VERSION 5.8 ;
BUSBITCHARS "[]" ;
DIVIDERCHAR "/" ;
UNITS
    DATABASE MICRONS 1000 ;
END UNITS

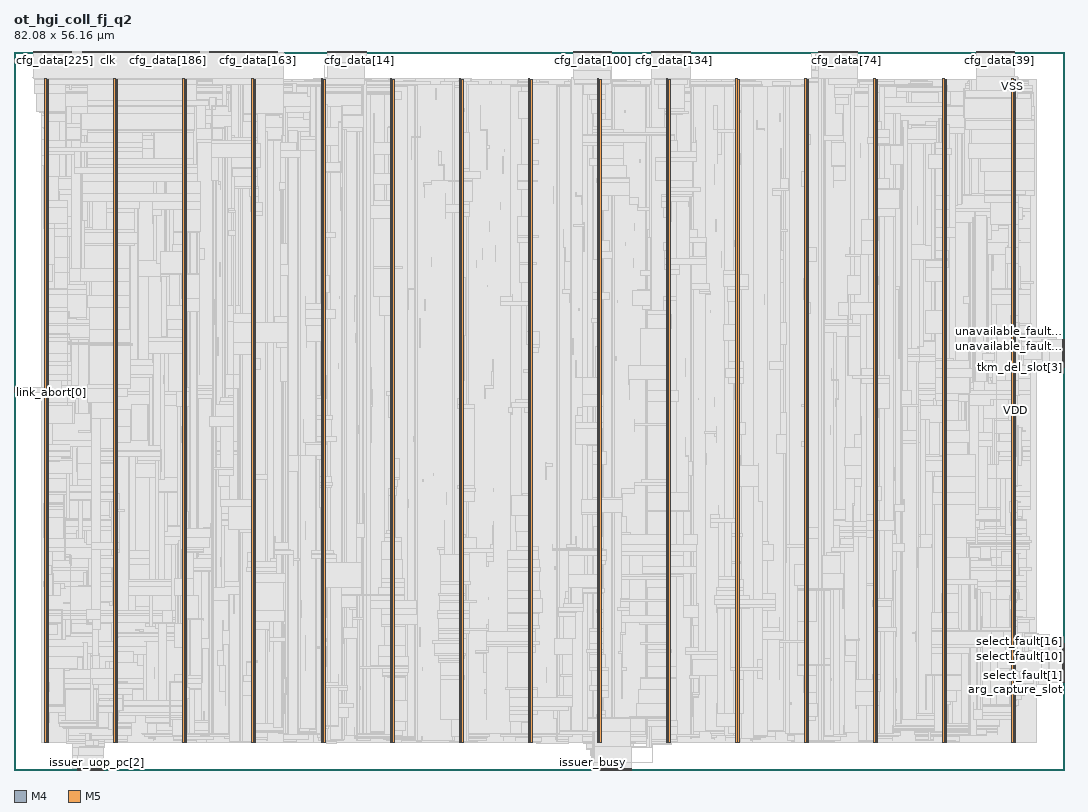
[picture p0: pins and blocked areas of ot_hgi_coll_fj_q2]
MACRO ot_hgi_coll_fj_q2
  FOREIGN ot_hgi_coll_fj_q2 0 0 ;
  CLASS BLOCK ;
  SIZE 82.08 BY 56.16 ;
  PIN arg_capture_slot
    DIRECTION INPUT ;
    USE SIGNAL ;
    PORT
      LAYER M4 ;
        RECT  81.996 6.864 82.08 6.888 ;
    END
  END arg_capture_slot
  PIN capture_fault[0]
    DIRECTION INPUT ;
    USE SIGNAL ;
    PORT
      LAYER M4 ;
        RECT  81.996 6.96 82.08 6.984 ;
    END
  END capture_fault[0]
  PIN capture_fault[1]
    DIRECTION INPUT ;
    USE SIGNAL ;
    PORT
      LAYER M4 ;
        RECT  81.996 7.056 82.08 7.08 ;
    END
  END capture_fault[1]
  PIN capture_fault[2]
    DIRECTION INPUT ;
    USE SIGNAL ;
    PORT
      LAYER M4 ;
        RECT  81.996 7.152 82.08 7.176 ;
    END
  END capture_fault[2]
  PIN capture_fault[3]
    DIRECTION INPUT ;
    USE SIGNAL ;
    PORT
      LAYER M4 ;
        RECT  81.996 7.248 82.08 7.272 ;
    END
  END capture_fault[3]
  PIN capture_fault[4]
    DIRECTION INPUT ;
    USE SIGNAL ;
    PORT
      LAYER M4 ;
        RECT  81.996 7.344 82.08 7.368 ;
    END
  END capture_fault[4]
  PIN capture_fault[5]
    DIRECTION INPUT ;
    USE SIGNAL ;
    PORT
      LAYER M4 ;
        RECT  81.996 7.44 82.08 7.464 ;
    END
  END capture_fault[5]
  PIN capture_fault[6]
    DIRECTION INPUT ;
    USE SIGNAL ;
    PORT
      LAYER M4 ;
        RECT  81.996 7.536 82.08 7.56 ;
    END
  END capture_fault[6]
  PIN capture_fault[7]
    DIRECTION INPUT ;
    USE SIGNAL ;
    PORT
      LAYER M4 ;
        RECT  81.996 7.632 82.08 7.656 ;
    END
  END capture_fault[7]
  PIN capture_fault[8]
    DIRECTION INPUT ;
    USE SIGNAL ;
    PORT
      LAYER M4 ;
        RECT  81.996 7.728 82.08 7.752 ;
    END
  END capture_fault[8]
  PIN cfg_addr[0]
    DIRECTION INPUT ;
    USE SIGNAL ;
    PORT
      LAYER M5 ;
        RECT  24.528 56.076 24.552 56.16 ;
    END
  END cfg_addr[0]
  PIN cfg_addr[10]
    DIRECTION INPUT ;
    USE SIGNAL ;
    PORT
      LAYER M5 ;
        RECT  25.488 56.076 25.512 56.16 ;
    END
  END cfg_addr[10]
  PIN cfg_addr[11]
    DIRECTION INPUT ;
    USE SIGNAL ;
    PORT
      LAYER M5 ;
        RECT  25.584 56.076 25.608 56.16 ;
    END
  END cfg_addr[11]
  PIN cfg_addr[1]
    DIRECTION INPUT ;
    USE SIGNAL ;
    PORT
      LAYER M5 ;
        RECT  24.624 56.076 24.648 56.16 ;
    END
  END cfg_addr[1]
  PIN cfg_addr[2]
    DIRECTION INPUT ;
    USE SIGNAL ;
    PORT
      LAYER M5 ;
        RECT  24.72 56.076 24.744 56.16 ;
    END
  END cfg_addr[2]
  PIN cfg_addr[3]
    DIRECTION INPUT ;
    USE SIGNAL ;
    PORT
      LAYER M5 ;
        RECT  24.816 56.076 24.84 56.16 ;
    END
  END cfg_addr[3]
  PIN cfg_addr[4]
    DIRECTION INPUT ;
    USE SIGNAL ;
    PORT
      LAYER M5 ;
        RECT  24.912 56.076 24.936 56.16 ;
    END
  END cfg_addr[4]
  PIN cfg_addr[5]
    DIRECTION INPUT ;
    USE SIGNAL ;
    PORT
      LAYER M5 ;
        RECT  25.008 56.076 25.032 56.16 ;
    END
  END cfg_addr[5]
  PIN cfg_addr[6]
    DIRECTION INPUT ;
    USE SIGNAL ;
    PORT
      LAYER M5 ;
        RECT  25.104 56.076 25.128 56.16 ;
    END
  END cfg_addr[6]
  PIN cfg_addr[7]
    DIRECTION INPUT ;
    USE SIGNAL ;
    PORT
      LAYER M5 ;
        RECT  25.2 56.076 25.224 56.16 ;
    END
  END cfg_addr[7]
  PIN cfg_addr[8]
    DIRECTION INPUT ;
    USE SIGNAL ;
    PORT
      LAYER M5 ;
        RECT  25.296 56.076 25.32 56.16 ;
    END
  END cfg_addr[8]
  PIN cfg_addr[9]
    DIRECTION INPUT ;
    USE SIGNAL ;
    PORT
      LAYER M5 ;
        RECT  25.392 56.076 25.416 56.16 ;
    END
  END cfg_addr[9]
  PIN cfg_data[0]
    DIRECTION INPUT ;
    USE SIGNAL ;
    PORT
      LAYER M5 ;
        RECT  25.68 56.076 25.704 56.16 ;
    END
  END cfg_data[0]
  PIN cfg_data[100]
    DIRECTION INPUT ;
    USE SIGNAL ;
    PORT
      LAYER M5 ;
        RECT  45.264 56.076 45.288 56.16 ;
    END
  END cfg_data[100]
  PIN cfg_data[101]
    DIRECTION INPUT ;
    USE SIGNAL ;
    PORT
      LAYER M5 ;
        RECT  45.36 56.076 45.384 56.16 ;
    END
  END cfg_data[101]
  PIN cfg_data[102]
    DIRECTION INPUT ;
    USE SIGNAL ;
    PORT
      LAYER M5 ;
        RECT  45.456 56.076 45.48 56.16 ;
    END
  END cfg_data[102]
  PIN cfg_data[103]
    DIRECTION INPUT ;
    USE SIGNAL ;
    PORT
      LAYER M5 ;
        RECT  45.552 56.076 45.576 56.16 ;
    END
  END cfg_data[103]
  PIN cfg_data[104]
    DIRECTION INPUT ;
    USE SIGNAL ;
    PORT
      LAYER M5 ;
        RECT  45.648 56.076 45.672 56.16 ;
    END
  END cfg_data[104]
  PIN cfg_data[105]
    DIRECTION INPUT ;
    USE SIGNAL ;
    PORT
      LAYER M5 ;
        RECT  45.744 56.076 45.768 56.16 ;
    END
  END cfg_data[105]
  PIN cfg_data[106]
    DIRECTION INPUT ;
    USE SIGNAL ;
    PORT
      LAYER M5 ;
        RECT  45.84 56.076 45.864 56.16 ;
    END
  END cfg_data[106]
  PIN cfg_data[107]
    DIRECTION INPUT ;
    USE SIGNAL ;
    PORT
      LAYER M5 ;
        RECT  45.936 56.076 45.96 56.16 ;
    END
  END cfg_data[107]
  PIN cfg_data[108]
    DIRECTION INPUT ;
    USE SIGNAL ;
    PORT
      LAYER M5 ;
        RECT  46.032 56.076 46.056 56.16 ;
    END
  END cfg_data[108]
  PIN cfg_data[109]
    DIRECTION INPUT ;
    USE SIGNAL ;
    PORT
      LAYER M5 ;
        RECT  46.128 56.076 46.152 56.16 ;
    END
  END cfg_data[109]
  PIN cfg_data[10]
    DIRECTION INPUT ;
    USE SIGNAL ;
    PORT
      LAYER M5 ;
        RECT  26.64 56.076 26.664 56.16 ;
    END
  END cfg_data[10]
  PIN cfg_data[110]
    DIRECTION INPUT ;
    USE SIGNAL ;
    PORT
      LAYER M5 ;
        RECT  46.224 56.076 46.248 56.16 ;
    END
  END cfg_data[110]
  PIN cfg_data[111]
    DIRECTION INPUT ;
    USE SIGNAL ;
    PORT
      LAYER M5 ;
        RECT  46.32 56.076 46.344 56.16 ;
    END
  END cfg_data[111]
  PIN cfg_data[112]
    DIRECTION INPUT ;
    USE SIGNAL ;
    PORT
      LAYER M5 ;
        RECT  46.416 56.076 46.44 56.16 ;
    END
  END cfg_data[112]
  PIN cfg_data[113]
    DIRECTION INPUT ;
    USE SIGNAL ;
    PORT
      LAYER M5 ;
        RECT  46.512 56.076 46.536 56.16 ;
    END
  END cfg_data[113]
  PIN cfg_data[114]
    DIRECTION INPUT ;
    USE SIGNAL ;
    PORT
      LAYER M5 ;
        RECT  46.608 56.076 46.632 56.16 ;
    END
  END cfg_data[114]
  PIN cfg_data[115]
    DIRECTION INPUT ;
    USE SIGNAL ;
    PORT
      LAYER M5 ;
        RECT  46.704 56.076 46.728 56.16 ;
    END
  END cfg_data[115]
  PIN cfg_data[116]
    DIRECTION INPUT ;
    USE SIGNAL ;
    PORT
      LAYER M5 ;
        RECT  49.872 56.076 49.896 56.16 ;
    END
  END cfg_data[116]
  PIN cfg_data[117]
    DIRECTION INPUT ;
    USE SIGNAL ;
    PORT
      LAYER M5 ;
        RECT  49.968 56.076 49.992 56.16 ;
    END
  END cfg_data[117]
  PIN cfg_data[118]
    DIRECTION INPUT ;
    USE SIGNAL ;
    PORT
      LAYER M5 ;
        RECT  50.064 56.076 50.088 56.16 ;
    END
  END cfg_data[118]
  PIN cfg_data[119]
    DIRECTION INPUT ;
    USE SIGNAL ;
    PORT
      LAYER M5 ;
        RECT  50.16 56.076 50.184 56.16 ;
    END
  END cfg_data[119]
  PIN cfg_data[11]
    DIRECTION INPUT ;
    USE SIGNAL ;
    PORT
      LAYER M5 ;
        RECT  26.736 56.076 26.76 56.16 ;
    END
  END cfg_data[11]
  PIN cfg_data[120]
    DIRECTION INPUT ;
    USE SIGNAL ;
    PORT
      LAYER M5 ;
        RECT  50.256 56.076 50.28 56.16 ;
    END
  END cfg_data[120]
  PIN cfg_data[121]
    DIRECTION INPUT ;
    USE SIGNAL ;
    PORT
      LAYER M5 ;
        RECT  50.352 56.076 50.376 56.16 ;
    END
  END cfg_data[121]
  PIN cfg_data[122]
    DIRECTION INPUT ;
    USE SIGNAL ;
    PORT
      LAYER M5 ;
        RECT  50.448 56.076 50.472 56.16 ;
    END
  END cfg_data[122]
  PIN cfg_data[123]
    DIRECTION INPUT ;
    USE SIGNAL ;
    PORT
      LAYER M5 ;
        RECT  50.544 56.076 50.568 56.16 ;
    END
  END cfg_data[123]
  PIN cfg_data[124]
    DIRECTION INPUT ;
    USE SIGNAL ;
    PORT
      LAYER M5 ;
        RECT  50.64 56.076 50.664 56.16 ;
    END
  END cfg_data[124]
  PIN cfg_data[125]
    DIRECTION INPUT ;
    USE SIGNAL ;
    PORT
      LAYER M5 ;
        RECT  50.736 56.076 50.76 56.16 ;
    END
  END cfg_data[125]
  PIN cfg_data[126]
    DIRECTION INPUT ;
    USE SIGNAL ;
    PORT
      LAYER M5 ;
        RECT  50.832 56.076 50.856 56.16 ;
    END
  END cfg_data[126]
  PIN cfg_data[127]
    DIRECTION INPUT ;
    USE SIGNAL ;
    PORT
      LAYER M5 ;
        RECT  50.928 56.076 50.952 56.16 ;
    END
  END cfg_data[127]
  PIN cfg_data[128]
    DIRECTION INPUT ;
    USE SIGNAL ;
    PORT
      LAYER M5 ;
        RECT  51.024 56.076 51.048 56.16 ;
    END
  END cfg_data[128]
  PIN cfg_data[129]
    DIRECTION INPUT ;
    USE SIGNAL ;
    PORT
      LAYER M5 ;
        RECT  51.12 56.076 51.144 56.16 ;
    END
  END cfg_data[129]
  PIN cfg_data[12]
    DIRECTION INPUT ;
    USE SIGNAL ;
    PORT
      LAYER M5 ;
        RECT  26.832 56.076 26.856 56.16 ;
    END
  END cfg_data[12]
  PIN cfg_data[130]
    DIRECTION INPUT ;
    USE SIGNAL ;
    PORT
      LAYER M5 ;
        RECT  51.216 56.076 51.24 56.16 ;
    END
  END cfg_data[130]
  PIN cfg_data[131]
    DIRECTION INPUT ;
    USE SIGNAL ;
    PORT
      LAYER M5 ;
        RECT  51.312 56.076 51.336 56.16 ;
    END
  END cfg_data[131]
  PIN cfg_data[132]
    DIRECTION INPUT ;
    USE SIGNAL ;
    PORT
      LAYER M5 ;
        RECT  51.408 56.076 51.432 56.16 ;
    END
  END cfg_data[132]
  PIN cfg_data[133]
    DIRECTION INPUT ;
    USE SIGNAL ;
    PORT
      LAYER M5 ;
        RECT  51.504 56.076 51.528 56.16 ;
    END
  END cfg_data[133]
  PIN cfg_data[134]
    DIRECTION INPUT ;
    USE SIGNAL ;
    PORT
      LAYER M5 ;
        RECT  51.6 56.076 51.624 56.16 ;
    END
  END cfg_data[134]
  PIN cfg_data[135]
    DIRECTION INPUT ;
    USE SIGNAL ;
    PORT
      LAYER M5 ;
        RECT  51.696 56.076 51.72 56.16 ;
    END
  END cfg_data[135]
  PIN cfg_data[136]
    DIRECTION INPUT ;
    USE SIGNAL ;
    PORT
      LAYER M5 ;
        RECT  51.792 56.076 51.816 56.16 ;
    END
  END cfg_data[136]
  PIN cfg_data[137]
    DIRECTION INPUT ;
    USE SIGNAL ;
    PORT
      LAYER M5 ;
        RECT  51.888 56.076 51.912 56.16 ;
    END
  END cfg_data[137]
  PIN cfg_data[138]
    DIRECTION INPUT ;
    USE SIGNAL ;
    PORT
      LAYER M5 ;
        RECT  51.984 56.076 52.008 56.16 ;
    END
  END cfg_data[138]
  PIN cfg_data[139]
    DIRECTION INPUT ;
    USE SIGNAL ;
    PORT
      LAYER M5 ;
        RECT  52.08 56.076 52.104 56.16 ;
    END
  END cfg_data[139]
  PIN cfg_data[13]
    DIRECTION INPUT ;
    USE SIGNAL ;
    PORT
      LAYER M5 ;
        RECT  26.928 56.076 26.952 56.16 ;
    END
  END cfg_data[13]
  PIN cfg_data[140]
    DIRECTION INPUT ;
    USE SIGNAL ;
    PORT
      LAYER M5 ;
        RECT  52.176 56.076 52.2 56.16 ;
    END
  END cfg_data[140]
  PIN cfg_data[141]
    DIRECTION INPUT ;
    USE SIGNAL ;
    PORT
      LAYER M5 ;
        RECT  52.272 56.076 52.296 56.16 ;
    END
  END cfg_data[141]
  PIN cfg_data[142]
    DIRECTION INPUT ;
    USE SIGNAL ;
    PORT
      LAYER M5 ;
        RECT  52.368 56.076 52.392 56.16 ;
    END
  END cfg_data[142]
  PIN cfg_data[143]
    DIRECTION INPUT ;
    USE SIGNAL ;
    PORT
      LAYER M5 ;
        RECT  52.464 56.076 52.488 56.16 ;
    END
  END cfg_data[143]
  PIN cfg_data[144]
    DIRECTION INPUT ;
    USE SIGNAL ;
    PORT
      LAYER M5 ;
        RECT  52.56 56.076 52.584 56.16 ;
    END
  END cfg_data[144]
  PIN cfg_data[145]
    DIRECTION INPUT ;
    USE SIGNAL ;
    PORT
      LAYER M5 ;
        RECT  52.656 56.076 52.68 56.16 ;
    END
  END cfg_data[145]
  PIN cfg_data[146]
    DIRECTION INPUT ;
    USE SIGNAL ;
    PORT
      LAYER M5 ;
        RECT  52.752 56.076 52.776 56.16 ;
    END
  END cfg_data[146]
  PIN cfg_data[147]
    DIRECTION INPUT ;
    USE SIGNAL ;
    PORT
      LAYER M5 ;
        RECT  52.848 56.076 52.872 56.16 ;
    END
  END cfg_data[147]
  PIN cfg_data[148]
    DIRECTION INPUT ;
    USE SIGNAL ;
    PORT
      LAYER M5 ;
        RECT  17.616 56.076 17.64 56.16 ;
    END
  END cfg_data[148]
  PIN cfg_data[149]
    DIRECTION INPUT ;
    USE SIGNAL ;
    PORT
      LAYER M5 ;
        RECT  17.712 56.076 17.736 56.16 ;
    END
  END cfg_data[149]
  PIN cfg_data[14]
    DIRECTION INPUT ;
    USE SIGNAL ;
    PORT
      LAYER M5 ;
        RECT  27.024 56.076 27.048 56.16 ;
    END
  END cfg_data[14]
  PIN cfg_data[150]
    DIRECTION INPUT ;
    USE SIGNAL ;
    PORT
      LAYER M5 ;
        RECT  17.808 56.076 17.832 56.16 ;
    END
  END cfg_data[150]
  PIN cfg_data[151]
    DIRECTION INPUT ;
    USE SIGNAL ;
    PORT
      LAYER M5 ;
        RECT  17.904 56.076 17.928 56.16 ;
    END
  END cfg_data[151]
  PIN cfg_data[152]
    DIRECTION INPUT ;
    USE SIGNAL ;
    PORT
      LAYER M5 ;
        RECT  18 56.076 18.024 56.16 ;
    END
  END cfg_data[152]
  PIN cfg_data[153]
    DIRECTION INPUT ;
    USE SIGNAL ;
    PORT
      LAYER M5 ;
        RECT  18.096 56.076 18.12 56.16 ;
    END
  END cfg_data[153]
  PIN cfg_data[154]
    DIRECTION INPUT ;
    USE SIGNAL ;
    PORT
      LAYER M5 ;
        RECT  18.192 56.076 18.216 56.16 ;
    END
  END cfg_data[154]
  PIN cfg_data[155]
    DIRECTION INPUT ;
    USE SIGNAL ;
    PORT
      LAYER M5 ;
        RECT  18.288 56.076 18.312 56.16 ;
    END
  END cfg_data[155]
  PIN cfg_data[156]
    DIRECTION INPUT ;
    USE SIGNAL ;
    PORT
      LAYER M5 ;
        RECT  18.384 56.076 18.408 56.16 ;
    END
  END cfg_data[156]
  PIN cfg_data[157]
    DIRECTION INPUT ;
    USE SIGNAL ;
    PORT
      LAYER M5 ;
        RECT  18.48 56.076 18.504 56.16 ;
    END
  END cfg_data[157]
  PIN cfg_data[158]
    DIRECTION INPUT ;
    USE SIGNAL ;
    PORT
      LAYER M5 ;
        RECT  18.576 56.076 18.6 56.16 ;
    END
  END cfg_data[158]
  PIN cfg_data[159]
    DIRECTION INPUT ;
    USE SIGNAL ;
    PORT
      LAYER M5 ;
        RECT  18.672 56.076 18.696 56.16 ;
    END
  END cfg_data[159]
  PIN cfg_data[15]
    DIRECTION INPUT ;
    USE SIGNAL ;
    PORT
      LAYER M5 ;
        RECT  27.12 56.076 27.144 56.16 ;
    END
  END cfg_data[15]
  PIN cfg_data[160]
    DIRECTION INPUT ;
    USE SIGNAL ;
    PORT
      LAYER M5 ;
        RECT  18.768 56.076 18.792 56.16 ;
    END
  END cfg_data[160]
  PIN cfg_data[161]
    DIRECTION INPUT ;
    USE SIGNAL ;
    PORT
      LAYER M5 ;
        RECT  18.864 56.076 18.888 56.16 ;
    END
  END cfg_data[161]
  PIN cfg_data[162]
    DIRECTION INPUT ;
    USE SIGNAL ;
    PORT
      LAYER M5 ;
        RECT  18.96 56.076 18.984 56.16 ;
    END
  END cfg_data[162]
  PIN cfg_data[163]
    DIRECTION INPUT ;
    USE SIGNAL ;
    PORT
      LAYER M5 ;
        RECT  19.056 56.076 19.08 56.16 ;
    END
  END cfg_data[163]
  PIN cfg_data[164]
    DIRECTION INPUT ;
    USE SIGNAL ;
    PORT
      LAYER M5 ;
        RECT  19.152 56.076 19.176 56.16 ;
    END
  END cfg_data[164]
  PIN cfg_data[165]
    DIRECTION INPUT ;
    USE SIGNAL ;
    PORT
      LAYER M5 ;
        RECT  19.248 56.076 19.272 56.16 ;
    END
  END cfg_data[165]
  PIN cfg_data[166]
    DIRECTION INPUT ;
    USE SIGNAL ;
    PORT
      LAYER M5 ;
        RECT  19.344 56.076 19.368 56.16 ;
    END
  END cfg_data[166]
  PIN cfg_data[167]
    DIRECTION INPUT ;
    USE SIGNAL ;
    PORT
      LAYER M5 ;
        RECT  19.44 56.076 19.464 56.16 ;
    END
  END cfg_data[167]
  PIN cfg_data[168]
    DIRECTION INPUT ;
    USE SIGNAL ;
    PORT
      LAYER M5 ;
        RECT  19.536 56.076 19.56 56.16 ;
    END
  END cfg_data[168]
  PIN cfg_data[169]
    DIRECTION INPUT ;
    USE SIGNAL ;
    PORT
      LAYER M5 ;
        RECT  19.632 56.076 19.656 56.16 ;
    END
  END cfg_data[169]
  PIN cfg_data[16]
    DIRECTION INPUT ;
    USE SIGNAL ;
    PORT
      LAYER M5 ;
        RECT  27.216 56.076 27.24 56.16 ;
    END
  END cfg_data[16]
  PIN cfg_data[170]
    DIRECTION INPUT ;
    USE SIGNAL ;
    PORT
      LAYER M5 ;
        RECT  19.728 56.076 19.752 56.16 ;
    END
  END cfg_data[170]
  PIN cfg_data[171]
    DIRECTION INPUT ;
    USE SIGNAL ;
    PORT
      LAYER M5 ;
        RECT  19.824 56.076 19.848 56.16 ;
    END
  END cfg_data[171]
  PIN cfg_data[172]
    DIRECTION INPUT ;
    USE SIGNAL ;
    PORT
      LAYER M5 ;
        RECT  19.92 56.076 19.944 56.16 ;
    END
  END cfg_data[172]
  PIN cfg_data[173]
    DIRECTION INPUT ;
    USE SIGNAL ;
    PORT
      LAYER M5 ;
        RECT  20.016 56.076 20.04 56.16 ;
    END
  END cfg_data[173]
  PIN cfg_data[174]
    DIRECTION INPUT ;
    USE SIGNAL ;
    PORT
      LAYER M5 ;
        RECT  20.112 56.076 20.136 56.16 ;
    END
  END cfg_data[174]
  PIN cfg_data[175]
    DIRECTION INPUT ;
    USE SIGNAL ;
    PORT
      LAYER M5 ;
        RECT  20.208 56.076 20.232 56.16 ;
    END
  END cfg_data[175]
  PIN cfg_data[176]
    DIRECTION INPUT ;
    USE SIGNAL ;
    PORT
      LAYER M5 ;
        RECT  20.304 56.076 20.328 56.16 ;
    END
  END cfg_data[176]
  PIN cfg_data[177]
    DIRECTION INPUT ;
    USE SIGNAL ;
    PORT
      LAYER M5 ;
        RECT  20.4 56.076 20.424 56.16 ;
    END
  END cfg_data[177]
  PIN cfg_data[178]
    DIRECTION INPUT ;
    USE SIGNAL ;
    PORT
      LAYER M5 ;
        RECT  20.496 56.076 20.52 56.16 ;
    END
  END cfg_data[178]
  PIN cfg_data[179]
    DIRECTION INPUT ;
    USE SIGNAL ;
    PORT
      LAYER M5 ;
        RECT  20.592 56.076 20.616 56.16 ;
    END
  END cfg_data[179]
  PIN cfg_data[17]
    DIRECTION INPUT ;
    USE SIGNAL ;
    PORT
      LAYER M5 ;
        RECT  27.312 56.076 27.336 56.16 ;
    END
  END cfg_data[17]
  PIN cfg_data[180]
    DIRECTION INPUT ;
    USE SIGNAL ;
    PORT
      LAYER M5 ;
        RECT  11.472 56.076 11.496 56.16 ;
    END
  END cfg_data[180]
  PIN cfg_data[181]
    DIRECTION INPUT ;
    USE SIGNAL ;
    PORT
      LAYER M5 ;
        RECT  11.568 56.076 11.592 56.16 ;
    END
  END cfg_data[181]
  PIN cfg_data[182]
    DIRECTION INPUT ;
    USE SIGNAL ;
    PORT
      LAYER M5 ;
        RECT  11.664 56.076 11.688 56.16 ;
    END
  END cfg_data[182]
  PIN cfg_data[183]
    DIRECTION INPUT ;
    USE SIGNAL ;
    PORT
      LAYER M5 ;
        RECT  11.76 56.076 11.784 56.16 ;
    END
  END cfg_data[183]
  PIN cfg_data[184]
    DIRECTION INPUT ;
    USE SIGNAL ;
    PORT
      LAYER M5 ;
        RECT  11.856 56.076 11.88 56.16 ;
    END
  END cfg_data[184]
  PIN cfg_data[185]
    DIRECTION INPUT ;
    USE SIGNAL ;
    PORT
      LAYER M5 ;
        RECT  11.952 56.076 11.976 56.16 ;
    END
  END cfg_data[185]
  PIN cfg_data[186]
    DIRECTION INPUT ;
    USE SIGNAL ;
    PORT
      LAYER M5 ;
        RECT  12.048 56.076 12.072 56.16 ;
    END
  END cfg_data[186]
  PIN cfg_data[187]
    DIRECTION INPUT ;
    USE SIGNAL ;
    PORT
      LAYER M5 ;
        RECT  12.144 56.076 12.168 56.16 ;
    END
  END cfg_data[187]
  PIN cfg_data[188]
    DIRECTION INPUT ;
    USE SIGNAL ;
    PORT
      LAYER M5 ;
        RECT  12.24 56.076 12.264 56.16 ;
    END
  END cfg_data[188]
  PIN cfg_data[189]
    DIRECTION INPUT ;
    USE SIGNAL ;
    PORT
      LAYER M5 ;
        RECT  12.336 56.076 12.36 56.16 ;
    END
  END cfg_data[189]
  PIN cfg_data[18]
    DIRECTION INPUT ;
    USE SIGNAL ;
    PORT
      LAYER M5 ;
        RECT  27.408 56.076 27.432 56.16 ;
    END
  END cfg_data[18]
  PIN cfg_data[190]
    DIRECTION INPUT ;
    USE SIGNAL ;
    PORT
      LAYER M5 ;
        RECT  12.432 56.076 12.456 56.16 ;
    END
  END cfg_data[190]
  PIN cfg_data[191]
    DIRECTION INPUT ;
    USE SIGNAL ;
    PORT
      LAYER M5 ;
        RECT  12.528 56.076 12.552 56.16 ;
    END
  END cfg_data[191]
  PIN cfg_data[192]
    DIRECTION INPUT ;
    USE SIGNAL ;
    PORT
      LAYER M5 ;
        RECT  12.624 56.076 12.648 56.16 ;
    END
  END cfg_data[192]
  PIN cfg_data[193]
    DIRECTION INPUT ;
    USE SIGNAL ;
    PORT
      LAYER M5 ;
        RECT  12.72 56.076 12.744 56.16 ;
    END
  END cfg_data[193]
  PIN cfg_data[194]
    DIRECTION INPUT ;
    USE SIGNAL ;
    PORT
      LAYER M5 ;
        RECT  12.816 56.076 12.84 56.16 ;
    END
  END cfg_data[194]
  PIN cfg_data[195]
    DIRECTION INPUT ;
    USE SIGNAL ;
    PORT
      LAYER M5 ;
        RECT  12.912 56.076 12.936 56.16 ;
    END
  END cfg_data[195]
  PIN cfg_data[196]
    DIRECTION INPUT ;
    USE SIGNAL ;
    PORT
      LAYER M5 ;
        RECT  13.008 56.076 13.032 56.16 ;
    END
  END cfg_data[196]
  PIN cfg_data[197]
    DIRECTION INPUT ;
    USE SIGNAL ;
    PORT
      LAYER M5 ;
        RECT  13.104 56.076 13.128 56.16 ;
    END
  END cfg_data[197]
  PIN cfg_data[198]
    DIRECTION INPUT ;
    USE SIGNAL ;
    PORT
      LAYER M5 ;
        RECT  13.2 56.076 13.224 56.16 ;
    END
  END cfg_data[198]
  PIN cfg_data[199]
    DIRECTION INPUT ;
    USE SIGNAL ;
    PORT
      LAYER M5 ;
        RECT  13.296 56.076 13.32 56.16 ;
    END
  END cfg_data[199]
  PIN cfg_data[19]
    DIRECTION INPUT ;
    USE SIGNAL ;
    PORT
      LAYER M5 ;
        RECT  27.504 56.076 27.528 56.16 ;
    END
  END cfg_data[19]
  PIN cfg_data[1]
    DIRECTION INPUT ;
    USE SIGNAL ;
    PORT
      LAYER M5 ;
        RECT  25.776 56.076 25.8 56.16 ;
    END
  END cfg_data[1]
  PIN cfg_data[200]
    DIRECTION INPUT ;
    USE SIGNAL ;
    PORT
      LAYER M5 ;
        RECT  13.392 56.076 13.416 56.16 ;
    END
  END cfg_data[200]
  PIN cfg_data[201]
    DIRECTION INPUT ;
    USE SIGNAL ;
    PORT
      LAYER M5 ;
        RECT  13.488 56.076 13.512 56.16 ;
    END
  END cfg_data[201]
  PIN cfg_data[202]
    DIRECTION INPUT ;
    USE SIGNAL ;
    PORT
      LAYER M5 ;
        RECT  13.584 56.076 13.608 56.16 ;
    END
  END cfg_data[202]
  PIN cfg_data[203]
    DIRECTION INPUT ;
    USE SIGNAL ;
    PORT
      LAYER M5 ;
        RECT  13.68 56.076 13.704 56.16 ;
    END
  END cfg_data[203]
  PIN cfg_data[204]
    DIRECTION INPUT ;
    USE SIGNAL ;
    PORT
      LAYER M5 ;
        RECT  13.776 56.076 13.8 56.16 ;
    END
  END cfg_data[204]
  PIN cfg_data[205]
    DIRECTION INPUT ;
    USE SIGNAL ;
    PORT
      LAYER M5 ;
        RECT  13.872 56.076 13.896 56.16 ;
    END
  END cfg_data[205]
  PIN cfg_data[206]
    DIRECTION INPUT ;
    USE SIGNAL ;
    PORT
      LAYER M5 ;
        RECT  13.968 56.076 13.992 56.16 ;
    END
  END cfg_data[206]
  PIN cfg_data[207]
    DIRECTION INPUT ;
    USE SIGNAL ;
    PORT
      LAYER M5 ;
        RECT  14.064 56.076 14.088 56.16 ;
    END
  END cfg_data[207]
  PIN cfg_data[208]
    DIRECTION INPUT ;
    USE SIGNAL ;
    PORT
      LAYER M5 ;
        RECT  14.16 56.076 14.184 56.16 ;
    END
  END cfg_data[208]
  PIN cfg_data[209]
    DIRECTION INPUT ;
    USE SIGNAL ;
    PORT
      LAYER M5 ;
        RECT  14.256 56.076 14.28 56.16 ;
    END
  END cfg_data[209]
  PIN cfg_data[20]
    DIRECTION INPUT ;
    USE SIGNAL ;
    PORT
      LAYER M5 ;
        RECT  75.216 56.076 75.24 56.16 ;
    END
  END cfg_data[20]
  PIN cfg_data[210]
    DIRECTION INPUT ;
    USE SIGNAL ;
    PORT
      LAYER M5 ;
        RECT  14.352 56.076 14.376 56.16 ;
    END
  END cfg_data[210]
  PIN cfg_data[211]
    DIRECTION INPUT ;
    USE SIGNAL ;
    PORT
      LAYER M5 ;
        RECT  14.448 56.076 14.472 56.16 ;
    END
  END cfg_data[211]
  PIN cfg_data[212]
    DIRECTION INPUT ;
    USE SIGNAL ;
    PORT
      LAYER M5 ;
        RECT  1.488 56.076 1.512 56.16 ;
    END
  END cfg_data[212]
  PIN cfg_data[213]
    DIRECTION INPUT ;
    USE SIGNAL ;
    PORT
      LAYER M5 ;
        RECT  1.584 56.076 1.608 56.16 ;
    END
  END cfg_data[213]
  PIN cfg_data[214]
    DIRECTION INPUT ;
    USE SIGNAL ;
    PORT
      LAYER M5 ;
        RECT  1.68 56.076 1.704 56.16 ;
    END
  END cfg_data[214]
  PIN cfg_data[215]
    DIRECTION INPUT ;
    USE SIGNAL ;
    PORT
      LAYER M5 ;
        RECT  1.776 56.076 1.8 56.16 ;
    END
  END cfg_data[215]
  PIN cfg_data[216]
    DIRECTION INPUT ;
    USE SIGNAL ;
    PORT
      LAYER M5 ;
        RECT  1.872 56.076 1.896 56.16 ;
    END
  END cfg_data[216]
  PIN cfg_data[217]
    DIRECTION INPUT ;
    USE SIGNAL ;
    PORT
      LAYER M5 ;
        RECT  1.968 56.076 1.992 56.16 ;
    END
  END cfg_data[217]
  PIN cfg_data[218]
    DIRECTION INPUT ;
    USE SIGNAL ;
    PORT
      LAYER M5 ;
        RECT  2.064 56.076 2.088 56.16 ;
    END
  END cfg_data[218]
  PIN cfg_data[219]
    DIRECTION INPUT ;
    USE SIGNAL ;
    PORT
      LAYER M5 ;
        RECT  2.16 56.076 2.184 56.16 ;
    END
  END cfg_data[219]
  PIN cfg_data[21]
    DIRECTION INPUT ;
    USE SIGNAL ;
    PORT
      LAYER M5 ;
        RECT  75.312 56.076 75.336 56.16 ;
    END
  END cfg_data[21]
  PIN cfg_data[220]
    DIRECTION INPUT ;
    USE SIGNAL ;
    PORT
      LAYER M5 ;
        RECT  2.256 56.076 2.28 56.16 ;
    END
  END cfg_data[220]
  PIN cfg_data[221]
    DIRECTION INPUT ;
    USE SIGNAL ;
    PORT
      LAYER M5 ;
        RECT  2.352 56.076 2.376 56.16 ;
    END
  END cfg_data[221]
  PIN cfg_data[222]
    DIRECTION INPUT ;
    USE SIGNAL ;
    PORT
      LAYER M5 ;
        RECT  2.448 56.076 2.472 56.16 ;
    END
  END cfg_data[222]
  PIN cfg_data[223]
    DIRECTION INPUT ;
    USE SIGNAL ;
    PORT
      LAYER M5 ;
        RECT  2.544 56.076 2.568 56.16 ;
    END
  END cfg_data[223]
  PIN cfg_data[224]
    DIRECTION INPUT ;
    USE SIGNAL ;
    PORT
      LAYER M5 ;
        RECT  2.64 56.076 2.664 56.16 ;
    END
  END cfg_data[224]
  PIN cfg_data[225]
    DIRECTION INPUT ;
    USE SIGNAL ;
    PORT
      LAYER M5 ;
        RECT  2.736 56.076 2.76 56.16 ;
    END
  END cfg_data[225]
  PIN cfg_data[226]
    DIRECTION INPUT ;
    USE SIGNAL ;
    PORT
      LAYER M5 ;
        RECT  2.832 56.076 2.856 56.16 ;
    END
  END cfg_data[226]
  PIN cfg_data[227]
    DIRECTION INPUT ;
    USE SIGNAL ;
    PORT
      LAYER M5 ;
        RECT  2.928 56.076 2.952 56.16 ;
    END
  END cfg_data[227]
  PIN cfg_data[228]
    DIRECTION INPUT ;
    USE SIGNAL ;
    PORT
      LAYER M5 ;
        RECT  3.024 56.076 3.048 56.16 ;
    END
  END cfg_data[228]
  PIN cfg_data[229]
    DIRECTION INPUT ;
    USE SIGNAL ;
    PORT
      LAYER M5 ;
        RECT  3.12 56.076 3.144 56.16 ;
    END
  END cfg_data[229]
  PIN cfg_data[22]
    DIRECTION INPUT ;
    USE SIGNAL ;
    PORT
      LAYER M5 ;
        RECT  75.408 56.076 75.432 56.16 ;
    END
  END cfg_data[22]
  PIN cfg_data[230]
    DIRECTION INPUT ;
    USE SIGNAL ;
    PORT
      LAYER M5 ;
        RECT  3.216 56.076 3.24 56.16 ;
    END
  END cfg_data[230]
  PIN cfg_data[231]
    DIRECTION INPUT ;
    USE SIGNAL ;
    PORT
      LAYER M5 ;
        RECT  3.312 56.076 3.336 56.16 ;
    END
  END cfg_data[231]
  PIN cfg_data[232]
    DIRECTION INPUT ;
    USE SIGNAL ;
    PORT
      LAYER M5 ;
        RECT  3.408 56.076 3.432 56.16 ;
    END
  END cfg_data[232]
  PIN cfg_data[233]
    DIRECTION INPUT ;
    USE SIGNAL ;
    PORT
      LAYER M5 ;
        RECT  3.504 56.076 3.528 56.16 ;
    END
  END cfg_data[233]
  PIN cfg_data[234]
    DIRECTION INPUT ;
    USE SIGNAL ;
    PORT
      LAYER M5 ;
        RECT  3.6 56.076 3.624 56.16 ;
    END
  END cfg_data[234]
  PIN cfg_data[235]
    DIRECTION INPUT ;
    USE SIGNAL ;
    PORT
      LAYER M5 ;
        RECT  3.696 56.076 3.72 56.16 ;
    END
  END cfg_data[235]
  PIN cfg_data[236]
    DIRECTION INPUT ;
    USE SIGNAL ;
    PORT
      LAYER M5 ;
        RECT  3.792 56.076 3.816 56.16 ;
    END
  END cfg_data[236]
  PIN cfg_data[237]
    DIRECTION INPUT ;
    USE SIGNAL ;
    PORT
      LAYER M5 ;
        RECT  3.888 56.076 3.912 56.16 ;
    END
  END cfg_data[237]
  PIN cfg_data[238]
    DIRECTION INPUT ;
    USE SIGNAL ;
    PORT
      LAYER M5 ;
        RECT  3.984 56.076 4.008 56.16 ;
    END
  END cfg_data[238]
  PIN cfg_data[239]
    DIRECTION INPUT ;
    USE SIGNAL ;
    PORT
      LAYER M5 ;
        RECT  4.08 56.076 4.104 56.16 ;
    END
  END cfg_data[239]
  PIN cfg_data[23]
    DIRECTION INPUT ;
    USE SIGNAL ;
    PORT
      LAYER M5 ;
        RECT  75.504 56.076 75.528 56.16 ;
    END
  END cfg_data[23]
  PIN cfg_data[240]
    DIRECTION INPUT ;
    USE SIGNAL ;
    PORT
      LAYER M5 ;
        RECT  4.176 56.076 4.2 56.16 ;
    END
  END cfg_data[240]
  PIN cfg_data[241]
    DIRECTION INPUT ;
    USE SIGNAL ;
    PORT
      LAYER M5 ;
        RECT  4.272 56.076 4.296 56.16 ;
    END
  END cfg_data[241]
  PIN cfg_data[242]
    DIRECTION INPUT ;
    USE SIGNAL ;
    PORT
      LAYER M5 ;
        RECT  4.368 56.076 4.392 56.16 ;
    END
  END cfg_data[242]
  PIN cfg_data[243]
    DIRECTION INPUT ;
    USE SIGNAL ;
    PORT
      LAYER M5 ;
        RECT  4.464 56.076 4.488 56.16 ;
    END
  END cfg_data[243]
  PIN cfg_data[244]
    DIRECTION INPUT ;
    USE SIGNAL ;
    PORT
      LAYER M5 ;
        RECT  5.328 56.076 5.352 56.16 ;
    END
  END cfg_data[244]
  PIN cfg_data[245]
    DIRECTION INPUT ;
    USE SIGNAL ;
    PORT
      LAYER M5 ;
        RECT  5.424 56.076 5.448 56.16 ;
    END
  END cfg_data[245]
  PIN cfg_data[246]
    DIRECTION INPUT ;
    USE SIGNAL ;
    PORT
      LAYER M5 ;
        RECT  5.52 56.076 5.544 56.16 ;
    END
  END cfg_data[246]
  PIN cfg_data[247]
    DIRECTION INPUT ;
    USE SIGNAL ;
    PORT
      LAYER M5 ;
        RECT  5.616 56.076 5.64 56.16 ;
    END
  END cfg_data[247]
  PIN cfg_data[248]
    DIRECTION INPUT ;
    USE SIGNAL ;
    PORT
      LAYER M5 ;
        RECT  5.712 56.076 5.736 56.16 ;
    END
  END cfg_data[248]
  PIN cfg_data[249]
    DIRECTION INPUT ;
    USE SIGNAL ;
    PORT
      LAYER M5 ;
        RECT  5.808 56.076 5.832 56.16 ;
    END
  END cfg_data[249]
  PIN cfg_data[24]
    DIRECTION INPUT ;
    USE SIGNAL ;
    PORT
      LAYER M5 ;
        RECT  75.6 56.076 75.624 56.16 ;
    END
  END cfg_data[24]
  PIN cfg_data[250]
    DIRECTION INPUT ;
    USE SIGNAL ;
    PORT
      LAYER M5 ;
        RECT  5.904 56.076 5.928 56.16 ;
    END
  END cfg_data[250]
  PIN cfg_data[251]
    DIRECTION INPUT ;
    USE SIGNAL ;
    PORT
      LAYER M5 ;
        RECT  6 56.076 6.024 56.16 ;
    END
  END cfg_data[251]
  PIN cfg_data[252]
    DIRECTION INPUT ;
    USE SIGNAL ;
    PORT
      LAYER M5 ;
        RECT  6.096 56.076 6.12 56.16 ;
    END
  END cfg_data[252]
  PIN cfg_data[253]
    DIRECTION INPUT ;
    USE SIGNAL ;
    PORT
      LAYER M5 ;
        RECT  6.192 56.076 6.216 56.16 ;
    END
  END cfg_data[253]
  PIN cfg_data[254]
    DIRECTION INPUT ;
    USE SIGNAL ;
    PORT
      LAYER M5 ;
        RECT  6.288 56.076 6.312 56.16 ;
    END
  END cfg_data[254]
  PIN cfg_data[255]
    DIRECTION INPUT ;
    USE SIGNAL ;
    PORT
      LAYER M5 ;
        RECT  6.384 56.076 6.408 56.16 ;
    END
  END cfg_data[255]
  PIN cfg_data[25]
    DIRECTION INPUT ;
    USE SIGNAL ;
    PORT
      LAYER M5 ;
        RECT  75.696 56.076 75.72 56.16 ;
    END
  END cfg_data[25]
  PIN cfg_data[26]
    DIRECTION INPUT ;
    USE SIGNAL ;
    PORT
      LAYER M5 ;
        RECT  75.792 56.076 75.816 56.16 ;
    END
  END cfg_data[26]
  PIN cfg_data[27]
    DIRECTION INPUT ;
    USE SIGNAL ;
    PORT
      LAYER M5 ;
        RECT  75.888 56.076 75.912 56.16 ;
    END
  END cfg_data[27]
  PIN cfg_data[28]
    DIRECTION INPUT ;
    USE SIGNAL ;
    PORT
      LAYER M5 ;
        RECT  75.984 56.076 76.008 56.16 ;
    END
  END cfg_data[28]
  PIN cfg_data[29]
    DIRECTION INPUT ;
    USE SIGNAL ;
    PORT
      LAYER M5 ;
        RECT  76.08 56.076 76.104 56.16 ;
    END
  END cfg_data[29]
  PIN cfg_data[2]
    DIRECTION INPUT ;
    USE SIGNAL ;
    PORT
      LAYER M5 ;
        RECT  25.872 56.076 25.896 56.16 ;
    END
  END cfg_data[2]
  PIN cfg_data[30]
    DIRECTION INPUT ;
    USE SIGNAL ;
    PORT
      LAYER M5 ;
        RECT  76.176 56.076 76.2 56.16 ;
    END
  END cfg_data[30]
  PIN cfg_data[31]
    DIRECTION INPUT ;
    USE SIGNAL ;
    PORT
      LAYER M5 ;
        RECT  76.272 56.076 76.296 56.16 ;
    END
  END cfg_data[31]
  PIN cfg_data[32]
    DIRECTION INPUT ;
    USE SIGNAL ;
    PORT
      LAYER M5 ;
        RECT  76.368 56.076 76.392 56.16 ;
    END
  END cfg_data[32]
  PIN cfg_data[33]
    DIRECTION INPUT ;
    USE SIGNAL ;
    PORT
      LAYER M5 ;
        RECT  76.464 56.076 76.488 56.16 ;
    END
  END cfg_data[33]
  PIN cfg_data[34]
    DIRECTION INPUT ;
    USE SIGNAL ;
    PORT
      LAYER M5 ;
        RECT  76.56 56.076 76.584 56.16 ;
    END
  END cfg_data[34]
  PIN cfg_data[35]
    DIRECTION INPUT ;
    USE SIGNAL ;
    PORT
      LAYER M5 ;
        RECT  76.656 56.076 76.68 56.16 ;
    END
  END cfg_data[35]
  PIN cfg_data[36]
    DIRECTION INPUT ;
    USE SIGNAL ;
    PORT
      LAYER M5 ;
        RECT  76.752 56.076 76.776 56.16 ;
    END
  END cfg_data[36]
  PIN cfg_data[37]
    DIRECTION INPUT ;
    USE SIGNAL ;
    PORT
      LAYER M5 ;
        RECT  76.848 56.076 76.872 56.16 ;
    END
  END cfg_data[37]
  PIN cfg_data[38]
    DIRECTION INPUT ;
    USE SIGNAL ;
    PORT
      LAYER M5 ;
        RECT  76.944 56.076 76.968 56.16 ;
    END
  END cfg_data[38]
  PIN cfg_data[39]
    DIRECTION INPUT ;
    USE SIGNAL ;
    PORT
      LAYER M5 ;
        RECT  77.04 56.076 77.064 56.16 ;
    END
  END cfg_data[39]
  PIN cfg_data[3]
    DIRECTION INPUT ;
    USE SIGNAL ;
    PORT
      LAYER M5 ;
        RECT  25.968 56.076 25.992 56.16 ;
    END
  END cfg_data[3]
  PIN cfg_data[40]
    DIRECTION INPUT ;
    USE SIGNAL ;
    PORT
      LAYER M5 ;
        RECT  77.136 56.076 77.16 56.16 ;
    END
  END cfg_data[40]
  PIN cfg_data[41]
    DIRECTION INPUT ;
    USE SIGNAL ;
    PORT
      LAYER M5 ;
        RECT  77.232 56.076 77.256 56.16 ;
    END
  END cfg_data[41]
  PIN cfg_data[42]
    DIRECTION INPUT ;
    USE SIGNAL ;
    PORT
      LAYER M5 ;
        RECT  77.328 56.076 77.352 56.16 ;
    END
  END cfg_data[42]
  PIN cfg_data[43]
    DIRECTION INPUT ;
    USE SIGNAL ;
    PORT
      LAYER M5 ;
        RECT  77.424 56.076 77.448 56.16 ;
    END
  END cfg_data[43]
  PIN cfg_data[44]
    DIRECTION INPUT ;
    USE SIGNAL ;
    PORT
      LAYER M5 ;
        RECT  77.52 56.076 77.544 56.16 ;
    END
  END cfg_data[44]
  PIN cfg_data[45]
    DIRECTION INPUT ;
    USE SIGNAL ;
    PORT
      LAYER M5 ;
        RECT  77.616 56.076 77.64 56.16 ;
    END
  END cfg_data[45]
  PIN cfg_data[46]
    DIRECTION INPUT ;
    USE SIGNAL ;
    PORT
      LAYER M5 ;
        RECT  77.712 56.076 77.736 56.16 ;
    END
  END cfg_data[46]
  PIN cfg_data[47]
    DIRECTION INPUT ;
    USE SIGNAL ;
    PORT
      LAYER M5 ;
        RECT  77.808 56.076 77.832 56.16 ;
    END
  END cfg_data[47]
  PIN cfg_data[48]
    DIRECTION INPUT ;
    USE SIGNAL ;
    PORT
      LAYER M5 ;
        RECT  77.904 56.076 77.928 56.16 ;
    END
  END cfg_data[48]
  PIN cfg_data[49]
    DIRECTION INPUT ;
    USE SIGNAL ;
    PORT
      LAYER M5 ;
        RECT  78 56.076 78.024 56.16 ;
    END
  END cfg_data[49]
  PIN cfg_data[4]
    DIRECTION INPUT ;
    USE SIGNAL ;
    PORT
      LAYER M5 ;
        RECT  26.064 56.076 26.088 56.16 ;
    END
  END cfg_data[4]
  PIN cfg_data[50]
    DIRECTION INPUT ;
    USE SIGNAL ;
    PORT
      LAYER M5 ;
        RECT  78.096 56.076 78.12 56.16 ;
    END
  END cfg_data[50]
  PIN cfg_data[51]
    DIRECTION INPUT ;
    USE SIGNAL ;
    PORT
      LAYER M5 ;
        RECT  78.192 56.076 78.216 56.16 ;
    END
  END cfg_data[51]
  PIN cfg_data[52]
    DIRECTION INPUT ;
    USE SIGNAL ;
    PORT
      LAYER M5 ;
        RECT  62.928 56.076 62.952 56.16 ;
    END
  END cfg_data[52]
  PIN cfg_data[53]
    DIRECTION INPUT ;
    USE SIGNAL ;
    PORT
      LAYER M5 ;
        RECT  63.024 56.076 63.048 56.16 ;
    END
  END cfg_data[53]
  PIN cfg_data[54]
    DIRECTION INPUT ;
    USE SIGNAL ;
    PORT
      LAYER M5 ;
        RECT  63.12 56.076 63.144 56.16 ;
    END
  END cfg_data[54]
  PIN cfg_data[55]
    DIRECTION INPUT ;
    USE SIGNAL ;
    PORT
      LAYER M5 ;
        RECT  63.216 56.076 63.24 56.16 ;
    END
  END cfg_data[55]
  PIN cfg_data[56]
    DIRECTION INPUT ;
    USE SIGNAL ;
    PORT
      LAYER M5 ;
        RECT  63.312 56.076 63.336 56.16 ;
    END
  END cfg_data[56]
  PIN cfg_data[57]
    DIRECTION INPUT ;
    USE SIGNAL ;
    PORT
      LAYER M5 ;
        RECT  63.408 56.076 63.432 56.16 ;
    END
  END cfg_data[57]
  PIN cfg_data[58]
    DIRECTION INPUT ;
    USE SIGNAL ;
    PORT
      LAYER M5 ;
        RECT  63.504 56.076 63.528 56.16 ;
    END
  END cfg_data[58]
  PIN cfg_data[59]
    DIRECTION INPUT ;
    USE SIGNAL ;
    PORT
      LAYER M5 ;
        RECT  63.6 56.076 63.624 56.16 ;
    END
  END cfg_data[59]
  PIN cfg_data[5]
    DIRECTION INPUT ;
    USE SIGNAL ;
    PORT
      LAYER M5 ;
        RECT  26.16 56.076 26.184 56.16 ;
    END
  END cfg_data[5]
  PIN cfg_data[60]
    DIRECTION INPUT ;
    USE SIGNAL ;
    PORT
      LAYER M5 ;
        RECT  63.696 56.076 63.72 56.16 ;
    END
  END cfg_data[60]
  PIN cfg_data[61]
    DIRECTION INPUT ;
    USE SIGNAL ;
    PORT
      LAYER M5 ;
        RECT  63.792 56.076 63.816 56.16 ;
    END
  END cfg_data[61]
  PIN cfg_data[62]
    DIRECTION INPUT ;
    USE SIGNAL ;
    PORT
      LAYER M5 ;
        RECT  63.888 56.076 63.912 56.16 ;
    END
  END cfg_data[62]
  PIN cfg_data[63]
    DIRECTION INPUT ;
    USE SIGNAL ;
    PORT
      LAYER M5 ;
        RECT  63.984 56.076 64.008 56.16 ;
    END
  END cfg_data[63]
  PIN cfg_data[64]
    DIRECTION INPUT ;
    USE SIGNAL ;
    PORT
      LAYER M5 ;
        RECT  64.08 56.076 64.104 56.16 ;
    END
  END cfg_data[64]
  PIN cfg_data[65]
    DIRECTION INPUT ;
    USE SIGNAL ;
    PORT
      LAYER M5 ;
        RECT  64.176 56.076 64.2 56.16 ;
    END
  END cfg_data[65]
  PIN cfg_data[66]
    DIRECTION INPUT ;
    USE SIGNAL ;
    PORT
      LAYER M5 ;
        RECT  64.272 56.076 64.296 56.16 ;
    END
  END cfg_data[66]
  PIN cfg_data[67]
    DIRECTION INPUT ;
    USE SIGNAL ;
    PORT
      LAYER M5 ;
        RECT  64.368 56.076 64.392 56.16 ;
    END
  END cfg_data[67]
  PIN cfg_data[68]
    DIRECTION INPUT ;
    USE SIGNAL ;
    PORT
      LAYER M5 ;
        RECT  64.464 56.076 64.488 56.16 ;
    END
  END cfg_data[68]
  PIN cfg_data[69]
    DIRECTION INPUT ;
    USE SIGNAL ;
    PORT
      LAYER M5 ;
        RECT  64.56 56.076 64.584 56.16 ;
    END
  END cfg_data[69]
  PIN cfg_data[6]
    DIRECTION INPUT ;
    USE SIGNAL ;
    PORT
      LAYER M5 ;
        RECT  26.256 56.076 26.28 56.16 ;
    END
  END cfg_data[6]
  PIN cfg_data[70]
    DIRECTION INPUT ;
    USE SIGNAL ;
    PORT
      LAYER M5 ;
        RECT  64.656 56.076 64.68 56.16 ;
    END
  END cfg_data[70]
  PIN cfg_data[71]
    DIRECTION INPUT ;
    USE SIGNAL ;
    PORT
      LAYER M5 ;
        RECT  64.752 56.076 64.776 56.16 ;
    END
  END cfg_data[71]
  PIN cfg_data[72]
    DIRECTION INPUT ;
    USE SIGNAL ;
    PORT
      LAYER M5 ;
        RECT  64.848 56.076 64.872 56.16 ;
    END
  END cfg_data[72]
  PIN cfg_data[73]
    DIRECTION INPUT ;
    USE SIGNAL ;
    PORT
      LAYER M5 ;
        RECT  64.944 56.076 64.968 56.16 ;
    END
  END cfg_data[73]
  PIN cfg_data[74]
    DIRECTION INPUT ;
    USE SIGNAL ;
    PORT
      LAYER M5 ;
        RECT  65.04 56.076 65.064 56.16 ;
    END
  END cfg_data[74]
  PIN cfg_data[75]
    DIRECTION INPUT ;
    USE SIGNAL ;
    PORT
      LAYER M5 ;
        RECT  65.136 56.076 65.16 56.16 ;
    END
  END cfg_data[75]
  PIN cfg_data[76]
    DIRECTION INPUT ;
    USE SIGNAL ;
    PORT
      LAYER M5 ;
        RECT  65.232 56.076 65.256 56.16 ;
    END
  END cfg_data[76]
  PIN cfg_data[77]
    DIRECTION INPUT ;
    USE SIGNAL ;
    PORT
      LAYER M5 ;
        RECT  65.328 56.076 65.352 56.16 ;
    END
  END cfg_data[77]
  PIN cfg_data[78]
    DIRECTION INPUT ;
    USE SIGNAL ;
    PORT
      LAYER M5 ;
        RECT  65.424 56.076 65.448 56.16 ;
    END
  END cfg_data[78]
  PIN cfg_data[79]
    DIRECTION INPUT ;
    USE SIGNAL ;
    PORT
      LAYER M5 ;
        RECT  65.52 56.076 65.544 56.16 ;
    END
  END cfg_data[79]
  PIN cfg_data[7]
    DIRECTION INPUT ;
    USE SIGNAL ;
    PORT
      LAYER M5 ;
        RECT  26.352 56.076 26.376 56.16 ;
    END
  END cfg_data[7]
  PIN cfg_data[80]
    DIRECTION INPUT ;
    USE SIGNAL ;
    PORT
      LAYER M5 ;
        RECT  65.616 56.076 65.64 56.16 ;
    END
  END cfg_data[80]
  PIN cfg_data[81]
    DIRECTION INPUT ;
    USE SIGNAL ;
    PORT
      LAYER M5 ;
        RECT  65.712 56.076 65.736 56.16 ;
    END
  END cfg_data[81]
  PIN cfg_data[82]
    DIRECTION INPUT ;
    USE SIGNAL ;
    PORT
      LAYER M5 ;
        RECT  65.808 56.076 65.832 56.16 ;
    END
  END cfg_data[82]
  PIN cfg_data[83]
    DIRECTION INPUT ;
    USE SIGNAL ;
    PORT
      LAYER M5 ;
        RECT  65.904 56.076 65.928 56.16 ;
    END
  END cfg_data[83]
  PIN cfg_data[84]
    DIRECTION INPUT ;
    USE SIGNAL ;
    PORT
      LAYER M5 ;
        RECT  43.728 56.076 43.752 56.16 ;
    END
  END cfg_data[84]
  PIN cfg_data[85]
    DIRECTION INPUT ;
    USE SIGNAL ;
    PORT
      LAYER M5 ;
        RECT  43.824 56.076 43.848 56.16 ;
    END
  END cfg_data[85]
  PIN cfg_data[86]
    DIRECTION INPUT ;
    USE SIGNAL ;
    PORT
      LAYER M5 ;
        RECT  43.92 56.076 43.944 56.16 ;
    END
  END cfg_data[86]
  PIN cfg_data[87]
    DIRECTION INPUT ;
    USE SIGNAL ;
    PORT
      LAYER M5 ;
        RECT  44.016 56.076 44.04 56.16 ;
    END
  END cfg_data[87]
  PIN cfg_data[88]
    DIRECTION INPUT ;
    USE SIGNAL ;
    PORT
      LAYER M5 ;
        RECT  44.112 56.076 44.136 56.16 ;
    END
  END cfg_data[88]
  PIN cfg_data[89]
    DIRECTION INPUT ;
    USE SIGNAL ;
    PORT
      LAYER M5 ;
        RECT  44.208 56.076 44.232 56.16 ;
    END
  END cfg_data[89]
  PIN cfg_data[8]
    DIRECTION INPUT ;
    USE SIGNAL ;
    PORT
      LAYER M5 ;
        RECT  26.448 56.076 26.472 56.16 ;
    END
  END cfg_data[8]
  PIN cfg_data[90]
    DIRECTION INPUT ;
    USE SIGNAL ;
    PORT
      LAYER M5 ;
        RECT  44.304 56.076 44.328 56.16 ;
    END
  END cfg_data[90]
  PIN cfg_data[91]
    DIRECTION INPUT ;
    USE SIGNAL ;
    PORT
      LAYER M5 ;
        RECT  44.4 56.076 44.424 56.16 ;
    END
  END cfg_data[91]
  PIN cfg_data[92]
    DIRECTION INPUT ;
    USE SIGNAL ;
    PORT
      LAYER M5 ;
        RECT  44.496 56.076 44.52 56.16 ;
    END
  END cfg_data[92]
  PIN cfg_data[93]
    DIRECTION INPUT ;
    USE SIGNAL ;
    PORT
      LAYER M5 ;
        RECT  44.592 56.076 44.616 56.16 ;
    END
  END cfg_data[93]
  PIN cfg_data[94]
    DIRECTION INPUT ;
    USE SIGNAL ;
    PORT
      LAYER M5 ;
        RECT  44.688 56.076 44.712 56.16 ;
    END
  END cfg_data[94]
  PIN cfg_data[95]
    DIRECTION INPUT ;
    USE SIGNAL ;
    PORT
      LAYER M5 ;
        RECT  44.784 56.076 44.808 56.16 ;
    END
  END cfg_data[95]
  PIN cfg_data[96]
    DIRECTION INPUT ;
    USE SIGNAL ;
    PORT
      LAYER M5 ;
        RECT  44.88 56.076 44.904 56.16 ;
    END
  END cfg_data[96]
  PIN cfg_data[97]
    DIRECTION INPUT ;
    USE SIGNAL ;
    PORT
      LAYER M5 ;
        RECT  44.976 56.076 45 56.16 ;
    END
  END cfg_data[97]
  PIN cfg_data[98]
    DIRECTION INPUT ;
    USE SIGNAL ;
    PORT
      LAYER M5 ;
        RECT  45.072 56.076 45.096 56.16 ;
    END
  END cfg_data[98]
  PIN cfg_data[99]
    DIRECTION INPUT ;
    USE SIGNAL ;
    PORT
      LAYER M5 ;
        RECT  45.168 56.076 45.192 56.16 ;
    END
  END cfg_data[99]
  PIN cfg_data[9]
    DIRECTION INPUT ;
    USE SIGNAL ;
    PORT
      LAYER M5 ;
        RECT  26.544 56.076 26.568 56.16 ;
    END
  END cfg_data[9]
  PIN cfg_target[0]
    DIRECTION INPUT ;
    USE SIGNAL ;
    PORT
      LAYER M5 ;
        RECT  6.48 56.076 6.504 56.16 ;
    END
  END cfg_target[0]
  PIN cfg_target[1]
    DIRECTION INPUT ;
    USE SIGNAL ;
    PORT
      LAYER M5 ;
        RECT  6.576 56.076 6.6 56.16 ;
    END
  END cfg_target[1]
  PIN cfg_target[2]
    DIRECTION INPUT ;
    USE SIGNAL ;
    PORT
      LAYER M5 ;
        RECT  6.672 56.076 6.696 56.16 ;
    END
  END cfg_target[2]
  PIN cfg_target[3]
    DIRECTION INPUT ;
    USE SIGNAL ;
    PORT
      LAYER M5 ;
        RECT  6.768 56.076 6.792 56.16 ;
    END
  END cfg_target[3]
  PIN cfg_target[4]
    DIRECTION INPUT ;
    USE SIGNAL ;
    PORT
      LAYER M5 ;
        RECT  6.864 56.076 6.888 56.16 ;
    END
  END cfg_target[4]
  PIN cfg_target[5]
    DIRECTION INPUT ;
    USE SIGNAL ;
    PORT
      LAYER M5 ;
        RECT  6.96 56.076 6.984 56.16 ;
    END
  END cfg_target[5]
  PIN cfg_target[6]
    DIRECTION INPUT ;
    USE SIGNAL ;
    PORT
      LAYER M5 ;
        RECT  7.056 56.076 7.08 56.16 ;
    END
  END cfg_target[6]
  PIN cfg_target[7]
    DIRECTION INPUT ;
    USE SIGNAL ;
    PORT
      LAYER M5 ;
        RECT  7.152 56.076 7.176 56.16 ;
    END
  END cfg_target[7]
  PIN cfg_v
    DIRECTION INPUT ;
    USE SIGNAL ;
    PORT
      LAYER M5 ;
        RECT  7.248 56.076 7.272 56.16 ;
    END
  END cfg_v
  PIN clk
    DIRECTION INPUT ;
    USE SIGNAL ;
    PORT
      LAYER M5 ;
        RECT  7.344 56.076 7.368 56.16 ;
    END
  END clk
  PIN configured
    DIRECTION OUTPUT ;
    USE SIGNAL ;
    PORT
      LAYER M5 ;
        RECT  7.44 56.076 7.464 56.16 ;
    END
  END configured
  PIN desc_base[0]
    DIRECTION INPUT ;
    USE SIGNAL ;
    PORT
      LAYER M5 ;
        RECT  7.536 56.076 7.56 56.16 ;
    END
  END desc_base[0]
  PIN desc_base[10]
    DIRECTION INPUT ;
    USE SIGNAL ;
    PORT
      LAYER M5 ;
        RECT  8.496 56.076 8.52 56.16 ;
    END
  END desc_base[10]
  PIN desc_base[11]
    DIRECTION INPUT ;
    USE SIGNAL ;
    PORT
      LAYER M5 ;
        RECT  8.592 56.076 8.616 56.16 ;
    END
  END desc_base[11]
  PIN desc_base[1]
    DIRECTION INPUT ;
    USE SIGNAL ;
    PORT
      LAYER M5 ;
        RECT  7.632 56.076 7.656 56.16 ;
    END
  END desc_base[1]
  PIN desc_base[2]
    DIRECTION INPUT ;
    USE SIGNAL ;
    PORT
      LAYER M5 ;
        RECT  7.728 56.076 7.752 56.16 ;
    END
  END desc_base[2]
  PIN desc_base[3]
    DIRECTION INPUT ;
    USE SIGNAL ;
    PORT
      LAYER M5 ;
        RECT  7.824 56.076 7.848 56.16 ;
    END
  END desc_base[3]
  PIN desc_base[4]
    DIRECTION INPUT ;
    USE SIGNAL ;
    PORT
      LAYER M5 ;
        RECT  7.92 56.076 7.944 56.16 ;
    END
  END desc_base[4]
  PIN desc_base[5]
    DIRECTION INPUT ;
    USE SIGNAL ;
    PORT
      LAYER M5 ;
        RECT  8.016 56.076 8.04 56.16 ;
    END
  END desc_base[5]
  PIN desc_base[6]
    DIRECTION INPUT ;
    USE SIGNAL ;
    PORT
      LAYER M5 ;
        RECT  8.112 56.076 8.136 56.16 ;
    END
  END desc_base[6]
  PIN desc_base[7]
    DIRECTION INPUT ;
    USE SIGNAL ;
    PORT
      LAYER M5 ;
        RECT  8.208 56.076 8.232 56.16 ;
    END
  END desc_base[7]
  PIN desc_base[8]
    DIRECTION INPUT ;
    USE SIGNAL ;
    PORT
      LAYER M5 ;
        RECT  8.304 56.076 8.328 56.16 ;
    END
  END desc_base[8]
  PIN desc_base[9]
    DIRECTION INPUT ;
    USE SIGNAL ;
    PORT
      LAYER M5 ;
        RECT  8.4 56.076 8.424 56.16 ;
    END
  END desc_base[9]
  PIN desc_limit[0]
    DIRECTION INPUT ;
    USE SIGNAL ;
    PORT
      LAYER M5 ;
        RECT  8.688 56.076 8.712 56.16 ;
    END
  END desc_limit[0]
  PIN desc_limit[10]
    DIRECTION INPUT ;
    USE SIGNAL ;
    PORT
      LAYER M5 ;
        RECT  9.648 56.076 9.672 56.16 ;
    END
  END desc_limit[10]
  PIN desc_limit[11]
    DIRECTION INPUT ;
    USE SIGNAL ;
    PORT
      LAYER M5 ;
        RECT  9.744 56.076 9.768 56.16 ;
    END
  END desc_limit[11]
  PIN desc_limit[12]
    DIRECTION INPUT ;
    USE SIGNAL ;
    PORT
      LAYER M5 ;
        RECT  9.84 56.076 9.864 56.16 ;
    END
  END desc_limit[12]
  PIN desc_limit[1]
    DIRECTION INPUT ;
    USE SIGNAL ;
    PORT
      LAYER M5 ;
        RECT  8.784 56.076 8.808 56.16 ;
    END
  END desc_limit[1]
  PIN desc_limit[2]
    DIRECTION INPUT ;
    USE SIGNAL ;
    PORT
      LAYER M5 ;
        RECT  8.88 56.076 8.904 56.16 ;
    END
  END desc_limit[2]
  PIN desc_limit[3]
    DIRECTION INPUT ;
    USE SIGNAL ;
    PORT
      LAYER M5 ;
        RECT  8.976 56.076 9 56.16 ;
    END
  END desc_limit[3]
  PIN desc_limit[4]
    DIRECTION INPUT ;
    USE SIGNAL ;
    PORT
      LAYER M5 ;
        RECT  9.072 56.076 9.096 56.16 ;
    END
  END desc_limit[4]
  PIN desc_limit[5]
    DIRECTION INPUT ;
    USE SIGNAL ;
    PORT
      LAYER M5 ;
        RECT  9.168 56.076 9.192 56.16 ;
    END
  END desc_limit[5]
  PIN desc_limit[6]
    DIRECTION INPUT ;
    USE SIGNAL ;
    PORT
      LAYER M5 ;
        RECT  9.264 56.076 9.288 56.16 ;
    END
  END desc_limit[6]
  PIN desc_limit[7]
    DIRECTION INPUT ;
    USE SIGNAL ;
    PORT
      LAYER M5 ;
        RECT  9.36 56.076 9.384 56.16 ;
    END
  END desc_limit[7]
  PIN desc_limit[8]
    DIRECTION INPUT ;
    USE SIGNAL ;
    PORT
      LAYER M5 ;
        RECT  9.456 56.076 9.48 56.16 ;
    END
  END desc_limit[8]
  PIN desc_limit[9]
    DIRECTION INPUT ;
    USE SIGNAL ;
    PORT
      LAYER M5 ;
        RECT  9.552 56.076 9.576 56.16 ;
    END
  END desc_limit[9]
  PIN desc_loops[0]
    DIRECTION INPUT ;
    USE SIGNAL ;
    PORT
      LAYER M5 ;
        RECT  9.936 56.076 9.96 56.16 ;
    END
  END desc_loops[0]
  PIN desc_loops[10]
    DIRECTION INPUT ;
    USE SIGNAL ;
    PORT
      LAYER M5 ;
        RECT  10.896 56.076 10.92 56.16 ;
    END
  END desc_loops[10]
  PIN desc_loops[11]
    DIRECTION INPUT ;
    USE SIGNAL ;
    PORT
      LAYER M5 ;
        RECT  10.992 56.076 11.016 56.16 ;
    END
  END desc_loops[11]
  PIN desc_loops[12]
    DIRECTION INPUT ;
    USE SIGNAL ;
    PORT
      LAYER M5 ;
        RECT  11.088 56.076 11.112 56.16 ;
    END
  END desc_loops[12]
  PIN desc_loops[13]
    DIRECTION INPUT ;
    USE SIGNAL ;
    PORT
      LAYER M5 ;
        RECT  11.184 56.076 11.208 56.16 ;
    END
  END desc_loops[13]
  PIN desc_loops[14]
    DIRECTION INPUT ;
    USE SIGNAL ;
    PORT
      LAYER M5 ;
        RECT  11.28 56.076 11.304 56.16 ;
    END
  END desc_loops[14]
  PIN desc_loops[15]
    DIRECTION INPUT ;
    USE SIGNAL ;
    PORT
      LAYER M5 ;
        RECT  11.376 56.076 11.4 56.16 ;
    END
  END desc_loops[15]
  PIN desc_loops[1]
    DIRECTION INPUT ;
    USE SIGNAL ;
    PORT
      LAYER M5 ;
        RECT  10.032 56.076 10.056 56.16 ;
    END
  END desc_loops[1]
  PIN desc_loops[2]
    DIRECTION INPUT ;
    USE SIGNAL ;
    PORT
      LAYER M5 ;
        RECT  10.128 56.076 10.152 56.16 ;
    END
  END desc_loops[2]
  PIN desc_loops[3]
    DIRECTION INPUT ;
    USE SIGNAL ;
    PORT
      LAYER M5 ;
        RECT  10.224 56.076 10.248 56.16 ;
    END
  END desc_loops[3]
  PIN desc_loops[4]
    DIRECTION INPUT ;
    USE SIGNAL ;
    PORT
      LAYER M5 ;
        RECT  10.32 56.076 10.344 56.16 ;
    END
  END desc_loops[4]
  PIN desc_loops[5]
    DIRECTION INPUT ;
    USE SIGNAL ;
    PORT
      LAYER M5 ;
        RECT  10.416 56.076 10.44 56.16 ;
    END
  END desc_loops[5]
  PIN desc_loops[6]
    DIRECTION INPUT ;
    USE SIGNAL ;
    PORT
      LAYER M5 ;
        RECT  10.512 56.076 10.536 56.16 ;
    END
  END desc_loops[6]
  PIN desc_loops[7]
    DIRECTION INPUT ;
    USE SIGNAL ;
    PORT
      LAYER M5 ;
        RECT  10.608 56.076 10.632 56.16 ;
    END
  END desc_loops[7]
  PIN desc_loops[8]
    DIRECTION INPUT ;
    USE SIGNAL ;
    PORT
      LAYER M5 ;
        RECT  10.704 56.076 10.728 56.16 ;
    END
  END desc_loops[8]
  PIN desc_loops[9]
    DIRECTION INPUT ;
    USE SIGNAL ;
    PORT
      LAYER M5 ;
        RECT  10.8 56.076 10.824 56.16 ;
    END
  END desc_loops[9]
  PIN desc_v
    DIRECTION INPUT ;
    USE SIGNAL ;
    PORT
      LAYER M5 ;
        RECT  15.312 56.076 15.336 56.16 ;
    END
  END desc_v
  PIN fault
    DIRECTION OUTPUT ;
    USE SIGNAL ;
    PORT
      LAYER M5 ;
        RECT  15.408 56.076 15.432 56.16 ;
    END
  END fault
  PIN fault_cause[0]
    DIRECTION OUTPUT ;
    USE SIGNAL ;
    PORT
      LAYER M5 ;
        RECT  15.504 56.076 15.528 56.16 ;
    END
  END fault_cause[0]
  PIN fault_cause[10]
    DIRECTION OUTPUT ;
    USE SIGNAL ;
    PORT
      LAYER M5 ;
        RECT  16.464 56.076 16.488 56.16 ;
    END
  END fault_cause[10]
  PIN fault_cause[11]
    DIRECTION OUTPUT ;
    USE SIGNAL ;
    PORT
      LAYER M5 ;
        RECT  16.56 56.076 16.584 56.16 ;
    END
  END fault_cause[11]
  PIN fault_cause[12]
    DIRECTION OUTPUT ;
    USE SIGNAL ;
    PORT
      LAYER M5 ;
        RECT  16.656 56.076 16.68 56.16 ;
    END
  END fault_cause[12]
  PIN fault_cause[13]
    DIRECTION OUTPUT ;
    USE SIGNAL ;
    PORT
      LAYER M5 ;
        RECT  16.752 56.076 16.776 56.16 ;
    END
  END fault_cause[13]
  PIN fault_cause[14]
    DIRECTION OUTPUT ;
    USE SIGNAL ;
    PORT
      LAYER M5 ;
        RECT  16.848 56.076 16.872 56.16 ;
    END
  END fault_cause[14]
  PIN fault_cause[15]
    DIRECTION OUTPUT ;
    USE SIGNAL ;
    PORT
      LAYER M5 ;
        RECT  16.944 56.076 16.968 56.16 ;
    END
  END fault_cause[15]
  PIN fault_cause[1]
    DIRECTION OUTPUT ;
    USE SIGNAL ;
    PORT
      LAYER M5 ;
        RECT  15.6 56.076 15.624 56.16 ;
    END
  END fault_cause[1]
  PIN fault_cause[2]
    DIRECTION OUTPUT ;
    USE SIGNAL ;
    PORT
      LAYER M5 ;
        RECT  15.696 56.076 15.72 56.16 ;
    END
  END fault_cause[2]
  PIN fault_cause[3]
    DIRECTION OUTPUT ;
    USE SIGNAL ;
    PORT
      LAYER M5 ;
        RECT  15.792 56.076 15.816 56.16 ;
    END
  END fault_cause[3]
  PIN fault_cause[4]
    DIRECTION OUTPUT ;
    USE SIGNAL ;
    PORT
      LAYER M5 ;
        RECT  15.888 56.076 15.912 56.16 ;
    END
  END fault_cause[4]
  PIN fault_cause[5]
    DIRECTION OUTPUT ;
    USE SIGNAL ;
    PORT
      LAYER M5 ;
        RECT  15.984 56.076 16.008 56.16 ;
    END
  END fault_cause[5]
  PIN fault_cause[6]
    DIRECTION OUTPUT ;
    USE SIGNAL ;
    PORT
      LAYER M5 ;
        RECT  16.08 56.076 16.104 56.16 ;
    END
  END fault_cause[6]
  PIN fault_cause[7]
    DIRECTION OUTPUT ;
    USE SIGNAL ;
    PORT
      LAYER M5 ;
        RECT  16.176 56.076 16.2 56.16 ;
    END
  END fault_cause[7]
  PIN fault_cause[8]
    DIRECTION OUTPUT ;
    USE SIGNAL ;
    PORT
      LAYER M5 ;
        RECT  16.272 56.076 16.296 56.16 ;
    END
  END fault_cause[8]
  PIN fault_cause[9]
    DIRECTION OUTPUT ;
    USE SIGNAL ;
    PORT
      LAYER M5 ;
        RECT  16.368 56.076 16.392 56.16 ;
    END
  END fault_cause[9]
  PIN init_busy
    DIRECTION OUTPUT ;
    USE SIGNAL ;
    PORT
      LAYER M5 ;
        RECT  17.04 56.076 17.064 56.16 ;
    END
  END init_busy
  PIN issuer_busy
    DIRECTION INPUT ;
    USE SIGNAL ;
    PORT
      LAYER M5 ;
        RECT  45.264 0 45.288 0.084 ;
    END
  END issuer_busy
  PIN issuer_cfg[0]
    DIRECTION OUTPUT ;
    USE SIGNAL ;
    PORT
      LAYER M5 ;
        RECT  45.36 0 45.384 0.084 ;
    END
  END issuer_cfg[0]
  PIN issuer_cfg[10]
    DIRECTION OUTPUT ;
    USE SIGNAL ;
    PORT
      LAYER M5 ;
        RECT  46.32 0 46.344 0.084 ;
    END
  END issuer_cfg[10]
  PIN issuer_cfg[11]
    DIRECTION OUTPUT ;
    USE SIGNAL ;
    PORT
      LAYER M5 ;
        RECT  46.416 0 46.44 0.084 ;
    END
  END issuer_cfg[11]
  PIN issuer_cfg[12]
    DIRECTION OUTPUT ;
    USE SIGNAL ;
    PORT
      LAYER M5 ;
        RECT  46.512 0 46.536 0.084 ;
    END
  END issuer_cfg[12]
  PIN issuer_cfg[13]
    DIRECTION OUTPUT ;
    USE SIGNAL ;
    PORT
      LAYER M5 ;
        RECT  46.608 0 46.632 0.084 ;
    END
  END issuer_cfg[13]
  PIN issuer_cfg[14]
    DIRECTION OUTPUT ;
    USE SIGNAL ;
    PORT
      LAYER M5 ;
        RECT  46.704 0 46.728 0.084 ;
    END
  END issuer_cfg[14]
  PIN issuer_cfg[15]
    DIRECTION OUTPUT ;
    USE SIGNAL ;
    PORT
      LAYER M5 ;
        RECT  46.8 0 46.824 0.084 ;
    END
  END issuer_cfg[15]
  PIN issuer_cfg[16]
    DIRECTION OUTPUT ;
    USE SIGNAL ;
    PORT
      LAYER M5 ;
        RECT  46.896 0 46.92 0.084 ;
    END
  END issuer_cfg[16]
  PIN issuer_cfg[17]
    DIRECTION OUTPUT ;
    USE SIGNAL ;
    PORT
      LAYER M5 ;
        RECT  46.992 0 47.016 0.084 ;
    END
  END issuer_cfg[17]
  PIN issuer_cfg[18]
    DIRECTION OUTPUT ;
    USE SIGNAL ;
    PORT
      LAYER M5 ;
        RECT  47.088 0 47.112 0.084 ;
    END
  END issuer_cfg[18]
  PIN issuer_cfg[19]
    DIRECTION OUTPUT ;
    USE SIGNAL ;
    PORT
      LAYER M5 ;
        RECT  47.184 0 47.208 0.084 ;
    END
  END issuer_cfg[19]
  PIN issuer_cfg[1]
    DIRECTION OUTPUT ;
    USE SIGNAL ;
    PORT
      LAYER M5 ;
        RECT  45.456 0 45.48 0.084 ;
    END
  END issuer_cfg[1]
  PIN issuer_cfg[20]
    DIRECTION OUTPUT ;
    USE SIGNAL ;
    PORT
      LAYER M5 ;
        RECT  47.28 0 47.304 0.084 ;
    END
  END issuer_cfg[20]
  PIN issuer_cfg[21]
    DIRECTION OUTPUT ;
    USE SIGNAL ;
    PORT
      LAYER M5 ;
        RECT  47.376 0 47.4 0.084 ;
    END
  END issuer_cfg[21]
  PIN issuer_cfg[22]
    DIRECTION OUTPUT ;
    USE SIGNAL ;
    PORT
      LAYER M5 ;
        RECT  47.472 0 47.496 0.084 ;
    END
  END issuer_cfg[22]
  PIN issuer_cfg[23]
    DIRECTION OUTPUT ;
    USE SIGNAL ;
    PORT
      LAYER M5 ;
        RECT  47.568 0 47.592 0.084 ;
    END
  END issuer_cfg[23]
  PIN issuer_cfg[24]
    DIRECTION OUTPUT ;
    USE SIGNAL ;
    PORT
      LAYER M5 ;
        RECT  47.664 0 47.688 0.084 ;
    END
  END issuer_cfg[24]
  PIN issuer_cfg[25]
    DIRECTION OUTPUT ;
    USE SIGNAL ;
    PORT
      LAYER M5 ;
        RECT  47.76 0 47.784 0.084 ;
    END
  END issuer_cfg[25]
  PIN issuer_cfg[26]
    DIRECTION OUTPUT ;
    USE SIGNAL ;
    PORT
      LAYER M5 ;
        RECT  47.856 0 47.88 0.084 ;
    END
  END issuer_cfg[26]
  PIN issuer_cfg[27]
    DIRECTION OUTPUT ;
    USE SIGNAL ;
    PORT
      LAYER M5 ;
        RECT  47.952 0 47.976 0.084 ;
    END
  END issuer_cfg[27]
  PIN issuer_cfg[28]
    DIRECTION OUTPUT ;
    USE SIGNAL ;
    PORT
      LAYER M5 ;
        RECT  48.048 0 48.072 0.084 ;
    END
  END issuer_cfg[28]
  PIN issuer_cfg[29]
    DIRECTION OUTPUT ;
    USE SIGNAL ;
    PORT
      LAYER M5 ;
        RECT  48.144 0 48.168 0.084 ;
    END
  END issuer_cfg[29]
  PIN issuer_cfg[2]
    DIRECTION OUTPUT ;
    USE SIGNAL ;
    PORT
      LAYER M5 ;
        RECT  45.552 0 45.576 0.084 ;
    END
  END issuer_cfg[2]
  PIN issuer_cfg[30]
    DIRECTION OUTPUT ;
    USE SIGNAL ;
    PORT
      LAYER M5 ;
        RECT  48.24 0 48.264 0.084 ;
    END
  END issuer_cfg[30]
  PIN issuer_cfg[31]
    DIRECTION OUTPUT ;
    USE SIGNAL ;
    PORT
      LAYER M5 ;
        RECT  4.944 0 4.968 0.084 ;
    END
  END issuer_cfg[31]
  PIN issuer_cfg[32]
    DIRECTION OUTPUT ;
    USE SIGNAL ;
    PORT
      LAYER M5 ;
        RECT  5.04 0 5.064 0.084 ;
    END
  END issuer_cfg[32]
  PIN issuer_cfg[33]
    DIRECTION OUTPUT ;
    USE SIGNAL ;
    PORT
      LAYER M5 ;
        RECT  5.136 0 5.16 0.084 ;
    END
  END issuer_cfg[33]
  PIN issuer_cfg[34]
    DIRECTION OUTPUT ;
    USE SIGNAL ;
    PORT
      LAYER M5 ;
        RECT  5.232 0 5.256 0.084 ;
    END
  END issuer_cfg[34]
  PIN issuer_cfg[35]
    DIRECTION OUTPUT ;
    USE SIGNAL ;
    PORT
      LAYER M5 ;
        RECT  5.328 0 5.352 0.084 ;
    END
  END issuer_cfg[35]
  PIN issuer_cfg[36]
    DIRECTION OUTPUT ;
    USE SIGNAL ;
    PORT
      LAYER M5 ;
        RECT  5.424 0 5.448 0.084 ;
    END
  END issuer_cfg[36]
  PIN issuer_cfg[3]
    DIRECTION OUTPUT ;
    USE SIGNAL ;
    PORT
      LAYER M5 ;
        RECT  45.648 0 45.672 0.084 ;
    END
  END issuer_cfg[3]
  PIN issuer_cfg[4]
    DIRECTION OUTPUT ;
    USE SIGNAL ;
    PORT
      LAYER M5 ;
        RECT  45.744 0 45.768 0.084 ;
    END
  END issuer_cfg[4]
  PIN issuer_cfg[5]
    DIRECTION OUTPUT ;
    USE SIGNAL ;
    PORT
      LAYER M5 ;
        RECT  45.84 0 45.864 0.084 ;
    END
  END issuer_cfg[5]
  PIN issuer_cfg[6]
    DIRECTION OUTPUT ;
    USE SIGNAL ;
    PORT
      LAYER M5 ;
        RECT  45.936 0 45.96 0.084 ;
    END
  END issuer_cfg[6]
  PIN issuer_cfg[7]
    DIRECTION OUTPUT ;
    USE SIGNAL ;
    PORT
      LAYER M5 ;
        RECT  46.032 0 46.056 0.084 ;
    END
  END issuer_cfg[7]
  PIN issuer_cfg[8]
    DIRECTION OUTPUT ;
    USE SIGNAL ;
    PORT
      LAYER M5 ;
        RECT  46.128 0 46.152 0.084 ;
    END
  END issuer_cfg[8]
  PIN issuer_cfg[9]
    DIRECTION OUTPUT ;
    USE SIGNAL ;
    PORT
      LAYER M5 ;
        RECT  46.224 0 46.248 0.084 ;
    END
  END issuer_cfg[9]
  PIN issuer_fault
    DIRECTION INPUT ;
    USE SIGNAL ;
    PORT
      LAYER M5 ;
        RECT  5.52 0 5.544 0.084 ;
    END
  END issuer_fault
  PIN issuer_start
    DIRECTION OUTPUT ;
    USE SIGNAL ;
    PORT
      LAYER M5 ;
        RECT  5.616 0 5.64 0.084 ;
    END
  END issuer_start
  PIN issuer_start_pc[0]
    DIRECTION OUTPUT ;
    USE SIGNAL ;
    PORT
      LAYER M5 ;
        RECT  5.712 0 5.736 0.084 ;
    END
  END issuer_start_pc[0]
  PIN issuer_start_pc[1]
    DIRECTION OUTPUT ;
    USE SIGNAL ;
    PORT
      LAYER M5 ;
        RECT  5.808 0 5.832 0.084 ;
    END
  END issuer_start_pc[1]
  PIN issuer_start_pc[2]
    DIRECTION OUTPUT ;
    USE SIGNAL ;
    PORT
      LAYER M5 ;
        RECT  5.904 0 5.928 0.084 ;
    END
  END issuer_start_pc[2]
  PIN issuer_start_pc[3]
    DIRECTION OUTPUT ;
    USE SIGNAL ;
    PORT
      LAYER M5 ;
        RECT  6 0 6.024 0.084 ;
    END
  END issuer_start_pc[3]
  PIN issuer_start_pc[4]
    DIRECTION OUTPUT ;
    USE SIGNAL ;
    PORT
      LAYER M5 ;
        RECT  6.096 0 6.12 0.084 ;
    END
  END issuer_start_pc[4]
  PIN issuer_start_pc[5]
    DIRECTION OUTPUT ;
    USE SIGNAL ;
    PORT
      LAYER M5 ;
        RECT  6.192 0 6.216 0.084 ;
    END
  END issuer_start_pc[5]
  PIN issuer_uop_pc[0]
    DIRECTION INPUT ;
    USE SIGNAL ;
    PORT
      LAYER M5 ;
        RECT  6.288 0 6.312 0.084 ;
    END
  END issuer_uop_pc[0]
  PIN issuer_uop_pc[1]
    DIRECTION INPUT ;
    USE SIGNAL ;
    PORT
      LAYER M5 ;
        RECT  6.384 0 6.408 0.084 ;
    END
  END issuer_uop_pc[1]
  PIN issuer_uop_pc[2]
    DIRECTION INPUT ;
    USE SIGNAL ;
    PORT
      LAYER M5 ;
        RECT  6.48 0 6.504 0.084 ;
    END
  END issuer_uop_pc[2]
  PIN issuer_uop_pc[3]
    DIRECTION INPUT ;
    USE SIGNAL ;
    PORT
      LAYER M5 ;
        RECT  6.576 0 6.6 0.084 ;
    END
  END issuer_uop_pc[3]
  PIN issuer_uop_pc[4]
    DIRECTION INPUT ;
    USE SIGNAL ;
    PORT
      LAYER M5 ;
        RECT  6.672 0 6.696 0.084 ;
    END
  END issuer_uop_pc[4]
  PIN issuer_uop_pc[5]
    DIRECTION INPUT ;
    USE SIGNAL ;
    PORT
      LAYER M5 ;
        RECT  6.768 0 6.792 0.084 ;
    END
  END issuer_uop_pc[5]
  PIN issuer_uop_v
    DIRECTION INPUT ;
    USE SIGNAL ;
    PORT
      LAYER M5 ;
        RECT  6.864 0 6.888 0.084 ;
    END
  END issuer_uop_v
  PIN launch_v
    DIRECTION INPUT ;
    USE SIGNAL ;
    PORT
      LAYER M5 ;
        RECT  17.136 56.076 17.16 56.16 ;
    END
  END launch_v
  PIN link_abort[0]
    DIRECTION INPUT ;
    USE SIGNAL ;
    PORT
      LAYER M4 ;
        RECT  0 29.52 0.084 29.544 ;
    END
  END link_abort[0]
  PIN link_abort[1]
    DIRECTION INPUT ;
    USE SIGNAL ;
    PORT
      LAYER M4 ;
        RECT  0 29.616 0.084 29.64 ;
    END
  END link_abort[1]
  PIN program_active
    DIRECTION INPUT ;
    USE SIGNAL ;
    PORT
      LAYER M5 ;
        RECT  6.96 0 6.984 0.084 ;
    END
  END program_active
  PIN program_fault
    DIRECTION OUTPUT ;
    USE SIGNAL ;
    PORT
      LAYER M5 ;
        RECT  17.232 56.076 17.256 56.16 ;
    END
  END program_fault
  PIN protocol_fault
    DIRECTION INPUT ;
    USE SIGNAL ;
    PORT
      LAYER M4 ;
        RECT  81.996 7.824 82.08 7.848 ;
    END
  END protocol_fault
  PIN qid[0]
    DIRECTION INPUT ;
    USE SIGNAL ;
    PORT
      LAYER M5 ;
        RECT  17.328 56.076 17.352 56.16 ;
    END
  END qid[0]
  PIN qid[1]
    DIRECTION INPUT ;
    USE SIGNAL ;
    PORT
      LAYER M5 ;
        RECT  17.424 56.076 17.448 56.16 ;
    END
  END qid[1]
  PIN reduce_fault
    DIRECTION INPUT ;
    USE SIGNAL ;
    PORT
      LAYER M4 ;
        RECT  0 29.712 0.084 29.736 ;
    END
  END reduce_fault
  PIN ring_fault
    DIRECTION INPUT ;
    USE SIGNAL ;
    PORT
      LAYER M4 ;
        RECT  0 29.808 0.084 29.832 ;
    END
  END ring_fault
  PIN rst_n
    DIRECTION INPUT ;
    USE SIGNAL ;
    PORT
      LAYER M5 ;
        RECT  17.52 56.076 17.544 56.16 ;
    END
  END rst_n
  PIN select_fault[0]
    DIRECTION INPUT ;
    USE SIGNAL ;
    PORT
      LAYER M4 ;
        RECT  81.996 7.92 82.08 7.944 ;
    END
  END select_fault[0]
  PIN select_fault[10]
    DIRECTION INPUT ;
    USE SIGNAL ;
    PORT
      LAYER M4 ;
        RECT  81.996 8.88 82.08 8.904 ;
    END
  END select_fault[10]
  PIN select_fault[11]
    DIRECTION INPUT ;
    USE SIGNAL ;
    PORT
      LAYER M4 ;
        RECT  81.996 8.976 82.08 9 ;
    END
  END select_fault[11]
  PIN select_fault[12]
    DIRECTION INPUT ;
    USE SIGNAL ;
    PORT
      LAYER M4 ;
        RECT  81.996 9.072 82.08 9.096 ;
    END
  END select_fault[12]
  PIN select_fault[13]
    DIRECTION INPUT ;
    USE SIGNAL ;
    PORT
      LAYER M4 ;
        RECT  81.996 9.168 82.08 9.192 ;
    END
  END select_fault[13]
  PIN select_fault[14]
    DIRECTION INPUT ;
    USE SIGNAL ;
    PORT
      LAYER M4 ;
        RECT  81.996 9.264 82.08 9.288 ;
    END
  END select_fault[14]
  PIN select_fault[15]
    DIRECTION INPUT ;
    USE SIGNAL ;
    PORT
      LAYER M4 ;
        RECT  81.996 9.36 82.08 9.384 ;
    END
  END select_fault[15]
  PIN select_fault[16]
    DIRECTION INPUT ;
    USE SIGNAL ;
    PORT
      LAYER M4 ;
        RECT  81.996 9.456 82.08 9.48 ;
    END
  END select_fault[16]
  PIN select_fault[17]
    DIRECTION INPUT ;
    USE SIGNAL ;
    PORT
      LAYER M4 ;
        RECT  81.996 9.552 82.08 9.576 ;
    END
  END select_fault[17]
  PIN select_fault[1]
    DIRECTION INPUT ;
    USE SIGNAL ;
    PORT
      LAYER M4 ;
        RECT  81.996 8.016 82.08 8.04 ;
    END
  END select_fault[1]
  PIN select_fault[2]
    DIRECTION INPUT ;
    USE SIGNAL ;
    PORT
      LAYER M4 ;
        RECT  81.996 8.112 82.08 8.136 ;
    END
  END select_fault[2]
  PIN select_fault[3]
    DIRECTION INPUT ;
    USE SIGNAL ;
    PORT
      LAYER M4 ;
        RECT  81.996 8.208 82.08 8.232 ;
    END
  END select_fault[3]
  PIN select_fault[4]
    DIRECTION INPUT ;
    USE SIGNAL ;
    PORT
      LAYER M4 ;
        RECT  81.996 8.304 82.08 8.328 ;
    END
  END select_fault[4]
  PIN select_fault[5]
    DIRECTION INPUT ;
    USE SIGNAL ;
    PORT
      LAYER M4 ;
        RECT  81.996 8.4 82.08 8.424 ;
    END
  END select_fault[5]
  PIN select_fault[6]
    DIRECTION INPUT ;
    USE SIGNAL ;
    PORT
      LAYER M4 ;
        RECT  81.996 8.496 82.08 8.52 ;
    END
  END select_fault[6]
  PIN select_fault[7]
    DIRECTION INPUT ;
    USE SIGNAL ;
    PORT
      LAYER M4 ;
        RECT  81.996 8.592 82.08 8.616 ;
    END
  END select_fault[7]
  PIN select_fault[8]
    DIRECTION INPUT ;
    USE SIGNAL ;
    PORT
      LAYER M4 ;
        RECT  81.996 8.688 82.08 8.712 ;
    END
  END select_fault[8]
  PIN select_fault[9]
    DIRECTION INPUT ;
    USE SIGNAL ;
    PORT
      LAYER M4 ;
        RECT  81.996 8.784 82.08 8.808 ;
    END
  END select_fault[9]
  PIN tkm_del_slot[0]
    DIRECTION INPUT ;
    USE SIGNAL ;
    PORT
      LAYER M4 ;
        RECT  81.996 9.648 82.08 9.672 ;
    END
  END tkm_del_slot[0]
  PIN tkm_del_slot[1]
    DIRECTION INPUT ;
    USE SIGNAL ;
    PORT
      LAYER M4 ;
        RECT  81.996 9.744 82.08 9.768 ;
    END
  END tkm_del_slot[1]
  PIN tkm_del_slot[2]
    DIRECTION INPUT ;
    USE SIGNAL ;
    PORT
      LAYER M4 ;
        RECT  81.996 9.84 82.08 9.864 ;
    END
  END tkm_del_slot[2]
  PIN tkm_del_slot[3]
    DIRECTION INPUT ;
    USE SIGNAL ;
    PORT
      LAYER M4 ;
        RECT  81.996 31.44 82.08 31.464 ;
    END
  END tkm_del_slot[3]
  PIN tkm_dest_v[0]
    DIRECTION INPUT ;
    USE SIGNAL ;
    PORT
      LAYER M4 ;
        RECT  81.996 31.536 82.08 31.56 ;
    END
  END tkm_dest_v[0]
  PIN tkm_dest_v[1]
    DIRECTION INPUT ;
    USE SIGNAL ;
    PORT
      LAYER M4 ;
        RECT  81.996 31.632 82.08 31.656 ;
    END
  END tkm_dest_v[1]
  PIN tkm_dest_v[2]
    DIRECTION INPUT ;
    USE SIGNAL ;
    PORT
      LAYER M4 ;
        RECT  81.996 31.728 82.08 31.752 ;
    END
  END tkm_dest_v[2]
  PIN tkm_dest_v[3]
    DIRECTION INPUT ;
    USE SIGNAL ;
    PORT
      LAYER M4 ;
        RECT  81.996 31.824 82.08 31.848 ;
    END
  END tkm_dest_v[3]
  PIN tkm_start
    DIRECTION INPUT ;
    USE SIGNAL ;
    PORT
      LAYER M4 ;
        RECT  81.996 31.92 82.08 31.944 ;
    END
  END tkm_start
  PIN unavailable_fault[0]
    DIRECTION INPUT ;
    USE SIGNAL ;
    PORT
      LAYER M4 ;
        RECT  81.996 32.016 82.08 32.04 ;
    END
  END unavailable_fault[0]
  PIN unavailable_fault[10]
    DIRECTION INPUT ;
    USE SIGNAL ;
    PORT
      LAYER M4 ;
        RECT  81.996 32.976 82.08 33 ;
    END
  END unavailable_fault[10]
  PIN unavailable_fault[11]
    DIRECTION INPUT ;
    USE SIGNAL ;
    PORT
      LAYER M4 ;
        RECT  81.996 33.072 82.08 33.096 ;
    END
  END unavailable_fault[11]
  PIN unavailable_fault[12]
    DIRECTION INPUT ;
    USE SIGNAL ;
    PORT
      LAYER M4 ;
        RECT  81.996 33.168 82.08 33.192 ;
    END
  END unavailable_fault[12]
  PIN unavailable_fault[13]
    DIRECTION INPUT ;
    USE SIGNAL ;
    PORT
      LAYER M4 ;
        RECT  81.996 33.264 82.08 33.288 ;
    END
  END unavailable_fault[13]
  PIN unavailable_fault[14]
    DIRECTION INPUT ;
    USE SIGNAL ;
    PORT
      LAYER M4 ;
        RECT  81.996 33.36 82.08 33.384 ;
    END
  END unavailable_fault[14]
  PIN unavailable_fault[15]
    DIRECTION INPUT ;
    USE SIGNAL ;
    PORT
      LAYER M4 ;
        RECT  81.996 33.456 82.08 33.48 ;
    END
  END unavailable_fault[15]
  PIN unavailable_fault[16]
    DIRECTION INPUT ;
    USE SIGNAL ;
    PORT
      LAYER M4 ;
        RECT  81.996 33.552 82.08 33.576 ;
    END
  END unavailable_fault[16]
  PIN unavailable_fault[17]
    DIRECTION INPUT ;
    USE SIGNAL ;
    PORT
      LAYER M4 ;
        RECT  81.996 33.648 82.08 33.672 ;
    END
  END unavailable_fault[17]
  PIN unavailable_fault[1]
    DIRECTION INPUT ;
    USE SIGNAL ;
    PORT
      LAYER M4 ;
        RECT  81.996 32.112 82.08 32.136 ;
    END
  END unavailable_fault[1]
  PIN unavailable_fault[2]
    DIRECTION INPUT ;
    USE SIGNAL ;
    PORT
      LAYER M4 ;
        RECT  81.996 32.208 82.08 32.232 ;
    END
  END unavailable_fault[2]
  PIN unavailable_fault[3]
    DIRECTION INPUT ;
    USE SIGNAL ;
    PORT
      LAYER M4 ;
        RECT  81.996 32.304 82.08 32.328 ;
    END
  END unavailable_fault[3]
  PIN unavailable_fault[4]
    DIRECTION INPUT ;
    USE SIGNAL ;
    PORT
      LAYER M4 ;
        RECT  81.996 32.4 82.08 32.424 ;
    END
  END unavailable_fault[4]
  PIN unavailable_fault[5]
    DIRECTION INPUT ;
    USE SIGNAL ;
    PORT
      LAYER M4 ;
        RECT  81.996 32.496 82.08 32.52 ;
    END
  END unavailable_fault[5]
  PIN unavailable_fault[6]
    DIRECTION INPUT ;
    USE SIGNAL ;
    PORT
      LAYER M4 ;
        RECT  81.996 32.592 82.08 32.616 ;
    END
  END unavailable_fault[6]
  PIN unavailable_fault[7]
    DIRECTION INPUT ;
    USE SIGNAL ;
    PORT
      LAYER M4 ;
        RECT  81.996 32.688 82.08 32.712 ;
    END
  END unavailable_fault[7]
  PIN unavailable_fault[8]
    DIRECTION INPUT ;
    USE SIGNAL ;
    PORT
      LAYER M4 ;
        RECT  81.996 32.784 82.08 32.808 ;
    END
  END unavailable_fault[8]
  PIN unavailable_fault[9]
    DIRECTION INPUT ;
    USE SIGNAL ;
    PORT
      LAYER M4 ;
        RECT  81.996 32.88 82.08 32.904 ;
    END
  END unavailable_fault[9]
  PIN writer_fault
    DIRECTION INPUT ;
    USE SIGNAL ;
    PORT
      LAYER M4 ;
        RECT  0 29.904 0.084 29.928 ;
    END
  END writer_fault
  PIN VDD
    DIRECTION INOUT ;
    USE POWER ;
    PORT
      LAYER M5 ;
        RECT  78.192 2.151 78.312 54.009 ;
        RECT  72.792 2.151 72.912 54.009 ;
        RECT  67.392 2.151 67.512 54.009 ;
        RECT  61.992 2.151 62.112 54.009 ;
        RECT  56.592 2.151 56.712 54.009 ;
        RECT  51.192 2.151 51.312 54.009 ;
        RECT  45.792 2.151 45.912 54.009 ;
        RECT  40.392 2.151 40.512 54.009 ;
        RECT  34.992 2.151 35.112 54.009 ;
        RECT  29.592 2.151 29.712 54.009 ;
        RECT  24.192 2.151 24.312 54.009 ;
        RECT  18.792 2.151 18.912 54.009 ;
        RECT  13.392 2.151 13.512 54.009 ;
        RECT  7.992 2.151 8.112 54.009 ;
        RECT  2.592 2.151 2.712 54.009 ;
    END
  END VDD
  PIN VSS
    DIRECTION INOUT ;
    USE GROUND ;
    PORT
      LAYER M5 ;
        RECT  78 2.137 78.12 54.023 ;
        RECT  72.6 2.137 72.72 54.023 ;
        RECT  67.2 2.137 67.32 54.023 ;
        RECT  61.8 2.137 61.92 54.023 ;
        RECT  56.4 2.137 56.52 54.023 ;
        RECT  51 2.137 51.12 54.023 ;
        RECT  45.6 2.137 45.72 54.023 ;
        RECT  40.2 2.137 40.32 54.023 ;
        RECT  34.8 2.137 34.92 54.023 ;
        RECT  29.4 2.137 29.52 54.023 ;
        RECT  24 2.137 24.12 54.023 ;
        RECT  18.6 2.137 18.72 54.023 ;
        RECT  13.2 2.137 13.32 54.023 ;
        RECT  7.8 2.137 7.92 54.023 ;
        RECT  2.4 2.137 2.52 54.023 ;
    END
  END VSS
  OBS
    LAYER RVTN ;
     RECT  2.16 2.16 79.92 2.295 ;
     RECT  2.16 2.565 79.92 2.835 ;
     RECT  2.16 3.105 79.92 3.375 ;
     RECT  2.16 3.645 79.92 3.915 ;
     RECT  2.16 4.185 79.92 4.455 ;
     RECT  2.16 4.725 79.92 4.995 ;
     RECT  2.16 5.265 79.92 5.535 ;
     RECT  2.16 5.805 79.92 6.075 ;
     RECT  2.16 6.345 79.92 6.615 ;
     RECT  2.16 6.885 79.92 7.155 ;
     RECT  2.16 7.425 79.92 7.695 ;
     RECT  2.16 7.965 79.92 8.235 ;
     RECT  2.16 8.505 79.92 8.775 ;
     RECT  2.16 9.045 79.92 9.315 ;
     RECT  2.16 9.585 79.92 9.855 ;
     RECT  2.16 10.125 79.92 10.395 ;
     RECT  2.16 10.665 79.92 10.935 ;
     RECT  2.16 11.205 79.92 11.475 ;
     RECT  2.16 11.745 79.92 12.015 ;
     RECT  2.16 12.285 79.92 12.555 ;
     RECT  2.16 12.825 79.92 13.095 ;
     RECT  2.16 13.365 79.92 13.635 ;
     RECT  2.16 13.905 79.92 14.175 ;
     RECT  2.16 14.445 79.92 14.715 ;
     RECT  2.16 14.985 79.92 15.255 ;
     RECT  2.16 15.525 79.92 15.795 ;
     RECT  2.16 16.065 79.92 16.335 ;
     RECT  2.16 16.605 79.92 16.875 ;
     RECT  2.16 17.145 79.92 17.415 ;
     RECT  2.16 17.685 79.92 17.955 ;
     RECT  2.16 18.225 79.92 18.495 ;
     RECT  2.16 18.765 79.92 19.035 ;
     RECT  2.16 19.305 79.92 19.575 ;
     RECT  2.16 19.845 79.92 20.115 ;
     RECT  2.16 20.385 79.92 20.655 ;
     RECT  2.16 20.925 79.92 21.195 ;
     RECT  2.16 21.465 79.92 21.735 ;
     RECT  2.16 22.005 79.92 22.275 ;
     RECT  2.16 22.545 79.92 22.815 ;
     RECT  2.16 23.085 79.92 23.355 ;
     RECT  2.16 23.625 79.92 23.895 ;
     RECT  2.16 24.165 79.92 24.435 ;
     RECT  2.16 24.705 79.92 24.975 ;
     RECT  2.16 25.245 79.92 25.515 ;
     RECT  2.16 25.785 79.92 26.055 ;
     RECT  2.16 26.325 79.92 26.595 ;
     RECT  2.16 26.865 79.92 27.135 ;
     RECT  2.16 27.405 79.92 27.675 ;
     RECT  2.16 27.945 79.92 28.215 ;
     RECT  2.16 28.485 79.92 28.755 ;
     RECT  2.16 29.025 79.92 29.295 ;
     RECT  2.16 29.565 79.92 29.835 ;
     RECT  2.16 30.105 79.92 30.375 ;
     RECT  2.16 30.645 79.92 30.915 ;
     RECT  2.16 31.185 79.92 31.455 ;
     RECT  2.16 31.725 79.92 31.995 ;
     RECT  2.16 32.265 79.92 32.535 ;
     RECT  2.16 32.805 79.92 33.075 ;
     RECT  2.16 33.345 79.92 33.615 ;
     RECT  2.16 33.885 79.92 34.155 ;
     RECT  2.16 34.425 79.92 34.695 ;
     RECT  2.16 34.965 79.92 35.235 ;
     RECT  2.16 35.505 79.92 35.775 ;
     RECT  2.16 36.045 79.92 36.315 ;
     RECT  2.16 36.585 79.92 36.855 ;
     RECT  2.16 37.125 79.92 37.395 ;
     RECT  2.16 37.665 79.92 37.935 ;
     RECT  2.16 38.205 79.92 38.475 ;
     RECT  2.16 38.745 79.92 39.015 ;
     RECT  2.16 39.285 79.92 39.555 ;
     RECT  2.16 39.825 79.92 40.095 ;
     RECT  2.16 40.365 79.92 40.635 ;
     RECT  2.16 40.905 79.92 41.175 ;
     RECT  2.16 41.445 79.92 41.715 ;
     RECT  2.16 41.985 79.92 42.255 ;
     RECT  2.16 42.525 79.92 42.795 ;
     RECT  2.16 43.065 79.92 43.335 ;
     RECT  2.16 43.605 79.92 43.875 ;
     RECT  2.16 44.145 79.92 44.415 ;
     RECT  2.16 44.685 79.92 44.955 ;
     RECT  2.16 45.225 79.92 45.495 ;
     RECT  2.16 45.765 79.92 46.035 ;
     RECT  2.16 46.305 79.92 46.575 ;
     RECT  2.16 46.845 79.92 47.115 ;
     RECT  2.16 47.385 79.92 47.655 ;
     RECT  2.16 47.925 79.92 48.195 ;
     RECT  2.16 48.465 79.92 48.735 ;
     RECT  2.16 49.005 79.92 49.275 ;
     RECT  2.16 49.545 79.92 49.815 ;
     RECT  2.16 50.085 79.92 50.355 ;
     RECT  2.16 50.625 79.92 50.895 ;
     RECT  2.16 51.165 79.92 51.435 ;
     RECT  2.16 51.705 79.92 51.975 ;
     RECT  2.16 52.245 79.92 52.515 ;
     RECT  2.16 52.785 79.92 53.055 ;
     RECT  2.16 53.325 79.92 53.595 ;
     RECT  2.16 53.865 79.92 54 ;
    LAYER RVTP ;
     RECT  2.16 2.295 79.92 2.565 ;
     RECT  2.16 2.835 79.92 3.105 ;
     RECT  2.16 3.375 79.92 3.645 ;
     RECT  2.16 3.915 79.92 4.185 ;
     RECT  2.16 4.455 79.92 4.725 ;
     RECT  2.16 4.995 79.92 5.265 ;
     RECT  2.16 5.535 79.92 5.805 ;
     RECT  2.16 6.075 79.92 6.345 ;
     RECT  2.16 6.615 79.92 6.885 ;
     RECT  2.16 7.155 79.92 7.425 ;
     RECT  2.16 7.695 79.92 7.965 ;
     RECT  2.16 8.235 79.92 8.505 ;
     RECT  2.16 8.775 79.92 9.045 ;
     RECT  2.16 9.315 79.92 9.585 ;
     RECT  2.16 9.855 79.92 10.125 ;
     RECT  2.16 10.395 79.92 10.665 ;
     RECT  2.16 10.935 79.92 11.205 ;
     RECT  2.16 11.475 79.92 11.745 ;
     RECT  2.16 12.015 79.92 12.285 ;
     RECT  2.16 12.555 79.92 12.825 ;
     RECT  2.16 13.095 79.92 13.365 ;
     RECT  2.16 13.635 79.92 13.905 ;
     RECT  2.16 14.175 79.92 14.445 ;
     RECT  2.16 14.715 79.92 14.985 ;
     RECT  2.16 15.255 79.92 15.525 ;
     RECT  2.16 15.795 79.92 16.065 ;
     RECT  2.16 16.335 79.92 16.605 ;
     RECT  2.16 16.875 79.92 17.145 ;
     RECT  2.16 17.415 79.92 17.685 ;
     RECT  2.16 17.955 79.92 18.225 ;
     RECT  2.16 18.495 79.92 18.765 ;
     RECT  2.16 19.035 79.92 19.305 ;
     RECT  2.16 19.575 79.92 19.845 ;
     RECT  2.16 20.115 79.92 20.385 ;
     RECT  2.16 20.655 79.92 20.925 ;
     RECT  2.16 21.195 79.92 21.465 ;
     RECT  2.16 21.735 79.92 22.005 ;
     RECT  2.16 22.275 79.92 22.545 ;
     RECT  2.16 22.815 79.92 23.085 ;
     RECT  2.16 23.355 79.92 23.625 ;
     RECT  2.16 23.895 79.92 24.165 ;
     RECT  2.16 24.435 79.92 24.705 ;
     RECT  2.16 24.975 79.92 25.245 ;
     RECT  2.16 25.515 79.92 25.785 ;
     RECT  2.16 26.055 79.92 26.325 ;
     RECT  2.16 26.595 79.92 26.865 ;
     RECT  2.16 27.135 79.92 27.405 ;
     RECT  2.16 27.675 79.92 27.945 ;
     RECT  2.16 28.215 79.92 28.485 ;
     RECT  2.16 28.755 79.92 29.025 ;
     RECT  2.16 29.295 79.92 29.565 ;
     RECT  2.16 29.835 79.92 30.105 ;
     RECT  2.16 30.375 79.92 30.645 ;
     RECT  2.16 30.915 79.92 31.185 ;
     RECT  2.16 31.455 79.92 31.725 ;
     RECT  2.16 31.995 79.92 32.265 ;
     RECT  2.16 32.535 79.92 32.805 ;
     RECT  2.16 33.075 79.92 33.345 ;
     RECT  2.16 33.615 79.92 33.885 ;
     RECT  2.16 34.155 79.92 34.425 ;
     RECT  2.16 34.695 79.92 34.965 ;
     RECT  2.16 35.235 79.92 35.505 ;
     RECT  2.16 35.775 79.92 36.045 ;
     RECT  2.16 36.315 79.92 36.585 ;
     RECT  2.16 36.855 79.92 37.125 ;
     RECT  2.16 37.395 79.92 37.665 ;
     RECT  2.16 37.935 79.92 38.205 ;
     RECT  2.16 38.475 79.92 38.745 ;
     RECT  2.16 39.015 79.92 39.285 ;
     RECT  2.16 39.555 79.92 39.825 ;
     RECT  2.16 40.095 79.92 40.365 ;
     RECT  2.16 40.635 79.92 40.905 ;
     RECT  2.16 41.175 79.92 41.445 ;
     RECT  2.16 41.715 79.92 41.985 ;
     RECT  2.16 42.255 79.92 42.525 ;
     RECT  2.16 42.795 79.92 43.065 ;
     RECT  2.16 43.335 79.92 43.605 ;
     RECT  2.16 43.875 79.92 44.145 ;
     RECT  2.16 44.415 79.92 44.685 ;
     RECT  2.16 44.955 79.92 45.225 ;
     RECT  2.16 45.495 79.92 45.765 ;
     RECT  2.16 46.035 79.92 46.305 ;
     RECT  2.16 46.575 79.92 46.845 ;
     RECT  2.16 47.115 79.92 47.385 ;
     RECT  2.16 47.655 79.92 47.925 ;
     RECT  2.16 48.195 79.92 48.465 ;
     RECT  2.16 48.735 79.92 49.005 ;
     RECT  2.16 49.275 79.92 49.545 ;
     RECT  2.16 49.815 79.92 50.085 ;
     RECT  2.16 50.355 79.92 50.625 ;
     RECT  2.16 50.895 79.92 51.165 ;
     RECT  2.16 51.435 79.92 51.705 ;
     RECT  2.16 51.975 79.92 52.245 ;
     RECT  2.16 52.515 79.92 52.785 ;
     RECT  2.16 53.055 79.92 53.325 ;
     RECT  2.16 53.595 79.92 53.865 ;
    LAYER M1 ;
     RECT  2.16 2.151 79.92 54.009 ;
    LAYER M2 ;
     RECT  1.687 52.866 2.155 53.01 ;
     RECT  2.155 47.286 2.16 47.304 ;
     RECT  2.155 52.488 2.16 53.01 ;
     RECT  2.16 2.151 4.135 54.009 ;
     RECT  4.135 2.106 5.495 54.009 ;
     RECT  5.495 2.151 23.431 54.009 ;
     RECT  23.431 2.151 24.403 54.054 ;
     RECT  24.403 2.106 25.223 54.054 ;
     RECT  25.223 2.151 35.771 54.054 ;
     RECT  35.771 2.151 40.819 54.009 ;
     RECT  40.819 2.106 43.331 54.009 ;
     RECT  43.331 2.151 44.491 54.009 ;
     RECT  44.491 2.106 48.523 54.009 ;
     RECT  48.523 2.07 50.071 54.009 ;
     RECT  50.071 1.998 51.359 54.009 ;
     RECT  51.359 2.151 79.92 54.009 ;
     RECT  79.92 6.66 80.051 10.692 ;
     RECT  79.92 31.158 80.411 34.488 ;
     RECT  80.051 6.66 80.915 10.62 ;
     RECT  80.915 10.602 80.951 10.62 ;
     RECT  80.411 31.158 80.951 34.11 ;
     RECT  80.915 6.66 80.987 9.81 ;
     RECT  80.987 6.822 81.023 9.81 ;
     RECT  80.951 31.932 81.455 34.11 ;
     RECT  81.023 6.966 81.491 9.81 ;
     RECT  81.455 31.932 81.491 32.994 ;
     RECT  81.455 34.092 81.491 34.11 ;
     RECT  81.491 6.966 81.527 7.182 ;
     RECT  81.491 7.974 81.527 9.81 ;
     RECT  80.951 31.158 81.527 31.176 ;
     RECT  81.527 8.208 81.959 9.81 ;
     RECT  81.527 7.164 81.995 7.182 ;
     RECT  81.959 8.208 81.995 8.604 ;
     RECT  81.959 9.792 81.995 9.81 ;
     RECT  81.491 32.076 81.995 32.526 ;
    LAYER M3 ;
     RECT  4.608 0.091 4.626 0.571 ;
     RECT  5.508 0.091 5.526 0.571 ;
     RECT  4.608 0.571 5.526 1.099 ;
     RECT  45.144 0.571 45.162 1.099 ;
     RECT  4.608 1.099 5.562 1.147 ;
     RECT  6.3 0.571 6.318 1.147 ;
     RECT  45.144 1.099 45.342 1.147 ;
     RECT  45.108 1.147 45.342 1.195 ;
     RECT  45.108 1.195 45.378 1.627 ;
     RECT  4.608 1.147 6.318 1.723 ;
     RECT  46.728 0.091 46.746 1.723 ;
     RECT  47.736 0.091 47.754 1.723 ;
     RECT  4.608 1.723 6.894 1.771 ;
     RECT  46.116 1.723 46.746 1.771 ;
     RECT  47.736 1.723 48.402 1.771 ;
     RECT  49.896 0.571 49.914 1.771 ;
     RECT  49.824 1.771 49.914 1.993 ;
     RECT  46.116 1.771 48.402 2.065 ;
     RECT  49.824 1.993 50.094 2.065 ;
     RECT  4.608 1.771 7.074 2.101 ;
     RECT  44.748 1.627 45.378 2.101 ;
     RECT  49.824 2.065 50.526 2.101 ;
     RECT  51.336 1.993 51.354 2.101 ;
     RECT  24.408 2.101 24.426 2.143 ;
     RECT  40.824 2.101 41.13 2.143 ;
     RECT  44.496 2.101 45.378 2.143 ;
     RECT  46.116 2.065 48.546 2.143 ;
     RECT  7.815 2.143 7.905 2.191 ;
     RECT  24.015 2.143 24.426 2.191 ;
     RECT  25.2 2.101 25.218 2.191 ;
     RECT  34.815 2.143 34.905 2.191 ;
     RECT  44.496 2.143 48.546 2.191 ;
     RECT  49.824 2.101 51.354 2.191 ;
     RECT  13.215 2.143 13.305 2.227 ;
     RECT  18.615 2.143 18.705 2.227 ;
     RECT  31.464 2.191 31.482 2.227 ;
     RECT  34.776 2.191 34.905 2.227 ;
     RECT  35.82 2.191 35.838 2.227 ;
     RECT  56.415 2.143 56.505 2.227 ;
     RECT  61.815 2.143 61.905 2.227 ;
     RECT  62.784 2.191 62.802 2.227 ;
     RECT  73.548 2.191 73.566 2.227 ;
     RECT  18.615 2.227 18.738 2.251 ;
     RECT  72.615 2.143 72.705 2.251 ;
     RECT  4.14 2.101 7.074 2.255 ;
     RECT  16.884 2.227 16.902 2.263 ;
     RECT  21.096 2.191 21.654 2.263 ;
     RECT  40.215 2.143 41.13 2.263 ;
     RECT  42.408 2.251 42.426 2.263 ;
     RECT  43.308 2.101 43.326 2.263 ;
     RECT  44.496 2.191 51.858 2.263 ;
     RECT  61.815 2.227 63.306 2.263 ;
     RECT  64.152 2.227 64.17 2.263 ;
     RECT  65.988 2.227 66.438 2.263 ;
     RECT  67.215 2.143 67.305 2.263 ;
     RECT  72.615 2.251 72.774 2.263 ;
     RECT  73.548 2.227 73.926 2.263 ;
     RECT  13.104 2.227 13.305 2.299 ;
     RECT  14.256 2.263 14.274 2.299 ;
     RECT  24.015 2.191 25.218 2.299 ;
     RECT  31.464 2.227 31.878 2.299 ;
     RECT  34.056 2.227 36.234 2.299 ;
     RECT  71.604 2.293 71.622 2.299 ;
     RECT  13.104 2.299 14.274 2.335 ;
     RECT  23.976 2.299 25.218 2.335 ;
     RECT  26.784 2.299 26.874 2.335 ;
     RECT  29.415 2.143 29.505 2.335 ;
     RECT  30.312 2.191 30.33 2.335 ;
     RECT  31.392 2.299 31.878 2.335 ;
     RECT  34.02 2.299 36.522 2.335 ;
     RECT  57.708 2.263 57.726 2.335 ;
     RECT  60.768 2.263 61.002 2.335 ;
     RECT  61.815 2.263 64.17 2.335 ;
     RECT  70.488 2.299 70.506 2.335 ;
     RECT  18.252 2.251 18.738 2.347 ;
     RECT  19.764 2.335 19.782 2.347 ;
     RECT  71.604 2.299 71.874 2.347 ;
     RECT  4.248 2.255 7.074 2.371 ;
     RECT  7.815 2.191 8.838 2.371 ;
     RECT  10.872 2.335 10.89 2.371 ;
     RECT  12.456 2.335 14.274 2.371 ;
     RECT  15.012 2.227 15.03 2.371 ;
     RECT  18.252 2.347 19.782 2.371 ;
     RECT  21.096 2.263 22.05 2.371 ;
     RECT  29.124 2.335 29.505 2.371 ;
     RECT  42.408 2.263 43.326 2.371 ;
     RECT  57.6 2.335 57.726 2.371 ;
     RECT  70.488 2.335 70.614 2.371 ;
     RECT  71.532 2.347 71.874 2.371 ;
     RECT  2.415 2.143 2.505 2.413 ;
     RECT  28.872 2.371 29.505 2.413 ;
     RECT  30.312 2.335 31.878 2.413 ;
     RECT  65.988 2.263 67.305 2.413 ;
     RECT  78.015 2.143 78.105 2.413 ;
     RECT  57.6 2.371 58.374 2.443 ;
     RECT  16.884 2.263 17.046 2.461 ;
     RECT  17.82 2.371 19.782 2.461 ;
     RECT  26.784 2.335 27.846 2.461 ;
     RECT  28.872 2.413 31.878 2.461 ;
     RECT  32.688 2.335 33.282 2.461 ;
     RECT  34.02 2.335 36.954 2.461 ;
     RECT  54.756 2.371 54.774 2.461 ;
     RECT  65.988 2.413 67.497 2.461 ;
     RECT  68.652 2.335 68.67 2.461 ;
     RECT  57.528 2.443 58.374 2.489 ;
     RECT  10.872 2.371 11.034 2.497 ;
     RECT  26.712 2.461 36.954 2.497 ;
     RECT  23.796 2.335 25.794 2.533 ;
     RECT  39.168 2.335 39.186 2.533 ;
     RECT  40.215 2.263 41.202 2.533 ;
     RECT  52.92 2.461 52.938 2.533 ;
     RECT  54.54 2.461 54.774 2.533 ;
     RECT  10.548 2.497 11.034 2.569 ;
     RECT  26.604 2.497 36.954 2.569 ;
     RECT  52.92 2.533 53.01 2.569 ;
     RECT  55.62 2.335 55.638 2.569 ;
     RECT  56.415 2.227 56.754 2.569 ;
     RECT  57.636 2.489 58.374 2.569 ;
     RECT  10.476 2.569 11.034 2.605 ;
     RECT  38.232 2.335 38.25 2.605 ;
     RECT  39.168 2.533 41.202 2.605 ;
     RECT  42.3 2.371 43.326 2.605 ;
     RECT  57.636 2.569 58.734 2.605 ;
     RECT  59.544 2.371 59.562 2.605 ;
     RECT  61.815 2.335 64.602 2.605 ;
     RECT  70.488 2.371 71.874 2.605 ;
     RECT  72.615 2.263 73.926 2.605 ;
     RECT  10.404 2.605 11.538 2.641 ;
     RECT  12.456 2.371 15.57 2.641 ;
     RECT  16.452 2.461 17.046 2.641 ;
     RECT  26.604 2.569 36.99 2.641 ;
     RECT  38.196 2.605 38.25 2.641 ;
     RECT  39.168 2.605 43.65 2.641 ;
     RECT  44.46 2.263 51.858 2.641 ;
     RECT  52.848 2.569 53.622 2.641 ;
     RECT  61.776 2.605 64.638 2.641 ;
     RECT  65.988 2.461 68.67 2.641 ;
     RECT  4.248 2.371 8.838 2.731 ;
     RECT  54.504 2.533 54.882 2.731 ;
     RECT  55.62 2.569 56.754 2.731 ;
     RECT  60.48 2.335 61.002 2.731 ;
     RECT  65.988 2.641 69.174 2.731 ;
     RECT  70.488 2.605 73.926 2.731 ;
     RECT  21.096 2.371 22.986 2.767 ;
     RECT  23.724 2.533 25.794 2.767 ;
     RECT  26.604 2.641 37.134 2.767 ;
     RECT  10.188 2.641 17.046 2.803 ;
     RECT  38.016 2.641 43.65 2.803 ;
     RECT  44.46 2.641 53.622 2.803 ;
     RECT  60.48 2.731 61.038 2.803 ;
     RECT  61.776 2.641 65.07 2.803 ;
     RECT  70.488 2.731 74.646 2.803 ;
     RECT  21.096 2.767 37.134 2.827 ;
     RECT  21.06 2.827 37.134 2.839 ;
     RECT  10.008 2.803 17.046 2.861 ;
     RECT  54.504 2.731 56.754 2.875 ;
     RECT  60.48 2.803 65.07 2.875 ;
     RECT  17.82 2.461 19.818 2.911 ;
     RECT  20.7 2.839 37.134 2.911 ;
     RECT  65.988 2.731 69.282 2.911 ;
     RECT  70.416 2.803 74.646 2.911 ;
     RECT  75.996 2.731 76.014 2.911 ;
     RECT  76.86 2.767 76.878 2.911 ;
     RECT  57.636 2.605 59.562 2.971 ;
     RECT  60.336 2.875 65.07 2.971 ;
     RECT  38.016 2.803 53.622 3.001 ;
     RECT  54.468 2.875 56.898 3.001 ;
     RECT  57.636 2.971 65.07 3.001 ;
     RECT  65.916 2.911 69.282 3.001 ;
     RECT  70.416 2.911 74.754 3.001 ;
     RECT  17.82 2.911 37.134 3.029 ;
     RECT  75.996 2.911 76.878 3.037 ;
     RECT  10.404 2.861 17.046 3.067 ;
     RECT  17.82 3.029 22.338 3.067 ;
     RECT  57.636 3.001 69.282 3.073 ;
     RECT  57.636 3.073 69.462 3.109 ;
     RECT  70.38 3.001 74.754 3.109 ;
     RECT  57.636 3.109 74.754 3.145 ;
     RECT  75.996 3.037 76.914 3.145 ;
     RECT  23.076 3.029 37.134 3.181 ;
     RECT  38.016 3.001 56.898 3.211 ;
     RECT  57.636 3.145 76.914 3.211 ;
     RECT  4.248 2.731 9.198 3.271 ;
     RECT  23.076 3.181 37.17 3.299 ;
     RECT  3.888 3.271 9.198 3.307 ;
     RECT  23.112 3.299 37.17 3.341 ;
     RECT  3.78 3.307 9.198 3.379 ;
     RECT  38.016 3.211 76.914 3.379 ;
     RECT  3.672 3.379 9.198 3.415 ;
     RECT  23.508 3.341 37.17 3.451 ;
     RECT  38.016 3.379 77.022 3.451 ;
     RECT  3.528 3.415 9.198 3.613 ;
     RECT  2.415 2.413 2.697 3.721 ;
     RECT  3.492 3.613 9.198 3.721 ;
     RECT  10.404 3.067 22.338 3.721 ;
     RECT  23.508 3.451 77.022 3.955 ;
     RECT  78.015 2.413 78.297 3.955 ;
     RECT  10.26 3.721 22.338 4.081 ;
     RECT  2.415 3.721 2.754 4.153 ;
     RECT  3.492 3.721 9.522 4.225 ;
     RECT  10.26 4.081 22.698 4.225 ;
     RECT  3.492 4.225 22.698 4.261 ;
     RECT  23.508 3.955 78.297 4.261 ;
     RECT  2.376 4.153 2.754 4.531 ;
     RECT  3.492 4.261 78.297 4.531 ;
     RECT  2.376 4.531 78.297 4.963 ;
     RECT  2.376 4.963 78.354 5.035 ;
     RECT  2.376 5.035 78.534 5.063 ;
     RECT  2.415 5.063 78.534 5.539 ;
     RECT  2.415 5.539 78.786 5.845 ;
     RECT  2.415 5.845 78.966 6.385 ;
     RECT  2.415 6.385 79.038 6.781 ;
     RECT  80.964 6.655 80.982 6.817 ;
     RECT  80.964 6.817 81.018 6.955 ;
     RECT  80.856 6.955 81.018 6.961 ;
     RECT  80.856 6.961 81.522 7.051 ;
     RECT  2.415 6.781 79.722 7.147 ;
     RECT  80.856 7.051 81.99 7.147 ;
     RECT  2.415 7.147 81.99 8.843 ;
     RECT  81.936 8.843 81.99 9.164 ;
     RECT  2.415 8.843 80.946 9.617 ;
     RECT  81.972 9.164 81.99 9.815 ;
     RECT  80.856 9.617 80.946 10.391 ;
     RECT  2.415 9.617 80.082 10.463 ;
     RECT  80.928 10.391 80.946 10.625 ;
     RECT  2.415 10.463 80.046 10.697 ;
     RECT  2.415 10.697 79.902 10.733 ;
     RECT  2.415 10.733 79.398 11.507 ;
     RECT  12.42 11.507 79.398 11.785 ;
     RECT  12.42 11.785 79.794 11.939 ;
     RECT  2.415 11.507 11.646 12.091 ;
     RECT  2.376 12.091 11.646 12.245 ;
     RECT  2.415 12.245 11.646 12.487 ;
     RECT  12.42 11.939 79.182 12.487 ;
     RECT  2.415 12.487 79.182 14.341 ;
     RECT  2.34 14.341 79.182 14.711 ;
     RECT  2.415 14.711 79.182 15.601 ;
     RECT  2.415 15.601 79.506 15.863 ;
     RECT  2.415 15.863 79.182 16.529 ;
     RECT  76.32 16.529 79.182 17.221 ;
     RECT  2.415 16.529 75.582 17.411 ;
     RECT  71.748 17.411 75.582 17.491 ;
     RECT  76.32 17.221 79.362 17.491 ;
     RECT  71.748 17.491 79.362 17.609 ;
     RECT  71.82 17.609 79.362 17.693 ;
     RECT  72.144 17.693 79.362 17.761 ;
     RECT  72.144 17.761 79.506 17.789 ;
     RECT  72.504 17.789 79.506 17.915 ;
     RECT  72.615 17.915 79.362 18.221 ;
     RECT  2.415 17.411 70.866 18.257 ;
     RECT  72.615 18.221 79.182 18.491 ;
     RECT  28.584 18.257 70.866 18.571 ;
     RECT  28.584 18.571 71.514 18.689 ;
     RECT  70.128 18.689 71.514 18.841 ;
     RECT  72.615 18.491 79.11 18.841 ;
     RECT  2.415 18.257 27.846 19.039 ;
     RECT  28.584 18.689 69.318 19.039 ;
     RECT  2.415 19.039 69.318 19.507 ;
     RECT  70.128 18.841 79.11 19.507 ;
     RECT  2.415 19.507 79.11 19.607 ;
     RECT  2.415 19.607 78.822 20.389 ;
     RECT  2.415 20.389 79.434 20.615 ;
     RECT  2.415 20.615 26.262 20.779 ;
     RECT  2.376 20.779 26.262 20.849 ;
     RECT  22.644 20.849 26.262 20.993 ;
     RECT  2.376 20.849 21.87 21.155 ;
     RECT  23.112 20.993 26.262 21.361 ;
     RECT  27.216 20.615 79.434 21.361 ;
     RECT  2.415 21.155 21.87 21.667 ;
     RECT  2.415 21.667 22.338 21.739 ;
     RECT  23.112 21.361 79.434 21.739 ;
     RECT  2.415 21.739 79.434 24.205 ;
     RECT  2.415 24.205 79.47 24.511 ;
     RECT  2.376 24.511 79.47 24.935 ;
     RECT  2.415 24.935 79.47 25.007 ;
     RECT  32.508 25.007 79.47 25.313 ;
     RECT  2.415 25.007 31.77 25.771 ;
     RECT  32.508 25.313 79.434 25.771 ;
     RECT  2.415 25.771 79.434 29.335 ;
     RECT  2.304 29.335 79.434 29.669 ;
     RECT  2.304 29.669 75.006 29.795 ;
     RECT  75.852 29.669 79.434 30.613 ;
     RECT  2.415 29.795 75.006 30.955 ;
     RECT  75.816 30.613 79.434 30.955 ;
     RECT  80.424 31.189 80.442 31.387 ;
     RECT  81.504 31.153 81.522 31.387 ;
     RECT  80.424 31.387 81.522 31.495 ;
     RECT  80.388 31.495 81.522 31.565 ;
     RECT  2.415 30.955 79.434 31.621 ;
     RECT  80.424 31.565 81.522 32.011 ;
     RECT  2.415 31.621 79.506 32.341 ;
     RECT  80.424 32.011 81.99 32.341 ;
     RECT  2.415 32.341 81.99 32.459 ;
     RECT  80.316 32.459 81.99 32.531 ;
     RECT  80.316 32.531 81.522 32.621 ;
     RECT  2.415 32.459 79.47 33.511 ;
     RECT  80.316 32.621 81.486 33.511 ;
     RECT  2.415 33.511 81.486 33.809 ;
     RECT  2.415 33.809 79.542 33.845 ;
     RECT  80.316 33.809 81.486 33.989 ;
     RECT  81.468 33.989 81.486 34.115 ;
     RECT  80.316 33.989 80.406 34.421 ;
     RECT  80.388 34.421 80.406 34.493 ;
     RECT  2.415 33.845 79.506 34.771 ;
     RECT  2.415 34.771 79.578 34.889 ;
     RECT  2.415 34.889 79.434 37.201 ;
     RECT  2.376 37.201 79.434 37.589 ;
     RECT  2.415 37.589 79.434 38.011 ;
     RECT  2.415 38.011 79.686 38.201 ;
     RECT  2.415 38.201 79.434 41.251 ;
     RECT  2.376 41.251 79.434 42.323 ;
     RECT  2.412 42.323 79.434 42.365 ;
     RECT  2.415 42.365 79.434 43.645 ;
     RECT  2.376 43.645 79.434 43.915 ;
     RECT  2.34 43.915 79.434 44.887 ;
     RECT  2.34 44.887 79.794 45.341 ;
     RECT  2.34 45.341 79.614 46.237 ;
     RECT  2.304 46.237 79.614 46.805 ;
     RECT  2.304 46.805 79.506 47.281 ;
     RECT  2.16 47.281 79.506 48.001 ;
     RECT  2.16 48.001 79.722 49.279 ;
     RECT  2.16 49.279 79.794 50.189 ;
     RECT  2.16 50.189 35.91 51.169 ;
     RECT  36.792 50.189 79.794 51.169 ;
     RECT  2.16 51.169 79.794 51.899 ;
     RECT  2.16 51.899 79.722 52.861 ;
     RECT  1.692 52.861 79.722 52.979 ;
     RECT  1.692 52.979 79.65 53.021 ;
     RECT  2.268 53.021 79.65 53.069 ;
     RECT  74.196 53.069 79.65 53.249 ;
     RECT  74.34 53.249 79.614 53.285 ;
     RECT  2.268 53.069 72.99 53.357 ;
     RECT  59.292 53.357 72.99 53.393 ;
     RECT  2.268 53.357 58.482 53.519 ;
     RECT  59.292 53.393 71.766 53.519 ;
     RECT  72.615 53.393 72.99 53.519 ;
     RECT  74.412 53.285 79.614 53.519 ;
     RECT  38.124 53.519 58.482 53.555 ;
     RECT  61.524 53.519 71.766 53.555 ;
     RECT  38.124 53.555 58.446 53.591 ;
     RECT  61.56 53.555 68.85 53.591 ;
     RECT  2.268 53.519 37.35 53.597 ;
     RECT  38.124 53.591 48.978 53.597 ;
     RECT  49.716 53.591 58.446 53.597 ;
     RECT  74.412 53.519 79.29 53.627 ;
     RECT  69.948 53.555 71.766 53.699 ;
     RECT  39.348 53.597 41.778 53.747 ;
     RECT  72.615 53.519 72.897 53.747 ;
     RECT  2.268 53.597 32.562 53.789 ;
     RECT  33.336 53.597 36.306 53.789 ;
     RECT  37.188 53.597 37.35 53.789 ;
     RECT  38.124 53.597 38.142 53.789 ;
     RECT  41.04 53.747 41.778 53.789 ;
     RECT  43.02 53.597 48.978 53.789 ;
     RECT  49.752 53.597 58.446 53.789 ;
     RECT  59.292 53.519 60.678 53.789 ;
     RECT  61.815 53.591 68.85 53.789 ;
     RECT  74.556 53.627 79.29 53.789 ;
     RECT  22.68 53.789 31.698 53.825 ;
     RECT  37.188 53.789 37.206 53.825 ;
     RECT  39.348 53.747 40.305 53.825 ;
     RECT  48.96 53.789 48.978 53.825 ;
     RECT  55.296 53.789 58.446 53.825 ;
     RECT  59.292 53.789 59.31 53.825 ;
     RECT  68.112 53.789 68.85 53.825 ;
     RECT  70.092 53.699 71.766 53.825 ;
     RECT  77.58 53.789 79.29 53.837 ;
     RECT  33.66 53.789 35.766 53.848 ;
     RECT  7.38 53.789 19.818 53.861 ;
     RECT  30.42 53.825 31.374 53.861 ;
     RECT  65.7 53.789 67.305 53.861 ;
     RECT  22.68 53.825 29.505 53.897 ;
     RECT  56.232 53.825 57.942 53.897 ;
     RECT  20.556 53.789 20.574 53.933 ;
     RECT  21.672 53.789 21.762 53.933 ;
     RECT  22.68 53.897 27.954 53.933 ;
     RECT  30.672 53.861 31.374 53.933 ;
     RECT  34.776 53.848 34.905 53.933 ;
     RECT  39.348 53.825 39.474 53.933 ;
     RECT  41.04 53.789 41.058 53.933 ;
     RECT  43.488 53.789 47.898 53.933 ;
     RECT  56.232 53.897 56.505 53.933 ;
     RECT  65.7 53.861 66.366 53.933 ;
     RECT  68.832 53.825 68.85 53.933 ;
     RECT  70.092 53.825 71.406 53.933 ;
     RECT  74.628 53.789 76.77 53.933 ;
     RECT  77.94 53.837 79.29 53.933 ;
     RECT  2.268 53.789 6.642 53.969 ;
     RECT  7.38 53.861 18.705 53.969 ;
     RECT  19.692 53.861 19.818 53.969 ;
     RECT  21.672 53.933 21.69 53.969 ;
     RECT  22.68 53.933 22.698 53.969 ;
     RECT  23.436 53.933 27.954 53.969 ;
     RECT  29.304 53.897 29.505 53.969 ;
     RECT  31.356 53.933 31.374 53.969 ;
     RECT  33.66 53.848 33.678 53.969 ;
     RECT  35.676 53.848 35.766 53.969 ;
     RECT  39.456 53.933 39.474 53.969 ;
     RECT  43.488 53.933 47.142 53.969 ;
     RECT  47.88 53.933 47.898 53.969 ;
     RECT  54.108 53.789 54.126 53.969 ;
     RECT  55.296 53.825 55.314 53.969 ;
     RECT  57.42 53.897 57.438 53.969 ;
     RECT  70.668 53.933 70.686 53.969 ;
     RECT  79.272 53.933 79.29 53.969 ;
     RECT  2.268 53.969 3.978 53.981 ;
     RECT  7.38 53.969 17.802 53.981 ;
     RECT  43.488 53.969 46.746 53.981 ;
     RECT  74.7 53.933 76.77 53.981 ;
     RECT  18.615 53.969 18.705 54.017 ;
     RECT  23.436 53.969 27.414 54.017 ;
     RECT  29.415 53.969 29.505 54.017 ;
     RECT  34.815 53.933 34.905 54.017 ;
     RECT  40.215 53.825 40.305 54.017 ;
     RECT  56.415 53.933 56.505 54.017 ;
     RECT  61.815 53.789 64.926 54.017 ;
     RECT  67.215 53.861 67.305 54.017 ;
     RECT  72.615 53.747 72.705 54.017 ;
     RECT  7.452 53.981 17.802 54.029 ;
     RECT  62.352 54.017 64.926 54.029 ;
     RECT  23.436 54.017 23.454 54.059 ;
     RECT  24.264 54.017 27.414 54.059 ;
     RECT  35.748 53.969 35.766 54.059 ;
     RECT  10.188 54.029 17.802 54.077 ;
     RECT  24.264 54.059 26.19 54.077 ;
     RECT  49.824 53.789 52.902 54.077 ;
     RECT  75.42 53.981 75.762 54.077 ;
     RECT  2.376 53.981 3.654 54.125 ;
     RECT  5.04 53.969 6.318 54.125 ;
     RECT  7.452 54.029 9.306 54.125 ;
     RECT  10.188 54.077 12.366 54.125 ;
     RECT  13.176 54.077 17.802 54.125 ;
     RECT  19.8 53.969 19.818 54.125 ;
     RECT  24.264 54.077 26.082 54.125 ;
     RECT  43.56 53.981 46.314 54.125 ;
     RECT  49.824 54.077 52.758 54.125 ;
     RECT  62.352 54.029 64.89 54.125 ;
     RECT  65.7 53.933 65.718 54.125 ;
     RECT  75.42 54.077 75.438 54.125 ;
     RECT  76.5 53.981 76.77 54.125 ;
     RECT  77.94 53.933 78.498 54.125 ;
     RECT  2.376 54.125 2.898 54.173 ;
     RECT  7.452 54.125 7.794 54.173 ;
     RECT  12.168 54.125 12.186 54.173 ;
     RECT  13.176 54.125 14.274 54.173 ;
     RECT  43.812 54.125 46.314 54.173 ;
     RECT  13.356 54.173 14.274 54.221 ;
     RECT  45.936 54.173 46.314 54.221 ;
     RECT  77.94 54.125 77.958 54.221 ;
     RECT  13.536 54.221 14.274 54.269 ;
     RECT  15.516 54.125 17.802 54.605 ;
     RECT  15.516 54.605 17.01 54.701 ;
     RECT  17.784 54.605 17.802 54.701 ;
     RECT  43.812 54.173 44.442 54.701 ;
     RECT  15.516 54.701 16.686 54.749 ;
     RECT  46.08 54.221 46.314 54.749 ;
     RECT  62.352 54.125 63.162 54.749 ;
     RECT  76.752 54.125 76.77 54.749 ;
     RECT  25.02 54.125 25.722 54.845 ;
     RECT  7.452 54.173 7.47 55.277 ;
     RECT  9.288 54.125 9.306 55.277 ;
     RECT  10.332 54.125 11.286 55.277 ;
     RECT  13.644 54.269 14.274 55.277 ;
     RECT  15.516 54.749 16.002 55.277 ;
     RECT  5.04 54.125 5.742 55.325 ;
     RECT  13.644 55.277 14.238 55.325 ;
     RECT  15.768 55.277 16.002 55.325 ;
     RECT  24.264 54.125 24.282 55.325 ;
     RECT  25.704 54.845 25.722 55.325 ;
     RECT  27.216 54.059 27.234 55.325 ;
     RECT  43.812 54.701 43.83 55.325 ;
     RECT  50.076 54.125 50.094 55.325 ;
     RECT  50.976 54.125 51.462 55.325 ;
     RECT  62.352 54.749 62.658 55.325 ;
     RECT  2.88 54.173 2.898 55.771 ;
     RECT  19.332 55.723 19.35 55.819 ;
     RECT  2.844 55.771 2.898 55.901 ;
     RECT  52.488 54.125 52.506 55.901 ;
     RECT  2.844 55.901 2.862 55.915 ;
     RECT  2.556 55.915 2.862 56.045 ;
     RECT  3.636 54.125 3.654 56.045 ;
     RECT  12.42 55.915 12.438 56.045 ;
     RECT  14.22 55.325 14.238 56.045 ;
     RECT  19.08 55.819 19.35 56.045 ;
     RECT  46.296 54.749 46.314 56.045 ;
     RECT  50.472 55.915 50.49 56.045 ;
     RECT  51.444 55.325 51.462 56.045 ;
     RECT  62.352 55.325 62.37 56.045 ;
    LAYER M4 ;
     RECT  1.573 52.896 1.669 52.92 ;
     RECT  1.669 52.896 1.861 53.016 ;
     RECT  1.477 54.096 1.861 54.12 ;
     RECT  1.765 51.504 1.957 51.528 ;
     RECT  1.957 51.408 2.053 51.528 ;
     RECT  2.053 51.408 2.149 51.624 ;
     RECT  2.149 51.408 2.293 51.672 ;
     RECT  2.293 55.92 2.341 55.944 ;
     RECT  1.861 52.896 2.365 54.12 ;
     RECT  2.293 18.192 2.408 18.216 ;
     RECT  2.293 19.2 2.408 19.224 ;
     RECT  2.293 20.784 2.408 20.808 ;
     RECT  0.06 29.52 2.408 29.928 ;
     RECT  2.293 42.336 2.408 42.36 ;
     RECT  2.285 43.92 2.408 43.944 ;
     RECT  2.365 45.168 2.408 45.192 ;
     RECT  2.365 46.608 2.408 47.736 ;
     RECT  2.329 50.112 2.408 50.136 ;
     RECT  2.293 51.36 2.408 51.672 ;
     RECT  2.365 52.896 2.408 54.168 ;
     RECT  2.408 2.148 2.512 54.168 ;
     RECT  2.512 2.418 2.62 54.168 ;
     RECT  2.62 2.418 2.704 54.12 ;
     RECT  2.341 55.92 2.725 56.04 ;
     RECT  2.725 55.872 2.833 56.04 ;
     RECT  2.704 13.68 2.981 17.112 ;
     RECT  2.704 25.44 2.981 27.096 ;
     RECT  2.833 55.776 3.011 56.04 ;
     RECT  2.981 13.68 3.089 15.336 ;
     RECT  2.704 37.632 3.155 41.688 ;
     RECT  2.704 53.568 3.305 54.12 ;
     RECT  2.704 42.72 3.347 52.488 ;
     RECT  3.347 46.224 3.443 52.488 ;
     RECT  3.347 42.72 3.491 45.192 ;
     RECT  3.491 43.248 3.521 45.192 ;
     RECT  2.704 24.144 3.557 24.168 ;
     RECT  3.089 13.68 3.665 14.568 ;
     RECT  3.011 56.016 3.665 56.04 ;
     RECT  2.704 29.76 3.701 30.456 ;
     RECT  2.704 10.176 3.733 11.448 ;
     RECT  2.704 12.528 3.733 12.552 ;
     RECT  3.733 10.176 3.773 12.552 ;
     RECT  2.704 18.096 3.841 19.704 ;
     RECT  2.704 20.928 3.841 21.528 ;
     RECT  2.704 5.136 3.877 7.896 ;
     RECT  3.665 14.16 3.917 14.568 ;
     RECT  3.841 18.096 3.917 21.528 ;
     RECT  3.877 4.992 3.953 7.896 ;
     RECT  2.981 16.416 3.985 17.112 ;
     RECT  3.443 46.368 3.989 52.488 ;
     RECT  3.305 53.568 3.989 53.976 ;
     RECT  3.985 16.368 4.019 17.112 ;
     RECT  3.773 10.176 4.025 11.784 ;
     RECT  3.917 14.16 4.025 14.184 ;
     RECT  3.733 3.84 4.057 3.864 ;
     RECT  3.953 4.992 4.057 6.264 ;
     RECT  3.917 19.68 4.093 21.528 ;
     RECT  2.704 22.752 4.093 23.16 ;
     RECT  3.989 46.368 4.133 51.864 ;
     RECT  2.704 35.808 4.169 36.12 ;
     RECT  3.155 37.632 4.169 38.856 ;
     RECT  4.169 35.808 4.273 35.832 ;
     RECT  4.019 16.368 4.309 16.872 ;
     RECT  2.704 34.08 4.309 34.104 ;
     RECT  4.169 37.92 4.309 38.856 ;
     RECT  3.155 40.08 4.309 41.688 ;
     RECT  3.953 7.776 4.313 7.896 ;
     RECT  2.981 25.44 4.313 25.464 ;
     RECT  4.309 33.648 4.313 34.104 ;
     RECT  4.273 35.328 4.313 35.832 ;
     RECT  3.989 53.568 4.345 53.736 ;
     RECT  4.093 19.68 4.349 23.16 ;
     RECT  4.309 37.92 4.349 41.688 ;
     RECT  3.697 24.384 4.381 24.408 ;
     RECT  4.025 10.512 4.385 11.784 ;
     RECT  3.841 13.008 4.385 13.08 ;
     RECT  4.309 16.128 4.385 16.872 ;
     RECT  4.385 16.128 4.405 16.776 ;
     RECT  4.385 13.008 4.451 13.032 ;
     RECT  2.704 31.92 4.453 32.52 ;
     RECT  4.313 33.648 4.453 33.672 ;
     RECT  4.385 10.848 4.457 11.784 ;
     RECT  4.405 15.984 4.493 16.776 ;
     RECT  4.133 50.544 4.493 51.864 ;
     RECT  4.345 53.184 4.493 53.736 ;
     RECT  3.701 30.096 4.525 30.456 ;
     RECT  4.453 31.92 4.525 33.672 ;
     RECT  4.349 39.168 4.525 41.688 ;
     RECT  3.521 43.248 4.525 44.952 ;
     RECT  4.133 46.368 4.525 49.176 ;
     RECT  4.493 16.752 4.529 16.776 ;
     RECT  4.349 22.224 4.561 23.16 ;
     RECT  4.381 24.384 4.561 25.272 ;
     RECT  2.981 27.072 4.597 27.096 ;
     RECT  2.704 28.512 4.597 28.728 ;
     RECT  4.597 27.072 4.745 28.728 ;
     RECT  4.745 27.888 4.813 28.728 ;
     RECT  4.313 35.328 4.849 35.352 ;
     RECT  3.917 18.096 4.885 18.456 ;
     RECT  4.561 22.224 4.969 25.272 ;
     RECT  4.313 7.872 4.993 7.896 ;
     RECT  4.849 1.104 5.029 1.128 ;
     RECT  4.813 27.888 5.029 29.064 ;
     RECT  4.525 30.096 5.029 33.672 ;
     RECT  4.885 18.096 5.065 18.696 ;
     RECT  4.349 19.68 5.065 21.096 ;
     RECT  5.029 1.104 5.125 1.752 ;
     RECT  4.525 39.168 5.209 49.176 ;
     RECT  4.493 50.544 5.209 51.288 ;
     RECT  4.597 0.096 5.221 0.12 ;
     RECT  5.125 1.104 5.221 1.8 ;
     RECT  5.209 39.168 5.315 51.288 ;
     RECT  4.993 7.872 5.317 8.808 ;
     RECT  4.493 53.568 5.317 53.736 ;
     RECT  5.065 18.096 5.357 21.096 ;
     RECT  5.317 7.872 5.425 8.856 ;
     RECT  5.389 9.936 5.425 9.96 ;
     RECT  5.029 14.4 5.425 14.424 ;
     RECT  5.425 14.4 5.461 14.712 ;
     RECT  5.357 18.096 5.533 18.696 ;
     RECT  4.349 37.92 5.533 38.184 ;
     RECT  5.315 39.168 5.533 49.608 ;
     RECT  5.221 0.096 5.537 1.8 ;
     RECT  5.537 0.576 5.564 1.8 ;
     RECT  5.137 2.832 5.564 2.856 ;
     RECT  4.457 11.424 5.641 11.784 ;
     RECT  5.461 14.4 5.641 15.432 ;
     RECT  5.533 37.92 5.669 49.608 ;
     RECT  5.533 17.76 5.677 18.696 ;
     RECT  4.849 35.184 5.701 35.352 ;
     RECT  5.669 37.056 5.701 49.608 ;
     RECT  5.641 14.4 5.713 15.528 ;
     RECT  5.425 7.872 5.717 9.96 ;
     RECT  5.641 11.376 5.725 12.552 ;
     RECT  5.317 53.568 5.749 54.12 ;
     RECT  5.029 27.888 5.789 33.672 ;
     RECT  5.725 11.376 5.825 11.784 ;
     RECT  5.029 55.296 5.843 55.32 ;
     RECT  5.713 14.4 5.857 15.576 ;
     RECT  5.564 0.576 5.897 2.856 ;
     RECT  5.789 27.888 5.897 30.936 ;
     RECT  5.701 35.184 5.897 49.608 ;
     RECT  5.065 26.4 5.965 26.568 ;
     RECT  5.897 27.888 5.965 30.792 ;
     RECT  5.357 19.68 5.969 21.096 ;
     RECT  4.057 3.84 5.989 6.264 ;
     RECT  5.717 7.872 5.989 9.096 ;
     RECT  5.789 31.968 6.001 33.672 ;
     RECT  5.989 3.84 6.005 9.096 ;
     RECT  5.897 1.728 6.035 2.856 ;
     RECT  5.857 14.4 6.044 16.536 ;
     RECT  6.044 13.104 6.131 16.536 ;
     RECT  6.001 31.968 6.145 34.152 ;
     RECT  5.897 35.184 6.145 49.56 ;
     RECT  6.005 3.84 6.179 7.896 ;
     RECT  5.677 17.664 6.181 18.696 ;
     RECT  5.749 53.04 6.181 54.12 ;
     RECT  4.969 23.952 6.289 25.272 ;
     RECT  5.965 26.4 6.289 30.792 ;
     RECT  5.897 0.576 6.329 0.6 ;
     RECT  6.289 23.952 6.329 30.792 ;
     RECT  6.181 52.56 6.329 54.12 ;
     RECT  5.825 11.376 6.373 11.448 ;
     RECT  5.315 50.688 6.373 51.288 ;
     RECT  6.329 52.56 6.373 53.976 ;
     RECT  4.969 22.224 6.38 22.68 ;
     RECT  6.131 14.4 6.397 16.536 ;
     RECT  6.181 17.616 6.397 18.696 ;
     RECT  6.397 14.4 6.437 18.696 ;
     RECT  6.179 3.84 6.469 6.264 ;
     RECT  5.969 19.872 6.476 21.096 ;
     RECT  6.38 22.08 6.476 22.68 ;
     RECT  6.476 19.872 6.541 22.68 ;
     RECT  6.035 1.728 6.581 2.328 ;
     RECT  6.469 3.36 6.581 6.264 ;
     RECT  6.373 50.688 6.581 51.336 ;
     RECT  6.581 1.728 6.617 1.896 ;
     RECT  6.005 8.928 6.653 9.096 ;
     RECT  6.131 13.104 6.653 13.224 ;
     RECT  6.653 8.928 6.659 8.952 ;
     RECT  6.581 50.928 6.757 51.336 ;
     RECT  6.373 52.32 6.757 53.976 ;
     RECT  6.541 19.872 6.761 22.872 ;
     RECT  6.761 19.872 6.794 21.144 ;
     RECT  6.437 15.36 6.797 18.696 ;
     RECT  6.617 1.728 6.833 1.848 ;
     RECT  6.833 1.728 6.94 1.8 ;
     RECT  6.94 1.776 7.085 1.8 ;
     RECT  6.179 7.248 7.189 7.896 ;
     RECT  6.145 31.968 7.397 49.56 ;
     RECT  6.997 55.968 7.397 55.992 ;
     RECT  6.581 3.36 7.405 4.488 ;
     RECT  7.397 55.248 7.429 55.992 ;
     RECT  6.581 5.472 7.441 6.264 ;
     RECT  7.189 7.248 7.441 8.52 ;
     RECT  6.794 19.872 7.441 21 ;
     RECT  6.653 13.104 7.477 13.176 ;
     RECT  6.373 10.08 7.621 11.448 ;
     RECT  7.429 55.152 7.621 55.992 ;
     RECT  6.797 15.36 7.657 15.816 ;
     RECT  6.797 16.8 7.657 18.696 ;
     RECT  7.441 19.776 7.657 21 ;
     RECT  6.757 50.928 7.657 53.976 ;
     RECT  7.405 3.168 7.669 4.488 ;
     RECT  7.477 12.864 7.729 13.176 ;
     RECT  7.657 14.928 7.729 15.816 ;
     RECT  7.621 55.056 7.763 55.992 ;
     RECT  7.657 50.88 7.765 53.976 ;
     RECT  7.669 2.784 7.808 4.488 ;
     RECT  7.441 5.472 7.808 8.52 ;
     RECT  7.621 10.08 7.808 11.496 ;
     RECT  7.729 12.864 7.808 15.816 ;
     RECT  7.657 16.8 7.808 21 ;
     RECT  6.761 22.224 7.808 22.872 ;
     RECT  6.329 23.952 7.808 24.024 ;
     RECT  6.329 25.104 7.808 30.792 ;
     RECT  7.397 31.968 7.808 49.608 ;
     RECT  7.765 50.88 7.808 54.168 ;
     RECT  7.808 2.148 7.859 54.168 ;
     RECT  7.859 2.148 7.912 54.12 ;
     RECT  7.912 2.418 8.104 54.12 ;
     RECT  8.104 3.84 8.201 5.88 ;
     RECT  8.104 10.368 8.201 10.392 ;
     RECT  8.201 4.464 8.273 5.88 ;
     RECT  8.273 4.656 8.531 5.88 ;
     RECT  8.531 5.088 8.572 5.88 ;
     RECT  8.104 6.864 8.849 6.888 ;
     RECT  8.104 29.232 8.885 30.696 ;
     RECT  8.104 12.432 8.921 24.504 ;
     RECT  8.921 14.928 9.029 24.504 ;
     RECT  7.763 55.248 9.059 55.992 ;
     RECT  8.104 32.064 9.097 50.808 ;
     RECT  8.104 51.792 9.097 54.12 ;
     RECT  8.104 25.584 9.137 28.2 ;
     RECT  9.137 25.776 9.169 28.2 ;
     RECT  8.572 5.472 9.277 5.88 ;
     RECT  8.104 8.4 9.353 9.24 ;
     RECT  9.029 17.136 9.461 24.504 ;
     RECT  8.921 12.432 9.497 13.656 ;
     RECT  9.353 8.4 9.637 9 ;
     RECT  9.461 23.952 9.677 24.504 ;
     RECT  9.097 32.064 9.677 54.12 ;
     RECT  9.677 32.064 9.713 51.624 ;
     RECT  9.529 10.944 9.745 10.968 ;
     RECT  9.745 10.896 9.817 10.968 ;
     RECT  9.059 55.248 10.021 55.272 ;
     RECT  9.277 5.472 10.105 6.264 ;
     RECT  9.637 8.16 10.105 9 ;
     RECT  9.817 10.8 10.109 10.968 ;
     RECT  10.021 55.248 10.211 55.992 ;
     RECT  10.105 5.472 10.393 9 ;
     RECT  10.177 10.032 10.393 10.056 ;
     RECT  9.997 2.832 10.429 2.856 ;
     RECT  9.169 25.776 10.465 28.584 ;
     RECT  10.465 25.728 10.537 28.584 ;
     RECT  9.713 32.064 10.541 38.568 ;
     RECT  10.537 25.392 10.573 28.584 ;
     RECT  8.885 29.568 10.573 30.696 ;
     RECT  10.285 11.184 10.609 11.448 ;
     RECT  9.497 12.768 10.609 13.656 ;
     RECT  9.029 14.928 10.609 16.056 ;
     RECT  9.461 17.136 10.609 22.872 ;
     RECT  9.713 49.584 10.717 51.624 ;
     RECT  9.677 52.848 10.717 54.12 ;
     RECT  10.573 25.392 10.825 30.696 ;
     RECT  10.541 32.064 10.853 32.568 ;
     RECT  10.609 11.184 10.865 13.656 ;
     RECT  10.825 25.392 10.897 30.84 ;
     RECT  10.853 31.872 10.897 32.568 ;
     RECT  9.713 39.792 10.897 48.6 ;
     RECT  10.717 49.584 10.897 54.12 ;
     RECT  10.609 14.928 11.041 22.872 ;
     RECT  9.677 23.952 11.041 24.216 ;
     RECT  10.865 11.184 11.077 11.448 ;
     RECT  10.429 2.832 11.117 3.672 ;
     RECT  10.897 39.792 11.149 54.12 ;
     RECT  10.211 55.248 11.149 55.272 ;
     RECT  10.393 5.472 11.257 10.056 ;
     RECT  11.077 11.04 11.257 11.448 ;
     RECT  11.041 14.928 11.333 24.216 ;
     RECT  11.333 22.704 11.461 24.216 ;
     RECT  10.897 25.392 11.461 32.568 ;
     RECT  10.541 33.792 11.513 38.568 ;
     RECT  11.149 55.2 11.603 55.272 ;
     RECT  11.461 22.704 11.729 32.568 ;
     RECT  11.333 14.928 11.765 21.72 ;
     RECT  11.149 39.6 11.795 54.12 ;
     RECT  11.729 22.848 11.801 32.568 ;
     RECT  11.795 39.6 11.873 52.872 ;
     RECT  11.257 5.472 11.909 11.448 ;
     RECT  11.513 33.888 11.909 38.568 ;
     RECT  11.873 39.6 11.939 52.584 ;
     RECT  11.765 18.672 12.017 21.72 ;
     RECT  11.909 33.888 12.017 35.208 ;
     RECT  11.801 29.568 12.053 32.568 ;
     RECT  11.603 55.248 12.085 55.272 ;
     RECT  11.117 3.648 12.14 3.672 ;
     RECT  11.909 36.288 12.157 38.568 ;
     RECT  11.939 39.6 12.157 51.528 ;
     RECT  11.795 54.048 12.157 54.12 ;
     RECT  12.14 3.648 12.181 4.152 ;
     RECT  12.181 3.408 12.227 4.152 ;
     RECT  10.865 12.48 12.301 13.656 ;
     RECT  11.765 14.928 12.301 17.64 ;
     RECT  12.085 55.248 12.37 55.992 ;
     RECT  12.227 3.408 12.409 3.96 ;
     RECT  11.909 11.184 12.589 11.448 ;
     RECT  12.301 12.48 12.589 17.64 ;
     RECT  12.589 11.184 12.805 17.64 ;
     RECT  12.017 19.152 12.805 21.72 ;
     RECT  11.801 22.848 12.805 28.488 ;
     RECT  12.157 54.048 12.805 54.168 ;
     RECT  12.805 11.184 12.877 17.688 ;
     RECT  11.939 52.56 12.901 52.584 ;
     RECT  12.805 53.568 12.901 54.168 ;
     RECT  12.157 36.288 12.913 51.528 ;
     RECT  12.901 52.56 12.913 54.168 ;
     RECT  12.877 11.184 13.021 17.928 ;
     RECT  12.805 19.152 13.021 28.488 ;
     RECT  12.409 2.736 13.208 3.96 ;
     RECT  11.909 5.472 13.208 10.104 ;
     RECT  13.021 11.136 13.208 28.488 ;
     RECT  12.053 29.568 13.208 32.52 ;
     RECT  12.017 34.416 13.208 35.208 ;
     RECT  12.913 36.288 13.208 54.168 ;
     RECT  13.208 2.148 13.248 54.168 ;
     RECT  13.248 2.148 13.312 54.216 ;
     RECT  13.312 2.418 13.381 54.216 ;
     RECT  13.381 2.418 13.504 54.264 ;
     RECT  13.504 2.88 13.565 54.264 ;
     RECT  13.565 7.392 13.709 54.12 ;
     RECT  13.565 2.88 13.715 6.408 ;
     RECT  13.709 7.392 13.781 15.576 ;
     RECT  13.709 16.56 13.817 54.12 ;
     RECT  13.715 2.88 14.105 6.264 ;
     RECT  12.37 55.248 14.249 56.04 ;
     RECT  13.817 16.56 14.285 52.44 ;
     RECT  14.249 55.248 14.285 55.272 ;
     RECT  13.817 53.568 14.321 54.12 ;
     RECT  14.285 16.56 14.357 49.08 ;
     RECT  14.357 16.656 14.393 29.064 ;
     RECT  14.105 3.84 14.684 6.264 ;
     RECT  13.781 7.392 14.684 15.528 ;
     RECT  14.285 50.16 14.933 52.44 ;
     RECT  14.569 2.736 15.212 2.76 ;
     RECT  14.684 3.84 15.212 15.528 ;
     RECT  14.933 51.6 15.253 52.44 ;
     RECT  15.212 2.736 15.299 15.528 ;
     RECT  14.933 50.16 15.329 50.52 ;
     RECT  15.299 2.832 15.433 15.528 ;
     RECT  14.393 16.848 15.433 29.064 ;
     RECT  14.321 54 15.493 54.12 ;
     RECT  15.433 2.832 15.541 29.064 ;
     RECT  14.357 30.048 15.541 49.08 ;
     RECT  15.493 53.568 15.589 54.12 ;
     RECT  15.505 55.248 15.589 55.272 ;
     RECT  15.541 2.832 15.617 49.08 ;
     RECT  15.589 53.568 15.689 55.272 ;
     RECT  15.617 14.256 15.721 49.08 ;
     RECT  15.689 53.952 15.757 55.272 ;
     RECT  15.253 51.6 15.761 52.536 ;
     RECT  15.721 14.256 15.797 49.176 ;
     RECT  15.761 51.84 15.797 52.536 ;
     RECT  15.757 53.952 16.057 55.32 ;
     RECT  15.797 14.256 16.229 24.648 ;
     RECT  15.797 25.68 16.297 49.176 ;
     RECT  15.329 50.16 16.297 50.184 ;
     RECT  16.297 25.68 16.441 50.184 ;
     RECT  16.229 14.256 16.481 19.08 ;
     RECT  16.441 25.68 16.553 50.28 ;
     RECT  16.553 30.912 16.661 50.28 ;
     RECT  15.797 51.84 16.729 52.44 ;
     RECT  15.617 2.832 16.765 13.272 ;
     RECT  16.729 51.504 16.765 52.44 ;
     RECT  16.765 2.832 16.873 13.704 ;
     RECT  16.765 51.504 16.945 52.872 ;
     RECT  16.057 53.952 16.945 54.744 ;
     RECT  16.661 36.336 16.981 50.28 ;
     RECT  16.945 51.504 16.981 54.744 ;
     RECT  16.229 20.064 17.485 24.648 ;
     RECT  16.553 25.68 17.485 29.784 ;
     RECT  16.981 36.336 17.555 54.744 ;
     RECT  16.481 14.736 17.557 19.08 ;
     RECT  17.485 20.064 17.557 29.784 ;
     RECT  16.873 2.256 17.593 13.704 ;
     RECT  17.557 14.736 17.593 29.784 ;
     RECT  16.661 30.912 17.593 35.064 ;
     RECT  17.593 2.256 17.708 35.064 ;
     RECT  17.555 36.336 17.708 54.696 ;
     RECT  17.708 2.256 17.857 54.696 ;
     RECT  17.941 55.968 18.229 55.992 ;
     RECT  17.857 2.256 18.608 54.012 ;
     RECT  18.608 2.148 18.712 54.012 ;
     RECT  18.712 2.256 18.749 53.742 ;
     RECT  18.229 55.872 18.853 55.992 ;
     RECT  18.749 2.352 18.904 53.742 ;
     RECT  18.853 55.776 18.949 55.992 ;
     RECT  18.949 55.68 19.042 55.992 ;
     RECT  19.042 55.68 19.091 56.04 ;
     RECT  19.091 55.728 19.372 56.04 ;
     RECT  19.372 55.92 19.379 56.04 ;
     RECT  19.379 56.016 19.405 56.04 ;
     RECT  18.904 3.6 19.649 53.742 ;
     RECT  19.649 51.216 19.789 53.742 ;
     RECT  18.904 2.352 19.793 2.52 ;
     RECT  19.649 3.6 19.793 49.896 ;
     RECT  19.793 2.496 19.829 2.52 ;
     RECT  19.789 51.216 19.873 54.12 ;
     RECT  19.793 3.6 20.257 49.176 ;
     RECT  19.873 51.216 20.297 53.784 ;
     RECT  20.297 52.848 20.477 53.784 ;
     RECT  20.297 51.216 20.725 51.816 ;
     RECT  20.477 52.848 20.729 53.736 ;
     RECT  20.729 53.616 20.837 53.736 ;
     RECT  20.257 3.312 20.941 49.176 ;
     RECT  20.941 3.312 20.977 49.608 ;
     RECT  20.725 50.976 20.977 51.816 ;
     RECT  20.977 3.312 21.049 51.816 ;
     RECT  20.581 56.016 21.107 56.04 ;
     RECT  21.049 2.832 21.233 51.816 ;
     RECT  21.233 2.832 21.413 51.432 ;
     RECT  21.413 2.832 21.481 49.992 ;
     RECT  20.837 53.616 21.733 53.64 ;
     RECT  21.733 52.992 22.097 53.64 ;
     RECT  21.481 2.784 22.133 49.992 ;
     RECT  22.133 2.784 22.205 49.896 ;
     RECT  22.205 3.216 22.385 49.896 ;
     RECT  21.413 50.976 22.597 51.432 ;
     RECT  22.097 52.992 22.921 53.448 ;
     RECT  22.597 50.88 23.101 51.432 ;
     RECT  22.385 49.536 23.137 49.896 ;
     RECT  23.101 50.88 23.137 51.48 ;
     RECT  23.137 49.536 23.173 51.48 ;
     RECT  22.921 52.656 23.173 53.448 ;
     RECT  22.385 3.216 23.533 48.408 ;
     RECT  23.173 49.536 23.533 53.448 ;
     RECT  23.533 3.216 23.641 53.448 ;
     RECT  23.641 2.88 23.965 53.448 ;
     RECT  23.965 2.304 24.008 53.448 ;
     RECT  24.008 2.148 24.112 54.012 ;
     RECT  24.112 2.304 24.304 54.012 ;
     RECT  24.304 2.304 24.473 52.008 ;
     RECT  24.304 53.568 24.562 54.012 ;
     RECT  24.253 55.296 24.659 55.32 ;
     RECT  24.473 2.304 24.725 51.864 ;
     RECT  24.562 53.568 24.757 54.024 ;
     RECT  24.757 53.568 25.009 54.12 ;
     RECT  25.009 53.568 25.523 54.84 ;
     RECT  24.725 2.352 25.621 51.864 ;
     RECT  25.621 2.352 25.697 51.912 ;
     RECT  25.697 2.352 25.805 50.04 ;
     RECT  25.805 2.688 25.985 50.04 ;
     RECT  25.523 53.568 26.137 54.12 ;
     RECT  26.137 53.568 26.201 54.072 ;
     RECT  25.985 2.688 26.773 49.896 ;
     RECT  26.773 2.304 26.885 49.896 ;
     RECT  26.885 2.832 26.993 49.896 ;
     RECT  25.697 51.264 27.133 51.912 ;
     RECT  26.201 53.568 27.133 53.88 ;
     RECT  27.133 51.264 27.205 53.88 ;
     RECT  26.993 2.88 27.241 49.896 ;
     RECT  27.241 2.88 27.313 50.184 ;
     RECT  27.205 51.264 27.313 53.928 ;
     RECT  27.313 2.88 27.347 53.928 ;
     RECT  27.347 2.88 27.533 53.88 ;
     RECT  25.693 55.296 27.539 55.32 ;
     RECT  27.533 2.88 27.857 52.776 ;
     RECT  27.857 3.024 28.933 52.776 ;
     RECT  28.933 2.784 29.408 52.776 ;
     RECT  27.533 53.856 29.408 53.88 ;
     RECT  29.408 2.148 29.512 54.012 ;
     RECT  29.512 2.418 29.704 53.742 ;
     RECT  29.704 2.592 30.747 53.4 ;
     RECT  30.747 2.592 31.309 53.496 ;
     RECT  31.309 2.592 31.381 53.544 ;
     RECT  31.381 2.304 31.561 53.544 ;
     RECT  31.561 2.304 34.261 53.592 ;
     RECT  34.261 2.304 34.405 53.832 ;
     RECT  34.405 2.256 34.808 53.832 ;
     RECT  34.808 2.148 34.912 54.012 ;
     RECT  34.912 2.256 35.381 53.832 ;
     RECT  35.381 2.256 35.525 53.592 ;
     RECT  35.525 2.88 38.801 53.592 ;
     RECT  38.801 2.88 39.685 53.4 ;
     RECT  39.685 2.832 40.208 53.4 ;
     RECT  40.208 2.148 40.312 54.012 ;
     RECT  40.312 2.418 40.504 53.742 ;
     RECT  40.504 2.496 40.565 53.592 ;
     RECT  40.565 2.88 42.397 53.592 ;
     RECT  42.397 2.256 42.437 53.592 ;
     RECT  42.437 2.256 42.515 53.4 ;
     RECT  42.515 2.88 42.617 53.4 ;
     RECT  42.617 3.12 43.477 53.4 ;
     RECT  43.477 3.12 43.549 53.976 ;
     RECT  43.801 55.296 44.243 55.32 ;
     RECT  43.549 3.12 44.413 54.12 ;
     RECT  44.413 3.12 44.819 54.696 ;
     RECT  44.819 3.12 44.821 54.216 ;
     RECT  44.737 1.632 45.097 1.656 ;
     RECT  45.097 1.152 45.133 1.656 ;
     RECT  45.133 0.576 45.205 1.656 ;
     RECT  44.821 3.024 45.205 54.216 ;
     RECT  45.205 0.576 45.299 54.216 ;
     RECT  45.299 1.104 45.971 54.216 ;
     RECT  45.971 1.728 46.069 54.216 ;
     RECT  45.925 56.016 46.325 56.04 ;
     RECT  46.069 1.728 46.739 54.744 ;
     RECT  46.739 1.728 46.757 53.976 ;
     RECT  46.757 1.728 46.937 53.4 ;
     RECT  46.937 1.728 47.729 1.896 ;
     RECT  46.597 0.096 47.749 0.12 ;
     RECT  47.749 0.096 47.765 0.6 ;
     RECT  47.729 1.728 48.017 1.848 ;
     RECT  48.017 1.728 48.413 1.8 ;
     RECT  46.937 3.024 49.345 53.4 ;
     RECT  48.413 1.776 49.477 1.8 ;
     RECT  49.345 2.88 49.477 53.4 ;
     RECT  49.477 1.776 49.705 53.4 ;
     RECT  49.705 1.776 49.813 53.592 ;
     RECT  49.813 1.776 49.853 54.12 ;
     RECT  47.765 0.576 49.925 0.6 ;
     RECT  50.065 55.296 50.245 55.32 ;
     RECT  50.245 55.296 50.434 55.992 ;
     RECT  49.853 2.352 51.008 54.12 ;
     RECT  51.008 2.148 51.112 54.12 ;
     RECT  51.112 2.352 51.304 54.12 ;
     RECT  50.434 55.296 51.347 56.04 ;
     RECT  51.347 55.872 51.473 56.04 ;
     RECT  51.304 2.352 51.761 52.296 ;
     RECT  51.473 55.872 52.259 55.992 ;
     RECT  52.259 55.872 52.517 55.896 ;
     RECT  51.304 53.376 52.769 54.12 ;
     RECT  51.761 2.784 52.909 52.296 ;
     RECT  52.769 53.376 52.909 54.072 ;
     RECT  52.909 2.784 52.913 54.072 ;
     RECT  52.913 2.784 52.921 53.976 ;
     RECT  52.921 2.784 52.949 53.592 ;
     RECT  52.949 2.784 53.093 53.4 ;
     RECT  53.093 3.024 54.065 53.4 ;
     RECT  54.065 3.072 55.573 53.4 ;
     RECT  55.573 2.736 56.221 53.4 ;
     RECT  56.221 2.736 56.408 53.592 ;
     RECT  56.408 2.148 56.512 54.012 ;
     RECT  56.512 2.418 56.704 53.742 ;
     RECT  56.704 2.448 56.873 53.592 ;
     RECT  56.873 2.448 57.845 53.4 ;
     RECT  57.845 2.736 58.925 53.4 ;
     RECT  58.925 3.12 60.181 53.4 ;
     RECT  60.181 2.976 60.325 53.4 ;
     RECT  60.325 2.88 60.613 53.4 ;
     RECT  60.613 2.832 61.808 53.4 ;
     RECT  61.808 2.148 61.912 54.012 ;
     RECT  62.377 54.72 62.629 54.744 ;
     RECT  62.341 56.016 62.629 56.04 ;
     RECT  61.912 2.304 62.881 53.742 ;
     RECT  62.629 54.72 62.881 56.04 ;
     RECT  62.881 2.304 63.155 56.04 ;
     RECT  63.155 2.304 63.251 55.32 ;
     RECT  63.251 2.304 63.317 54.744 ;
     RECT  63.317 2.688 63.353 54.744 ;
     RECT  63.353 35.232 63.443 54.744 ;
     RECT  63.353 2.688 64.037 34.2 ;
     RECT  64.037 2.688 64.073 19.128 ;
     RECT  64.037 20.352 64.289 34.2 ;
     RECT  64.073 2.784 64.541 19.128 ;
     RECT  64.541 2.784 64.883 18.264 ;
     RECT  64.289 20.352 65.005 33.912 ;
     RECT  63.443 35.232 65.405 54.12 ;
     RECT  65.405 35.232 65.545 35.592 ;
     RECT  65.405 36.576 65.693 54.12 ;
     RECT  65.693 53.328 65.773 54.12 ;
     RECT  64.883 2.928 66.013 18.264 ;
     RECT  65.773 53.328 66.089 53.736 ;
     RECT  66.089 53.328 66.125 53.64 ;
     RECT  65.005 19.44 66.193 33.912 ;
     RECT  65.545 34.896 66.193 35.592 ;
     RECT  66.013 2.304 66.62 18.264 ;
     RECT  66.193 19.44 66.62 35.592 ;
     RECT  65.693 36.576 66.769 51.864 ;
     RECT  66.125 53.328 66.769 53.592 ;
     RECT  66.62 2.304 67.208 35.592 ;
     RECT  66.769 36.576 67.208 53.592 ;
     RECT  67.208 2.148 67.312 54.012 ;
     RECT  67.312 2.418 67.504 53.742 ;
     RECT  67.504 2.832 67.667 53.592 ;
     RECT  67.667 2.832 68.033 53.4 ;
     RECT  68.033 2.832 68.723 51.336 ;
     RECT  68.723 3.408 68.897 51.336 ;
     RECT  68.033 52.56 68.969 53.4 ;
     RECT  68.897 3.648 69.329 51.336 ;
     RECT  69.329 3.648 69.401 50.808 ;
     RECT  69.401 3.936 69.473 50.808 ;
     RECT  68.969 52.56 69.757 53.064 ;
     RECT  69.473 26.544 69.833 50.808 ;
     RECT  69.833 32.976 69.869 50.808 ;
     RECT  69.869 50.16 69.941 50.808 ;
     RECT  69.869 32.976 70.157 48.936 ;
     RECT  69.757 52.176 70.157 53.064 ;
     RECT  69.941 50.16 70.193 50.424 ;
     RECT  69.473 3.936 70.517 25.56 ;
     RECT  70.517 4.416 70.549 25.56 ;
     RECT  69.833 26.544 70.549 31.896 ;
     RECT  70.477 2.304 70.585 2.328 ;
     RECT  70.549 4.416 70.697 31.896 ;
     RECT  70.697 4.416 70.733 28.968 ;
     RECT  70.157 32.976 70.787 39.912 ;
     RECT  70.733 18.432 70.835 28.968 ;
     RECT  70.835 28.464 70.877 28.968 ;
     RECT  70.157 41.088 71.089 48.936 ;
     RECT  70.787 33.072 71.093 39.912 ;
     RECT  70.193 50.4 71.233 50.424 ;
     RECT  71.089 41.088 71.269 48.984 ;
     RECT  70.835 18.432 71.281 27.384 ;
     RECT  70.585 2.304 71.521 2.376 ;
     RECT  71.281 24.672 71.561 27.384 ;
     RECT  71.521 2.304 71.633 3.048 ;
     RECT  71.093 33.6 71.701 39.912 ;
     RECT  71.269 40.992 71.701 48.984 ;
     RECT  70.733 4.416 71.809 17.4 ;
     RECT  71.281 18.432 71.809 23.304 ;
     RECT  70.877 28.464 71.845 28.872 ;
     RECT  71.633 3.024 71.989 3.048 ;
     RECT  71.809 4.416 71.989 23.304 ;
     RECT  71.701 33.6 71.989 48.984 ;
     RECT  71.989 33.6 72.097 49.08 ;
     RECT  71.233 50.4 72.097 50.712 ;
     RECT  71.845 28.464 72.133 29.064 ;
     RECT  70.697 30.192 72.133 31.896 ;
     RECT  72.097 33.6 72.277 50.712 ;
     RECT  70.157 52.176 72.277 52.968 ;
     RECT  71.561 24.672 72.313 27.192 ;
     RECT  72.277 33.6 72.349 50.904 ;
     RECT  72.349 33.6 72.469 50.952 ;
     RECT  71.989 3.024 72.608 23.304 ;
     RECT  72.313 24.624 72.608 27.192 ;
     RECT  72.133 28.464 72.608 31.896 ;
     RECT  72.469 33.552 72.608 50.952 ;
     RECT  72.277 52.176 72.608 53.064 ;
     RECT  72.608 2.148 72.712 54.012 ;
     RECT  72.712 2.256 72.904 53.742 ;
     RECT  72.904 3.6 73.001 22.104 ;
     RECT  73.001 3.6 73.037 17.688 ;
     RECT  72.904 29.808 73.145 50.424 ;
     RECT  73.037 3.6 73.361 17.208 ;
     RECT  72.904 2.256 73.577 2.28 ;
     RECT  73.145 29.808 73.613 49.752 ;
     RECT  73.613 44.16 73.757 49.752 ;
     RECT  73.361 3.648 74.041 17.208 ;
     RECT  73.001 18.96 74.041 22.104 ;
     RECT  72.904 23.568 74.053 28.776 ;
     RECT  73.757 44.208 74.081 49.752 ;
     RECT  74.081 44.304 74.153 49.752 ;
     RECT  72.904 51.936 74.252 53.064 ;
     RECT  74.153 45.024 74.321 49.752 ;
     RECT  74.252 50.976 74.321 53.064 ;
     RECT  74.053 23.376 74.329 28.776 ;
     RECT  74.321 45.024 74.329 53.064 ;
     RECT  74.041 18.96 74.389 22.2 ;
     RECT  74.329 23.28 74.389 28.776 ;
     RECT  74.389 18.96 74.441 28.776 ;
     RECT  74.041 3.648 74.617 17.688 ;
     RECT  74.441 19.968 74.653 28.776 ;
     RECT  73.613 29.808 74.653 42.792 ;
     RECT  74.653 19.968 74.657 42.792 ;
     RECT  74.329 45.024 74.689 53.256 ;
     RECT  74.617 2.736 74.729 17.688 ;
     RECT  74.657 29.472 74.737 42.792 ;
     RECT  74.729 2.736 74.765 16.584 ;
     RECT  74.689 45.024 74.837 53.976 ;
     RECT  74.737 30.288 74.905 42.792 ;
     RECT  74.441 18.96 74.977 18.984 ;
     RECT  74.905 30.288 75.017 43.176 ;
     RECT  75.017 30.384 75.061 43.176 ;
     RECT  75.061 30.384 75.148 43.56 ;
     RECT  74.729 17.664 75.157 17.688 ;
     RECT  74.977 18.768 75.157 18.984 ;
     RECT  74.765 2.736 75.233 14.856 ;
     RECT  75.233 3.936 75.341 14.856 ;
     RECT  75.157 17.664 75.341 18.984 ;
     RECT  74.765 16.416 75.377 16.584 ;
     RECT  74.657 19.968 75.377 28.488 ;
     RECT  74.837 45.072 75.409 53.976 ;
     RECT  75.377 20.496 75.413 28.488 ;
     RECT  75.341 18.768 75.481 18.984 ;
     RECT  75.341 3.936 75.557 14.136 ;
     RECT  75.557 3.936 75.731 13.848 ;
     RECT  75.413 26.352 75.809 28.488 ;
     RECT  75.409 45.072 75.829 54.12 ;
     RECT  75.481 18.768 75.845 19.464 ;
     RECT  75.233 2.736 76.025 2.76 ;
     RECT  75.148 30.384 76.025 43.32 ;
     RECT  75.413 20.496 76.061 25.272 ;
     RECT  76.025 30.384 76.097 43.176 ;
     RECT  76.097 30.384 76.165 40.296 ;
     RECT  75.731 5.136 76.313 13.848 ;
     RECT  75.809 28.464 76.345 28.488 ;
     RECT  76.061 23.856 76.349 25.272 ;
     RECT  75.377 16.416 76.381 16.44 ;
     RECT  76.097 41.472 76.385 43.176 ;
     RECT  76.165 30.192 76.421 40.296 ;
     RECT  76.349 23.904 76.453 25.272 ;
     RECT  75.809 26.352 76.453 27.48 ;
     RECT  76.345 28.464 76.565 28.968 ;
     RECT  76.453 23.904 76.637 27.48 ;
     RECT  75.829 44.4 76.741 54.12 ;
     RECT  75.731 3.936 76.745 3.96 ;
     RECT  76.421 30.192 76.781 36.36 ;
     RECT  76.781 30.24 76.835 36.36 ;
     RECT  75.341 17.664 76.889 17.688 ;
     RECT  76.385 42.192 76.961 43.176 ;
     RECT  76.741 44.4 76.979 54.744 ;
     RECT  76.637 23.904 76.997 26.28 ;
     RECT  76.997 24.672 77.033 26.28 ;
     RECT  75.845 19.008 77.101 19.464 ;
     RECT  76.061 20.496 77.101 22.776 ;
     RECT  76.961 42.576 77.125 43.176 ;
     RECT  76.979 44.4 77.125 54.216 ;
     RECT  76.381 15.984 77.173 16.632 ;
     RECT  77.101 19.008 77.497 22.776 ;
     RECT  76.421 37.632 77.509 40.296 ;
     RECT  77.509 37.632 77.701 40.824 ;
     RECT  76.637 27.312 77.749 27.48 ;
     RECT  76.565 28.944 77.749 28.968 ;
     RECT  76.313 5.136 77.857 13.32 ;
     RECT  77.857 5.136 77.893 13.608 ;
     RECT  76.705 14.784 77.893 14.808 ;
     RECT  77.893 5.136 78.008 14.808 ;
     RECT  77.173 15.984 78.008 17.064 ;
     RECT  77.497 18.432 78.008 22.776 ;
     RECT  77.033 24.912 78.008 26.28 ;
     RECT  77.749 27.312 78.008 28.968 ;
     RECT  76.835 30.48 78.008 36.36 ;
     RECT  77.701 37.632 78.008 41.016 ;
     RECT  77.125 42.576 78.008 54.216 ;
     RECT  78.008 2.148 78.035 54.216 ;
     RECT  78.035 2.148 78.112 54.168 ;
     RECT  78.112 2.418 78.304 54.168 ;
     RECT  78.304 5.472 78.365 5.496 ;
     RECT  78.304 6.576 78.401 7.752 ;
     RECT  78.304 13.104 78.401 14.136 ;
     RECT  78.304 22.176 78.401 28.2 ;
     RECT  78.304 9.024 78.419 11.976 ;
     RECT  78.304 19.584 78.419 21.048 ;
     RECT  78.401 22.176 78.419 26.904 ;
     RECT  78.304 42.816 78.419 54.168 ;
     RECT  78.401 7.104 78.437 7.752 ;
     RECT  78.419 20.88 78.437 21.048 ;
     RECT  78.304 31.2 78.437 35.016 ;
     RECT  78.419 42.816 78.437 54.12 ;
     RECT  78.419 22.224 78.467 22.296 ;
     RECT  78.401 27.888 78.467 28.2 ;
     RECT  78.304 36.336 78.473 36.36 ;
     RECT  78.304 15.168 78.509 16.92 ;
     RECT  78.437 53.904 78.509 54.12 ;
     RECT  78.401 13.296 78.545 14.136 ;
     RECT  78.437 20.88 78.545 20.952 ;
     RECT  78.419 23.808 78.545 26.904 ;
     RECT  78.437 42.816 78.545 52.488 ;
     RECT  78.304 29.28 78.563 29.304 ;
     RECT  78.509 15.168 78.581 15.72 ;
     RECT  78.467 28.176 78.581 28.2 ;
     RECT  78.437 7.104 78.617 7.704 ;
     RECT  78.545 13.296 78.617 13.848 ;
     RECT  78.437 31.392 78.617 35.016 ;
     RECT  78.545 20.928 78.653 20.952 ;
     RECT  78.304 37.632 78.653 39.336 ;
     RECT  78.509 16.896 78.689 16.92 ;
     RECT  78.653 39.312 78.689 39.336 ;
     RECT  78.304 41.376 78.689 41.4 ;
     RECT  78.419 19.632 78.725 19.848 ;
     RECT  78.545 23.808 78.725 26.808 ;
     RECT  78.617 31.392 78.725 34.2 ;
     RECT  78.304 18.432 78.761 18.456 ;
     RECT  78.467 22.224 78.761 22.248 ;
     RECT  78.725 24.192 78.761 26.808 ;
     RECT  78.725 31.68 78.761 34.104 ;
     RECT  78.653 37.632 78.761 37.656 ;
     RECT  78.545 44.928 78.796 52.488 ;
     RECT  78.617 7.2 78.797 7.704 ;
     RECT  78.617 13.296 78.797 13.32 ;
     RECT  78.761 24.192 78.797 25.32 ;
     RECT  78.419 11.952 78.833 11.976 ;
     RECT  78.545 43.056 78.833 43.944 ;
     RECT  78.796 44.928 78.833 45.576 ;
     RECT  78.419 9.024 78.869 10.728 ;
     RECT  78.797 25.296 78.869 25.32 ;
     RECT  78.761 26.496 78.869 26.808 ;
     RECT  78.761 31.68 78.905 33.096 ;
     RECT  78.581 15.168 78.941 15.192 ;
     RECT  78.796 46.992 78.941 52.488 ;
     RECT  78.869 9.264 78.977 10.728 ;
     RECT  78.797 24.192 79.013 24.216 ;
     RECT  78.833 43.296 79.013 43.32 ;
     RECT  78.833 44.928 79.036 45.384 ;
     RECT  78.941 48.336 79.043 52.488 ;
     RECT  79.043 48.432 79.057 52.488 ;
     RECT  78.869 26.496 79.085 26.52 ;
     RECT  79.057 48.72 79.091 52.488 ;
     RECT  78.941 46.992 79.139 47.304 ;
     RECT  78.509 53.904 79.157 53.928 ;
     RECT  79.091 50.736 79.193 51.768 ;
     RECT  78.761 34.08 79.265 34.104 ;
     RECT  78.977 9.264 79.301 10.2 ;
     RECT  79.301 9.36 79.337 10.2 ;
     RECT  79.139 46.992 79.409 47.016 ;
     RECT  79.091 48.72 79.517 49.32 ;
     RECT  79.193 50.736 79.523 51.24 ;
     RECT  79.517 49.296 79.625 49.32 ;
     RECT  79.477 53.04 79.625 53.064 ;
     RECT  79.523 50.736 79.661 50.856 ;
     RECT  79.036 44.928 79.805 45.336 ;
     RECT  79.805 45.312 79.811 45.336 ;
     RECT  79.661 50.736 79.811 50.76 ;
     RECT  78.797 7.2 80.161 7.224 ;
     RECT  80.161 7.2 80.305 7.272 ;
     RECT  78.905 32.064 80.305 33.096 ;
     RECT  80.305 7.152 80.341 7.272 ;
     RECT  79.337 9.36 80.341 9.864 ;
     RECT  80.305 32.064 80.377 33.672 ;
     RECT  80.341 7.152 80.845 9.864 ;
     RECT  80.377 31.536 80.917 33.672 ;
     RECT  80.845 6.96 80.953 9.864 ;
     RECT  80.953 6.864 82.044 9.864 ;
     RECT  80.917 31.44 82.044 33.672 ;
    LAYER M5 ;
     RECT  45.264 0.016 48.264 0.611 ;
     RECT  4.944 0.016 6.984 1.139 ;
     RECT  5.04 1.139 6.984 1.763 ;
     RECT  5.136 1.763 6.984 1.811 ;
     RECT  45.36 0.611 48.264 1.811 ;
     RECT  5.616 1.811 6.792 1.859 ;
     RECT  5.616 1.859 6.6 1.907 ;
     RECT  2.4 2.137 2.52 2.151 ;
     RECT  7.8 2.137 7.92 2.151 ;
     RECT  13.2 2.137 13.32 2.151 ;
     RECT  18.6 2.137 18.72 2.151 ;
     RECT  24 2.137 24.12 2.151 ;
     RECT  29.4 2.137 29.52 2.151 ;
     RECT  34.8 2.137 34.92 2.151 ;
     RECT  40.2 2.137 40.32 2.151 ;
     RECT  51 2.137 51.12 2.151 ;
     RECT  56.4 2.137 56.52 2.151 ;
     RECT  61.8 2.137 61.92 2.151 ;
     RECT  67.2 2.137 67.32 2.151 ;
     RECT  72.6 2.137 72.72 2.151 ;
     RECT  78 2.137 78.12 2.151 ;
     RECT  5.616 1.907 6.216 2.291 ;
     RECT  6 2.291 6.12 2.339 ;
     RECT  29.4 2.151 29.712 2.581 ;
     RECT  31.872 2.293 31.896 2.627 ;
     RECT  34.8 2.151 35.112 2.629 ;
     RECT  29.4 2.581 30.12 2.725 ;
     RECT  7.8 2.151 8.112 2.773 ;
     RECT  51 2.151 51.312 2.773 ;
     RECT  40.2 2.151 40.512 2.821 ;
     RECT  56.4 2.151 56.712 2.821 ;
     RECT  6 2.339 6.024 2.867 ;
     RECT  45.36 1.811 48.168 3.013 ;
     RECT  29.4 2.725 30.408 3.109 ;
     RECT  7.68 2.773 8.112 3.203 ;
     RECT  24 2.151 24.312 3.253 ;
     RECT  26.592 2.677 26.616 3.299 ;
     RECT  24 3.253 24.552 3.397 ;
     RECT  49.488 2.485 49.512 3.397 ;
     RECT  51 2.773 51.864 3.397 ;
     RECT  55.872 2.821 56.712 3.397 ;
     RECT  24 3.397 25.368 3.443 ;
     RECT  64.848 2.773 64.872 3.443 ;
     RECT  68.688 2.821 68.712 3.443 ;
     RECT  15.264 2.725 15.288 3.587 ;
     RECT  39.696 2.821 40.512 3.685 ;
     RECT  39.648 3.685 40.512 3.781 ;
     RECT  29.4 3.109 30.6 3.829 ;
     RECT  49.488 3.397 51.864 3.875 ;
     RECT  61.8 2.151 62.112 3.877 ;
     RECT  34.224 2.629 35.112 3.925 ;
     RECT  75.696 3.925 75.72 3.973 ;
     RECT  22.176 3.205 22.2 4.019 ;
     RECT  42.48 2.245 42.504 4.021 ;
     RECT  44.832 3.013 48.168 4.021 ;
     RECT  49.488 3.875 51.312 4.021 ;
     RECT  44.832 4.021 51.312 4.067 ;
     RECT  25.344 3.443 25.368 4.069 ;
     RECT  44.832 4.067 46.248 4.115 ;
     RECT  48.144 4.067 51.312 4.163 ;
     RECT  61.8 3.877 62.664 4.213 ;
     RECT  45.504 4.115 46.248 4.307 ;
     RECT  38.736 3.781 40.512 4.357 ;
     RECT  54.912 3.397 56.712 4.403 ;
     RECT  56.4 4.403 56.712 4.405 ;
     RECT  14.832 3.925 14.856 4.547 ;
     RECT  45.6 4.307 46.248 4.643 ;
     RECT  7.8 3.203 8.112 4.645 ;
     RECT  38.736 4.357 40.92 4.645 ;
     RECT  42.192 4.021 42.504 4.645 ;
     RECT  45.6 4.643 46.056 4.691 ;
     RECT  74.976 3.973 75.72 4.691 ;
     RECT  68.928 3.877 68.952 4.739 ;
     RECT  25.344 4.069 26.184 4.885 ;
     RECT  38.736 4.645 43.32 4.933 ;
     RECT  52.992 4.165 53.016 5.077 ;
     RECT  65.808 4.837 65.832 5.077 ;
     RECT  67.2 2.151 67.512 5.077 ;
     RECT  72.6 2.151 72.912 5.125 ;
     RECT  25.344 4.885 26.568 5.171 ;
     RECT  48.672 4.163 51.312 5.171 ;
     RECT  54.912 4.403 55.032 5.171 ;
     RECT  61.8 4.213 62.808 5.171 ;
     RECT  6.48 3.349 6.504 5.219 ;
     RECT  74.976 4.691 75 5.267 ;
     RECT  60.72 5.125 60.744 5.315 ;
     RECT  72.6 5.125 73.176 5.317 ;
     RECT  29.4 3.829 30.744 5.459 ;
     RECT  6.624 5.461 6.648 5.605 ;
     RECT  7.8 4.645 8.52 5.605 ;
     RECT  13.2 2.151 13.512 5.605 ;
     RECT  38.736 4.933 43.656 5.699 ;
     RECT  45.6 4.691 45.912 5.701 ;
     RECT  52.992 5.077 53.064 5.701 ;
     RECT  52.992 5.701 53.544 5.747 ;
     RECT  42.48 5.699 43.656 5.795 ;
     RECT  18.6 2.151 18.912 5.845 ;
     RECT  6.624 5.605 8.52 5.891 ;
     RECT  21.12 4.405 21.144 5.941 ;
     RECT  53.04 5.747 53.544 5.941 ;
     RECT  21.12 5.941 21.288 5.987 ;
     RECT  36.912 3.925 36.936 5.989 ;
     RECT  61.8 5.171 62.712 6.037 ;
     RECT  53.04 5.941 53.592 6.083 ;
     RECT  2.4 2.151 2.712 6.133 ;
     RECT  16.512 5.029 16.536 6.133 ;
     RECT  65.808 5.077 67.656 6.133 ;
     RECT  25.344 5.171 25.368 6.181 ;
     RECT  45.6 5.701 46.488 6.229 ;
     RECT  72.6 5.317 73.656 6.229 ;
     RECT  76.8 5.125 76.824 6.275 ;
     RECT  36.816 5.989 36.936 6.323 ;
     RECT  48.816 5.171 51.312 6.323 ;
     RECT  38.736 5.699 40.92 6.325 ;
     RECT  13.2 5.605 13.704 6.419 ;
     RECT  38.448 6.325 40.92 6.419 ;
     RECT  38.448 6.419 40.512 6.467 ;
     RECT  24 3.443 24.312 6.469 ;
     RECT  25.344 6.181 26.04 6.469 ;
     RECT  27.024 6.277 27.048 6.515 ;
     RECT  24 6.469 26.04 6.611 ;
     RECT  45.024 6.229 46.488 6.611 ;
     RECT  6.624 5.891 8.112 6.709 ;
     RECT  2.4 6.133 2.808 6.851 ;
     RECT  24 6.611 25.368 6.851 ;
     RECT  12.192 3.397 12.216 6.853 ;
     RECT  13.2 6.419 13.512 6.853 ;
     RECT  12.192 6.853 13.512 6.899 ;
     RECT  17.856 5.845 18.912 6.947 ;
     RECT  63.792 3.205 63.816 6.997 ;
     RECT  33.312 3.925 35.112 7.045 ;
     RECT  56.4 4.405 57 7.045 ;
     RECT  65.808 6.133 67.752 7.091 ;
     RECT  63.792 6.997 63.912 7.139 ;
     RECT  68.976 6.085 69 7.139 ;
     RECT  53.52 6.083 53.592 7.141 ;
     RECT  6.144 6.709 8.112 7.189 ;
     RECT  21.264 5.987 21.288 7.189 ;
     RECT  48.96 6.323 51.312 7.189 ;
     RECT  58.512 7.045 58.536 7.189 ;
     RECT  21.168 7.189 21.288 7.235 ;
     RECT  48.96 7.189 51.768 7.235 ;
     RECT  29.4 5.459 30.6 7.237 ;
     RECT  42.96 5.795 43.656 7.285 ;
     RECT  29.232 7.237 30.6 7.333 ;
     RECT  17.952 6.947 18.912 7.379 ;
     RECT  33.312 7.045 35.208 7.379 ;
     RECT  52.8 7.141 53.592 7.379 ;
     RECT  14.736 6.805 14.76 7.381 ;
     RECT  28.8 7.333 30.6 7.381 ;
     RECT  53.04 7.379 53.592 7.381 ;
     RECT  55.008 5.171 55.032 7.381 ;
     RECT  61.68 6.037 62.712 7.381 ;
     RECT  71.28 4.693 71.304 7.381 ;
     RECT  72.6 6.229 74.088 7.381 ;
     RECT  12.528 6.899 13.512 7.427 ;
     RECT  67.104 7.091 67.752 7.427 ;
     RECT  71.28 7.381 74.088 7.427 ;
     RECT  25.344 6.851 25.368 7.475 ;
     RECT  42.72 7.285 43.656 7.475 ;
     RECT  28.8 7.381 30.792 7.621 ;
     RECT  36.912 6.323 36.936 7.621 ;
     RECT  56.4 7.045 57.048 7.765 ;
     RECT  58.128 7.189 58.536 7.765 ;
     RECT  45.168 6.611 46.488 7.813 ;
     RECT  47.52 5.605 47.544 7.813 ;
     RECT  6 7.189 8.112 7.907 ;
     RECT  26.976 6.997 27 7.957 ;
     RECT  28.8 7.621 30.84 7.957 ;
     RECT  76.896 7.861 76.92 7.957 ;
     RECT  78 2.151 78.312 7.957 ;
     RECT  10.944 7.189 10.968 8.003 ;
     RECT  31.92 7.813 31.944 8.003 ;
     RECT  41.616 6.805 41.64 8.003 ;
     RECT  45.024 7.813 46.488 8.003 ;
     RECT  47.52 7.813 47.88 8.003 ;
     RECT  56.016 7.765 58.536 8.051 ;
     RECT  24 6.851 24.312 8.053 ;
     RECT  26.976 7.957 30.84 8.099 ;
     RECT  49.488 7.235 51.768 8.099 ;
     RECT  27.888 8.099 30.84 8.147 ;
     RECT  61.248 7.381 62.712 8.149 ;
     RECT  63.792 7.139 63.816 8.149 ;
     RECT  16.08 6.133 16.536 8.195 ;
     RECT  16.08 8.195 16.344 8.197 ;
     RECT  61.248 8.149 63.816 8.243 ;
     RECT  18.192 7.379 18.912 8.389 ;
     RECT  33.312 7.379 35.112 8.437 ;
     RECT  18.192 8.389 19.032 8.483 ;
     RECT  65.808 7.091 65.832 8.485 ;
     RECT  14.688 7.381 14.76 8.531 ;
     RECT  18.6 8.483 19.032 8.531 ;
     RECT  76.896 7.957 78.312 8.579 ;
     RECT  24 8.053 24.408 8.581 ;
     RECT  33.216 8.437 35.112 8.581 ;
     RECT  53.04 7.381 55.032 8.629 ;
     RECT  58.128 8.051 58.536 8.675 ;
     RECT  63.36 8.243 63.816 8.723 ;
     RECT  33.168 8.581 35.112 8.725 ;
     RECT  28.512 8.147 30.84 8.867 ;
     RECT  33.168 8.725 35.208 8.917 ;
     RECT  6.144 7.907 6.648 8.963 ;
     RECT  64.896 8.485 65.832 8.963 ;
     RECT  32.832 8.917 35.208 8.965 ;
     RECT  45.024 8.003 46.2 9.059 ;
     RECT  42.864 7.475 43.656 9.061 ;
     RECT  52.992 8.629 55.032 9.061 ;
     RECT  32.832 8.965 35.304 9.107 ;
     RECT  36.672 7.621 36.936 9.109 ;
     RECT  47.52 8.003 47.544 9.109 ;
     RECT  71.712 7.427 74.088 9.109 ;
     RECT  36.096 9.109 36.936 9.205 ;
     RECT  38.592 6.467 40.512 9.205 ;
     RECT  45.024 9.059 46.104 9.205 ;
     RECT  49.488 8.099 51.312 9.205 ;
     RECT  52.464 9.061 55.032 9.251 ;
     RECT  47.28 9.109 47.544 9.299 ;
     RECT  15.936 8.197 16.344 9.347 ;
     RECT  36.096 9.205 37.08 9.347 ;
     RECT  44.736 9.205 46.104 9.443 ;
     RECT  49.488 9.205 51.432 9.443 ;
     RECT  14.688 8.531 14.712 9.493 ;
     RECT  24 8.581 24.456 9.493 ;
     RECT  52.464 9.251 53.544 9.539 ;
     RECT  13.2 7.427 13.512 9.541 ;
     RECT  23.76 9.493 24.456 9.541 ;
     RECT  59.808 7.093 59.832 9.541 ;
     RECT  71.712 9.109 74.712 9.589 ;
     RECT  77.472 8.579 78.312 9.589 ;
     RECT  23.76 9.541 24.504 9.635 ;
     RECT  36.912 9.347 37.08 9.637 ;
     RECT  38.592 9.205 40.728 9.637 ;
     RECT  28.512 8.867 30.6 9.731 ;
     RECT  16.32 9.347 16.344 9.781 ;
     RECT  36.912 9.637 40.728 9.781 ;
     RECT  49.488 9.443 51.312 9.829 ;
     RECT  71.712 9.589 75.672 9.829 ;
     RECT  32.832 9.107 35.112 9.877 ;
     RECT  45.024 9.443 46.104 9.923 ;
     RECT  27.216 9.445 27.24 9.971 ;
     RECT  48.96 9.829 51.312 9.971 ;
     RECT  59.808 9.541 60.168 9.973 ;
     RECT  61.248 8.243 62.112 9.973 ;
     RECT  36.912 9.781 41.064 10.019 ;
     RECT  19.968 9.301 19.992 10.021 ;
     RECT  21.168 7.235 21.192 10.021 ;
     RECT  24 9.635 24.504 10.067 ;
     RECT  32.736 9.877 35.112 10.115 ;
     RECT  59.808 9.973 62.112 10.115 ;
     RECT  64.992 8.963 65.832 10.117 ;
     RECT  64.992 10.117 66.072 10.163 ;
     RECT  58.512 8.675 58.536 10.165 ;
     RECT  59.808 10.115 60.168 10.165 ;
     RECT  77.424 9.589 78.312 10.165 ;
     RECT  24 10.067 24.408 10.259 ;
     RECT  66.048 10.163 66.072 10.259 ;
     RECT  25.728 9.925 25.752 10.261 ;
     RECT  14.688 9.493 15.288 10.307 ;
     RECT  42.288 9.061 43.656 10.307 ;
     RECT  33.168 10.115 35.112 10.309 ;
     RECT  42.96 10.307 43.656 10.309 ;
     RECT  19.968 10.021 21.192 10.355 ;
     RECT  22.752 7.765 22.776 10.499 ;
     RECT  64.992 10.163 65.016 10.547 ;
     RECT  15.264 10.307 15.288 10.595 ;
     RECT  2.4 6.851 2.712 10.597 ;
     RECT  47.424 9.299 47.544 10.597 ;
     RECT  33.168 10.309 35.4 10.645 ;
     RECT  70.464 10.021 70.488 10.645 ;
     RECT  47.424 10.597 47.832 10.787 ;
     RECT  70.224 10.645 70.488 10.787 ;
     RECT  67.2 7.427 67.752 10.789 ;
     RECT  68.928 10.453 68.952 10.789 ;
     RECT  71.712 9.829 76.392 10.789 ;
     RECT  77.376 10.165 78.312 10.789 ;
     RECT  36.912 10.019 40.776 10.835 ;
     RECT  58.512 10.165 60.168 10.835 ;
     RECT  70.464 10.787 70.488 10.835 ;
     RECT  45.024 9.923 46.056 10.837 ;
     RECT  16.32 9.781 16.872 10.883 ;
     RECT  71.712 10.789 78.312 10.883 ;
     RECT  33.168 10.645 35.592 10.885 ;
     RECT  36.912 10.835 37.08 10.885 ;
     RECT  19.968 10.355 19.992 10.933 ;
     RECT  6.144 8.963 6.6 10.981 ;
     RECT  18.6 8.531 18.912 10.981 ;
     RECT  19.92 10.933 19.992 10.981 ;
     RECT  33.168 10.885 37.08 11.027 ;
     RECT  44.976 10.837 46.056 11.075 ;
     RECT  71.712 10.883 73.944 11.075 ;
     RECT  38.592 10.835 40.776 11.077 ;
     RECT  25.728 10.261 26.856 11.123 ;
     RECT  58.512 10.835 59.832 11.123 ;
     RECT  67.2 10.789 68.952 11.123 ;
     RECT  75.6 10.883 78.312 11.123 ;
     RECT  31.728 9.637 31.752 11.171 ;
     RECT  76.8 11.123 78.312 11.171 ;
     RECT  28.944 9.731 30.6 11.221 ;
     RECT  78 11.171 78.312 11.221 ;
     RECT  38.592 11.077 41.112 11.267 ;
     RECT  53.472 9.539 53.544 11.269 ;
     RECT  21.168 10.355 21.192 11.365 ;
     RECT  28.752 11.221 30.6 11.365 ;
     RECT  49.488 9.971 51.312 11.365 ;
     RECT  2.4 10.597 3.432 11.411 ;
     RECT  36.912 11.027 37.08 11.411 ;
     RECT  12.528 9.541 13.512 11.459 ;
     RECT  47.52 10.787 47.832 11.557 ;
     RECT  48.864 11.365 51.312 11.557 ;
     RECT  21.072 11.365 21.192 11.603 ;
     RECT  18.6 10.981 19.992 11.605 ;
     RECT  21.072 11.603 21.144 11.605 ;
     RECT  61.248 10.115 62.112 11.605 ;
     RECT  16.32 10.883 16.344 11.699 ;
     RECT  78 11.221 78.408 11.699 ;
     RECT  37.056 11.411 37.08 11.747 ;
     RECT  6.144 10.981 6.744 11.749 ;
     RECT  13.2 11.459 13.512 11.749 ;
     RECT  14.784 11.653 14.808 11.749 ;
     RECT  26.448 11.123 26.856 11.749 ;
     RECT  13.2 11.749 14.808 11.843 ;
     RECT  33.168 11.027 35.592 11.845 ;
     RECT  26.448 11.749 27.336 11.891 ;
     RECT  59.808 11.123 59.832 11.891 ;
     RECT  24 10.259 24.312 11.941 ;
     RECT  53.04 11.269 53.544 11.941 ;
     RECT  75.6 11.123 75.624 11.987 ;
     RECT  42.96 10.309 43.896 11.989 ;
     RECT  47.52 11.557 51.312 12.083 ;
     RECT  28.752 11.365 31.56 12.179 ;
     RECT  33.12 11.845 35.592 12.229 ;
     RECT  38.592 11.267 40.968 12.229 ;
     RECT  71.712 11.075 73.848 12.275 ;
     RECT  45.6 11.075 46.056 12.277 ;
     RECT  38.592 12.229 41.064 12.325 ;
     RECT  42.576 11.989 43.896 12.325 ;
     RECT  55.008 9.251 55.032 12.325 ;
     RECT  42.576 12.325 43.992 12.421 ;
     RECT  18.6 11.605 21.144 12.467 ;
     RECT  33.12 12.229 35.64 12.467 ;
     RECT  47.52 12.083 48.12 12.469 ;
     RECT  58.512 11.123 58.536 12.469 ;
     RECT  45.504 12.277 46.056 12.515 ;
     RECT  26.448 11.891 26.76 12.517 ;
     RECT  78 11.699 78.312 12.517 ;
     RECT  5.664 11.749 6.744 12.563 ;
     RECT  54.912 12.325 55.032 12.613 ;
     RECT  56.016 8.051 56.712 12.613 ;
     RECT  28.752 12.179 31.464 12.661 ;
     RECT  42.576 12.421 44.52 12.707 ;
     RECT  47.184 12.469 48.12 12.707 ;
     RECT  26.208 12.517 26.76 12.709 ;
     RECT  54.912 12.613 57.528 12.709 ;
     RECT  58.512 12.469 59.544 12.709 ;
     RECT  67.2 11.123 68.568 12.805 ;
     RECT  52.32 11.941 53.544 12.851 ;
     RECT  24 11.941 24.456 12.947 ;
     RECT  54.912 12.709 59.544 12.949 ;
     RECT  42.96 12.707 44.52 12.995 ;
     RECT  42.96 12.995 43.368 13.043 ;
     RECT  53.328 12.851 53.544 13.043 ;
     RECT  33.264 12.467 35.64 13.093 ;
     RECT  47.376 12.707 48.12 13.189 ;
     RECT  49.488 12.083 51.312 13.189 ;
     RECT  27.888 12.661 31.464 13.235 ;
     RECT  33.264 13.093 36.12 13.235 ;
     RECT  22.416 11.941 22.44 13.283 ;
     RECT  67.104 12.805 68.568 13.283 ;
     RECT  67.2 13.283 68.568 13.285 ;
     RECT  77.808 12.517 78.312 13.285 ;
     RECT  47.376 13.189 51.312 13.331 ;
     RECT  54.72 12.949 59.544 13.331 ;
     RECT  77.808 13.285 78.408 13.331 ;
     RECT  47.376 13.331 48.12 13.379 ;
     RECT  67.2 13.285 68.712 13.381 ;
     RECT  38.592 12.325 41.304 13.427 ;
     RECT  43.008 13.043 43.368 13.427 ;
     RECT  67.2 13.381 68.76 13.427 ;
     RECT  37.056 13.333 37.08 13.523 ;
     RECT  54.72 13.331 57.528 13.619 ;
     RECT  25.632 12.709 26.76 13.621 ;
     RECT  27.888 13.235 30.552 13.621 ;
     RECT  33.264 13.235 35.304 13.621 ;
     RECT  13.2 11.843 14.424 13.667 ;
     RECT  13.2 13.667 14.04 13.669 ;
     RECT  17.184 12.229 17.208 13.715 ;
     RECT  25.632 13.621 30.552 13.715 ;
     RECT  58.512 13.331 59.544 13.763 ;
     RECT  33.216 13.621 35.304 13.811 ;
     RECT  72.48 12.275 73.848 13.811 ;
     RECT  44.448 12.995 44.52 13.813 ;
     RECT  45.6 12.515 46.056 13.813 ;
     RECT  78 13.331 78.408 13.859 ;
     RECT  44.448 13.813 46.056 13.909 ;
     RECT  43.104 13.427 43.368 13.955 ;
     RECT  54.912 13.619 57.048 14.003 ;
     RECT  38.592 13.427 41.16 14.051 ;
     RECT  61.248 11.605 62.76 14.053 ;
     RECT  63.792 8.723 63.816 14.053 ;
     RECT  61.248 14.053 63.816 14.101 ;
     RECT  64.8 12.661 64.824 14.101 ;
     RECT  44.448 13.909 46.152 14.195 ;
     RECT  61.248 14.101 64.824 14.195 ;
     RECT  75.12 13.381 75.144 14.197 ;
     RECT  43.344 13.955 43.368 14.245 ;
     RECT  44.448 14.195 46.008 14.245 ;
     RECT  28.512 13.715 30.552 14.291 ;
     RECT  54.912 14.003 57 14.291 ;
     RECT  24 12.947 24.408 14.293 ;
     RECT  25.632 13.715 27.144 14.293 ;
     RECT  49.488 13.331 51.312 14.293 ;
     RECT  61.248 14.195 62.112 14.389 ;
     RECT  67.2 13.427 67.512 14.437 ;
     RECT  33.312 13.811 35.304 14.485 ;
     RECT  72.6 13.811 73.848 14.485 ;
     RECT  75.12 14.197 75.288 14.485 ;
     RECT  66.672 14.437 67.512 14.579 ;
     RECT  28.704 14.291 30.552 14.627 ;
     RECT  18.6 12.467 21.048 14.677 ;
     RECT  33.312 14.485 35.688 14.723 ;
     RECT  55.056 14.291 57 14.867 ;
     RECT  72.6 14.485 75.288 14.867 ;
     RECT  47.52 13.379 48.12 14.917 ;
     RECT  49.44 14.293 51.312 14.917 ;
     RECT  12.528 13.669 14.04 14.963 ;
     RECT  28.752 14.627 30.552 14.963 ;
     RECT  55.056 14.867 56.712 15.107 ;
     RECT  47.52 14.917 51.312 15.109 ;
     RECT  52.32 12.851 52.344 15.109 ;
     RECT  43.344 14.245 46.008 15.251 ;
     RECT  47.52 15.109 52.344 15.299 ;
     RECT  2.4 11.411 2.712 15.301 ;
     RECT  63.216 14.195 64.824 15.347 ;
     RECT  18.6 14.677 21.24 15.395 ;
     RECT  49.104 15.299 52.344 15.397 ;
     RECT  53.328 13.043 53.352 15.397 ;
     RECT  18.6 15.395 20.52 15.493 ;
     RECT  38.592 14.051 41.064 15.541 ;
     RECT  68.688 13.427 68.76 15.589 ;
     RECT  18.192 15.493 20.52 15.827 ;
     RECT  38.592 15.541 41.16 15.827 ;
     RECT  49.104 15.397 53.352 15.875 ;
     RECT  42.288 15.685 42.312 15.923 ;
     RECT  2.4 15.301 2.904 16.019 ;
     RECT  4.416 11.125 4.44 16.019 ;
     RECT  61.008 14.389 62.112 16.067 ;
     RECT  45.6 15.251 46.008 16.069 ;
     RECT  56.112 15.107 56.712 16.165 ;
     RECT  24 14.293 27.144 16.259 ;
     RECT  18.24 15.827 20.52 16.307 ;
     RECT  56.112 16.165 56.808 16.307 ;
     RECT  36.96 15.925 37.08 16.309 ;
     RECT  21.84 16.021 21.864 16.357 ;
     RECT  45.6 16.069 46.248 16.405 ;
     RECT  58.512 13.763 58.872 16.405 ;
     RECT  28.752 14.963 30.408 16.451 ;
     RECT  38.592 15.827 41.064 16.451 ;
     RECT  20.016 16.307 20.52 16.499 ;
     RECT  21.84 16.357 22.344 16.499 ;
     RECT  24 16.259 25.176 16.549 ;
     RECT  16.128 15.925 16.152 16.595 ;
     RECT  72.6 14.867 74.664 16.595 ;
     RECT  4.32 16.117 4.344 16.645 ;
     RECT  3.984 16.645 4.344 16.691 ;
     RECT  36.96 16.309 37.464 16.693 ;
     RECT  63.216 15.347 64.632 16.787 ;
     RECT  43.344 15.251 44.568 16.789 ;
     RECT  45.6 16.405 46.344 16.789 ;
     RECT  47.52 15.299 48.12 16.789 ;
     RECT  49.104 15.875 52.344 16.789 ;
     RECT  33.312 14.723 35.592 16.835 ;
     RECT  33.312 16.835 33.672 16.837 ;
     RECT  23.232 16.549 25.176 16.883 ;
     RECT  20.4 16.499 20.52 16.885 ;
     RECT  21.84 16.499 21.864 16.885 ;
     RECT  23.232 16.883 25.08 16.931 ;
     RECT  13.104 14.963 14.04 16.981 ;
     RECT  18.24 16.307 18.912 17.027 ;
     RECT  63.504 16.787 64.632 17.027 ;
     RECT  7.8 7.907 8.112 17.029 ;
     RECT  34.8 16.835 35.592 17.029 ;
     RECT  36.96 16.693 37.512 17.029 ;
     RECT  13.104 16.981 14.808 17.077 ;
     RECT  47.52 16.789 52.344 17.077 ;
     RECT  53.328 15.875 53.352 17.077 ;
     RECT  63.936 17.027 64.632 17.077 ;
     RECT  68.688 15.589 68.952 17.077 ;
     RECT  23.232 16.931 24.984 17.123 ;
     RECT  20.4 16.885 21.864 17.171 ;
     RECT  23.232 17.123 24.312 17.171 ;
     RECT  38.592 16.451 41.016 17.171 ;
     RECT  42.096 17.125 42.12 17.173 ;
     RECT  43.344 16.789 46.344 17.173 ;
     RECT  13.056 17.077 14.808 17.219 ;
     RECT  33.264 16.837 33.672 17.221 ;
     RECT  20.4 17.171 21.576 17.267 ;
     RECT  42.096 17.173 46.344 17.267 ;
     RECT  6.096 12.563 6.744 17.269 ;
     RECT  7.8 17.029 8.232 17.269 ;
     RECT  34.8 17.029 37.512 17.315 ;
     RECT  42.096 17.267 46.056 17.315 ;
     RECT  43.2 17.315 44.184 17.363 ;
     RECT  63.936 17.077 65.592 17.363 ;
     RECT  70.656 15.829 70.68 17.363 ;
     RECT  33.072 17.221 33.672 17.411 ;
     RECT  13.2 17.219 14.808 17.413 ;
     RECT  60.384 16.213 60.408 17.413 ;
     RECT  61.8 16.067 62.112 17.413 ;
     RECT  39.312 17.171 41.016 17.459 ;
     RECT  42.096 17.315 42.12 17.603 ;
     RECT  60.384 17.413 62.112 17.603 ;
     RECT  47.52 17.077 53.352 17.605 ;
     RECT  37.248 17.315 37.512 17.651 ;
     RECT  43.2 17.363 43.944 17.651 ;
     RECT  47.52 17.605 53.4 17.651 ;
     RECT  58.512 16.405 59.4 17.651 ;
     RECT  64.56 17.363 65.592 17.651 ;
     RECT  68.688 17.077 69.576 17.699 ;
     RECT  6.096 17.269 8.232 17.747 ;
     RECT  20.4 17.267 21.48 17.795 ;
     RECT  28.752 16.451 30.312 17.843 ;
     RECT  58.512 17.651 58.968 17.891 ;
     RECT  61.8 17.603 62.112 18.085 ;
     RECT  64.608 17.651 65.592 18.131 ;
     RECT  28.992 17.843 30.312 18.179 ;
     RECT  34.8 17.315 36.12 18.179 ;
     RECT  2.4 16.019 2.712 18.181 ;
     RECT  13.2 17.413 15.288 18.181 ;
     RECT  26.736 16.259 27.144 18.181 ;
     RECT  67.2 14.579 67.512 18.181 ;
     RECT  72.6 16.595 74.424 18.181 ;
     RECT  20.4 17.795 20.424 18.227 ;
     RECT  43.92 17.651 43.944 18.227 ;
     RECT  45.6 17.315 46.056 18.227 ;
     RECT  56.112 16.307 56.712 18.229 ;
     RECT  34.8 18.179 35.304 18.371 ;
     RECT  47.52 17.651 51.312 18.371 ;
     RECT  52.32 17.651 53.4 18.371 ;
     RECT  68.688 17.699 68.952 18.371 ;
     RECT  28.992 18.179 29.832 18.467 ;
     RECT  56.112 18.229 56.952 18.467 ;
     RECT  47.52 18.371 48.168 18.563 ;
     RECT  18.6 17.027 18.912 18.565 ;
     RECT  39.312 17.459 40.512 18.613 ;
     RECT  66.672 18.181 67.512 18.709 ;
     RECT  68.688 18.371 68.856 18.709 ;
     RECT  29.088 18.467 29.832 18.755 ;
     RECT  17.664 18.565 18.912 18.805 ;
     RECT  13.2 18.181 15.384 18.851 ;
     RECT  55.056 15.107 55.08 18.949 ;
     RECT  14.784 18.851 15.384 18.995 ;
     RECT  61.8 18.085 62.904 18.995 ;
     RECT  45.6 18.227 45.912 19.045 ;
     RECT  37.44 17.651 37.512 19.091 ;
     RECT  78 13.859 78.312 19.093 ;
     RECT  15.36 18.995 15.384 19.235 ;
     RECT  26.736 18.181 27.384 19.283 ;
     RECT  54.432 18.949 55.08 19.333 ;
     RECT  56.112 18.467 56.712 19.333 ;
     RECT  22.8 17.989 22.824 19.427 ;
     RECT  37.488 19.091 37.512 19.427 ;
     RECT  66.672 18.709 68.856 19.475 ;
     RECT  33.648 17.411 33.672 19.523 ;
     RECT  77.904 19.093 78.312 19.573 ;
     RECT  54.432 19.333 56.712 19.667 ;
     RECT  3.984 16.691 4.008 19.715 ;
     RECT  47.52 18.563 47.88 19.811 ;
     RECT  39.216 18.613 40.512 19.909 ;
     RECT  54.432 19.667 55.176 19.955 ;
     RECT  45.216 19.045 45.912 19.957 ;
     RECT  54.432 19.955 55.08 20.003 ;
     RECT  66.672 19.475 67.512 20.003 ;
     RECT  77.904 19.573 78.408 20.101 ;
     RECT  77.808 20.101 78.408 20.147 ;
     RECT  44.352 19.957 45.912 20.149 ;
     RECT  47.52 19.811 47.544 20.149 ;
     RECT  13.2 18.851 13.608 20.195 ;
     RECT  7.8 17.747 8.232 20.197 ;
     RECT  68.832 19.475 68.856 20.197 ;
     RECT  49.488 18.371 51.312 20.245 ;
     RECT  52.32 18.371 52.92 20.245 ;
     RECT  49.488 20.245 52.92 20.291 ;
     RECT  7.8 20.197 8.616 20.339 ;
     RECT  24 17.171 24.312 20.485 ;
     RECT  16.8 18.805 18.912 20.581 ;
     RECT  55.056 20.003 55.08 20.675 ;
     RECT  65.568 18.131 65.592 20.677 ;
     RECT  68.832 20.197 69.576 20.723 ;
     RECT  72.6 18.181 75.192 20.725 ;
     RECT  2.304 18.181 2.712 20.819 ;
     RECT  65.568 20.677 65.736 20.819 ;
     RECT  58.512 17.891 58.536 20.965 ;
     RECT  58.176 20.965 58.536 21.011 ;
     RECT  77.808 20.147 78.312 21.011 ;
     RECT  34.8 18.371 35.112 21.013 ;
     RECT  67.2 20.003 67.512 21.061 ;
     RECT  16.176 20.581 18.912 21.155 ;
     RECT  30.816 20.485 30.84 21.155 ;
     RECT  44.352 20.149 47.544 21.155 ;
     RECT  69.552 20.723 69.576 21.155 ;
     RECT  45.216 21.155 47.544 21.299 ;
     RECT  38.88 19.909 40.512 21.443 ;
     RECT  29.28 18.755 29.832 21.493 ;
     RECT  7.8 20.339 8.232 21.635 ;
     RECT  27.36 19.283 27.384 21.635 ;
     RECT  39.744 21.443 40.512 21.635 ;
     RECT  47.52 21.299 47.544 21.637 ;
     RECT  33.792 20.725 33.816 21.683 ;
     RECT  49.488 20.291 52.728 21.683 ;
     RECT  71.808 20.725 75.192 21.683 ;
     RECT  34.8 21.013 35.976 21.733 ;
     RECT  29.28 21.493 29.88 21.971 ;
     RECT  47.52 21.637 48.504 21.971 ;
     RECT  34.8 21.733 36.072 21.973 ;
     RECT  34.704 21.973 36.072 22.019 ;
     RECT  37.488 21.781 37.512 22.019 ;
     RECT  23.904 20.485 24.312 22.069 ;
     RECT  67.2 21.061 67.848 22.163 ;
     RECT  16.176 21.155 16.824 22.165 ;
     RECT  29.4 21.971 29.88 22.165 ;
     RECT  56.4 19.667 56.712 22.165 ;
     RECT  58.176 21.011 58.2 22.165 ;
     RECT  65.712 20.819 65.736 22.165 ;
     RECT  78 21.011 78.312 22.165 ;
     RECT  34.704 22.019 35.976 22.211 ;
     RECT  23.904 22.069 24.84 22.261 ;
     RECT  48.48 21.971 48.504 22.261 ;
     RECT  49.488 21.683 51.312 22.261 ;
     RECT  78 22.165 78.408 22.261 ;
     RECT  48.48 22.261 51.312 22.451 ;
     RECT  23.904 22.261 24.936 22.499 ;
     RECT  26.784 22.405 26.808 22.691 ;
     RECT  31.968 22.549 31.992 22.691 ;
     RECT  29.4 22.165 29.976 22.693 ;
     RECT  49.056 22.451 51.312 22.739 ;
     RECT  18.6 21.155 18.912 22.741 ;
     RECT  65.712 22.165 66.216 22.789 ;
     RECT  29.4 22.693 30.168 22.835 ;
     RECT  71.904 21.683 75.192 22.931 ;
     RECT  23.904 22.499 24.84 22.979 ;
     RECT  15.984 22.165 16.824 23.029 ;
     RECT  52.704 21.683 52.728 23.029 ;
     RECT  18.6 22.741 19.8 23.075 ;
     RECT  32.784 23.029 32.808 23.171 ;
     RECT  21.456 17.795 21.48 23.317 ;
     RECT  15.984 23.029 17.16 23.509 ;
     RECT  15.6 23.509 17.16 23.651 ;
     RECT  68.832 22.645 68.856 23.651 ;
     RECT  41.568 22.741 41.592 23.749 ;
     RECT  56.4 22.165 58.2 23.795 ;
     RECT  64.992 22.789 66.216 23.797 ;
     RECT  45.216 21.299 45.912 23.845 ;
     RECT  41.568 23.749 42.072 23.939 ;
     RECT  58.176 23.795 58.2 23.987 ;
     RECT  71.232 23.029 71.256 23.987 ;
     RECT  26.736 23.269 26.76 24.035 ;
     RECT  41.568 23.939 41.592 24.035 ;
     RECT  52.704 23.029 53.064 24.083 ;
     RECT  23.904 22.979 24.312 24.277 ;
     RECT  29.4 22.835 30.12 24.371 ;
     RECT  78 22.261 78.456 24.515 ;
     RECT  52.704 24.083 52.728 24.517 ;
     RECT  52.464 24.517 52.728 24.563 ;
     RECT  56.4 23.795 56.808 24.563 ;
     RECT  21.456 23.317 22.248 24.565 ;
     RECT  23.616 24.277 24.312 24.565 ;
     RECT  21.456 24.565 24.312 24.611 ;
     RECT  72.6 22.931 75.192 24.659 ;
     RECT  60.384 17.603 60.408 24.709 ;
     RECT  54.096 23.845 54.12 24.755 ;
     RECT  45.216 23.845 46.296 24.899 ;
     RECT  76.8 11.171 76.824 24.901 ;
     RECT  78 24.515 78.312 24.901 ;
     RECT  11.472 23.317 11.496 25.091 ;
     RECT  4.896 23.317 4.92 25.139 ;
     RECT  64.896 23.797 66.216 25.235 ;
     RECT  61.8 18.995 62.112 25.285 ;
     RECT  45.216 24.899 45.912 25.333 ;
     RECT  22.752 24.611 24.312 25.429 ;
     RECT  44.736 25.333 45.912 25.429 ;
     RECT  7.8 21.635 8.112 25.573 ;
     RECT  22.752 25.429 24.408 25.573 ;
     RECT  70.704 25.045 70.728 25.573 ;
     RECT  22.608 25.573 24.408 25.619 ;
     RECT  13.2 20.195 13.512 25.621 ;
     RECT  72.6 24.659 74.52 25.621 ;
     RECT  23.616 25.619 24.408 25.669 ;
     RECT  61.584 25.285 62.112 25.715 ;
     RECT  76.8 24.901 78.312 25.715 ;
     RECT  52.464 24.563 52.488 26.003 ;
     RECT  23.616 25.669 25.176 26.051 ;
     RECT  31.2 25.717 31.224 26.051 ;
     RECT  54.912 25.621 54.936 26.053 ;
     RECT  56.4 24.563 56.712 26.197 ;
     RECT  59.616 24.709 60.408 26.243 ;
     RECT  65.712 25.235 66.216 26.243 ;
     RECT  54.72 26.053 54.936 26.293 ;
     RECT  54 26.293 54.936 26.435 ;
     RECT  38.784 24.805 38.808 26.483 ;
     RECT  72.6 25.621 74.664 26.531 ;
     RECT  43.92 25.429 45.912 26.677 ;
     RECT  7.8 25.573 9.096 26.819 ;
     RECT  13.056 25.621 13.512 26.819 ;
     RECT  16.176 23.651 17.16 26.821 ;
     RECT  54.912 26.435 54.936 26.867 ;
     RECT  26.88 26.293 26.904 26.915 ;
     RECT  63.84 26.197 63.864 26.915 ;
     RECT  48.48 26.485 48.504 26.917 ;
     RECT  49.488 22.739 51.312 26.917 ;
     RECT  48.48 26.917 51.312 27.107 ;
     RECT  43.92 26.677 46.056 27.155 ;
     RECT  56.4 26.197 57.144 27.203 ;
     RECT  72.6 26.531 74.472 27.299 ;
     RECT  22.608 25.619 22.632 27.395 ;
     RECT  48.48 27.107 48.504 27.395 ;
     RECT  23.616 26.051 24.792 27.397 ;
     RECT  6.096 17.747 6.744 27.493 ;
     RECT  7.8 26.819 8.112 27.493 ;
     RECT  29.4 24.371 29.712 27.589 ;
     RECT  67.2 22.163 67.512 27.589 ;
     RECT  15.312 26.821 17.16 27.635 ;
     RECT  66.192 26.243 66.216 27.635 ;
     RECT  23.616 27.397 24.888 27.683 ;
     RECT  43.92 27.155 44.472 27.683 ;
     RECT  78 25.715 78.312 27.877 ;
     RECT  70.704 25.573 70.824 27.923 ;
     RECT  38.928 27.829 38.952 27.925 ;
     RECT  59.952 26.243 60.408 27.971 ;
     RECT  40.2 21.635 40.512 27.973 ;
     RECT  34.8 22.211 35.976 28.261 ;
     RECT  67.2 27.589 67.608 28.261 ;
     RECT  38.64 27.925 38.952 28.307 ;
     RECT  44.016 27.683 44.472 28.355 ;
     RECT  21.456 24.611 21.48 28.357 ;
     RECT  38.928 28.307 38.952 28.357 ;
     RECT  39.936 27.973 40.512 28.357 ;
     RECT  21.36 28.357 21.48 28.403 ;
     RECT  27.888 25.621 27.912 28.405 ;
     RECT  44.448 28.355 44.472 28.405 ;
     RECT  45.456 27.155 46.056 28.405 ;
     RECT  61.8 25.715 62.112 28.405 ;
     RECT  13.2 26.819 13.512 28.453 ;
     RECT  69.408 27.301 69.432 28.453 ;
     RECT  70.704 27.923 70.728 28.453 ;
     RECT  15.744 27.635 17.16 28.547 ;
     RECT  27.888 28.405 28.008 28.547 ;
     RECT  34.704 28.261 35.976 28.547 ;
     RECT  61.584 28.405 62.112 28.547 ;
     RECT  69.408 28.453 70.728 28.547 ;
     RECT  38.928 28.357 40.512 28.691 ;
     RECT  6.096 27.493 8.112 28.741 ;
     RECT  16.08 28.547 17.16 28.835 ;
     RECT  49.488 27.107 51.312 28.837 ;
     RECT  72.6 27.299 73.848 28.885 ;
     RECT  39.216 28.691 40.512 28.931 ;
     RECT  56.4 27.203 56.712 28.981 ;
     RECT  64.224 28.453 64.248 28.981 ;
     RECT  64.224 28.981 64.44 29.027 ;
     RECT  23.616 27.683 24.312 29.029 ;
     RECT  34.704 28.547 35.112 29.075 ;
     RECT  53.52 28.933 53.544 29.075 ;
     RECT  16.176 28.835 17.16 29.123 ;
     RECT  54.72 28.453 54.744 29.123 ;
     RECT  16.752 29.123 17.16 29.267 ;
     RECT  23.616 29.029 24.456 29.267 ;
     RECT  29.28 27.589 29.712 29.269 ;
     RECT  78 27.877 78.456 29.269 ;
     RECT  44.448 28.405 46.056 29.315 ;
     RECT  72 28.885 73.848 29.461 ;
     RECT  29.088 29.269 29.712 29.555 ;
     RECT  12.72 28.453 13.704 29.603 ;
     RECT  49.488 28.837 51.96 29.651 ;
     RECT  69.408 28.547 70.152 29.699 ;
     RECT  27.936 28.547 28.008 29.747 ;
     RECT  36.816 29.029 36.84 29.797 ;
     RECT  5.76 28.741 8.112 29.845 ;
     RECT  13.2 29.603 13.704 29.891 ;
     RECT  36.816 29.797 37.464 30.035 ;
     RECT  5.76 29.845 9.096 30.131 ;
     RECT  48.096 28.981 48.12 30.133 ;
     RECT  56.304 28.981 56.712 30.181 ;
     RECT  67.2 28.261 68.424 30.229 ;
     RECT  76.8 25.715 76.824 30.275 ;
     RECT  21.36 28.403 21.384 30.373 ;
     RECT  34.8 29.075 35.112 30.421 ;
     RECT  76.464 30.325 76.488 30.421 ;
     RECT  64.416 29.027 64.44 30.469 ;
     RECT  78 29.269 78.552 30.469 ;
     RECT  63.888 30.469 64.44 30.515 ;
     RECT  48.048 30.133 48.12 30.565 ;
     RECT  49.488 29.651 51.312 30.565 ;
     RECT  66.24 30.229 68.424 30.613 ;
     RECT  44.448 29.315 45.912 30.661 ;
     RECT  43.92 30.661 45.912 30.707 ;
     RECT  55.872 30.181 57 30.709 ;
     RECT  72 29.461 74.712 30.709 ;
     RECT  76.368 30.421 76.488 30.709 ;
     RECT  11.712 30.181 11.736 30.803 ;
     RECT  24 29.267 24.456 30.803 ;
     RECT  65.52 30.613 68.424 30.803 ;
     RECT  65.52 30.803 67.512 30.805 ;
     RECT  65.184 30.805 67.512 30.851 ;
     RECT  40.2 28.931 40.512 31.093 ;
     RECT  37.344 30.035 37.464 31.139 ;
     RECT  39.792 31.093 40.512 31.283 ;
     RECT  18.6 23.075 18.912 31.285 ;
     RECT  59.952 27.971 60.168 31.285 ;
     RECT  55.632 30.709 57 31.379 ;
     RECT  63.888 30.515 63.912 31.379 ;
     RECT  66.24 30.851 67.512 31.379 ;
     RECT  72 30.709 74.904 31.379 ;
     RECT  77.472 30.469 78.552 31.379 ;
     RECT  27.936 29.747 27.96 31.427 ;
     RECT  48.048 30.565 51.312 31.619 ;
     RECT  76.176 30.709 76.488 31.621 ;
     RECT  25.344 31.381 25.368 31.763 ;
     RECT  42.432 31.621 42.456 31.763 ;
     RECT  26.736 31.573 26.76 31.955 ;
     RECT  55.872 31.379 57 31.955 ;
     RECT  59.088 31.285 60.168 31.955 ;
     RECT  43.92 30.707 43.944 32.003 ;
     RECT  72 31.379 74.712 32.003 ;
     RECT  75.744 31.621 76.488 32.005 ;
     RECT  37.44 31.139 37.464 32.051 ;
     RECT  18.6 31.285 19.272 32.195 ;
     RECT  52.464 30.757 52.488 32.195 ;
     RECT  72 32.003 73.464 32.195 ;
     RECT  47.04 32.005 47.064 32.291 ;
     RECT  17.136 29.267 17.16 32.485 ;
     RECT  18.6 32.195 18.912 32.485 ;
     RECT  75.744 32.005 76.68 32.531 ;
     RECT  10.896 31.861 10.92 32.579 ;
     RECT  40.2 31.283 40.512 32.629 ;
     RECT  76.368 32.531 76.68 32.773 ;
     RECT  70.752 31.861 70.776 32.965 ;
     RECT  70.656 32.965 70.776 33.011 ;
     RECT  20.832 30.373 21.384 33.013 ;
     RECT  40.2 32.629 41.016 33.013 ;
     RECT  45.456 30.707 45.912 33.107 ;
     RECT  70.656 33.011 70.68 33.107 ;
     RECT  76.368 32.773 76.92 33.107 ;
     RECT  5.904 30.131 9.096 33.205 ;
     RECT  4.176 28.501 4.2 33.253 ;
     RECT  5.904 33.205 9.24 33.253 ;
     RECT  40.2 33.013 41.064 33.301 ;
     RECT  59.952 31.955 60.168 33.301 ;
     RECT  4.176 33.253 9.24 33.347 ;
     RECT  4.176 33.347 9.096 33.395 ;
     RECT  17.136 32.485 18.912 33.397 ;
     RECT  20.544 33.013 21.384 33.397 ;
     RECT  22.848 33.013 22.872 33.493 ;
     RECT  24 30.803 24.312 33.493 ;
     RECT  55.872 31.955 56.712 33.589 ;
     RECT  43.68 32.485 43.704 33.731 ;
     RECT  15.936 32.437 15.96 33.779 ;
     RECT  34.8 30.421 35.208 33.973 ;
     RECT  26.688 33.445 26.712 34.115 ;
     RECT  72 32.195 72.912 34.117 ;
     RECT  40.08 33.301 41.064 34.259 ;
     RECT  75.792 33.541 75.816 34.259 ;
     RECT  76.896 33.107 76.92 34.307 ;
     RECT  5.904 33.395 9.096 34.451 ;
     RECT  48.96 31.619 51.312 34.499 ;
     RECT  49.488 34.499 51.312 34.501 ;
     RECT  22.848 33.493 24.312 34.741 ;
     RECT  55.44 33.589 56.712 34.787 ;
     RECT  17.136 33.397 21.384 34.979 ;
     RECT  59.952 33.301 60.408 34.979 ;
     RECT  45.6 33.107 45.912 34.981 ;
     RECT  78 31.379 78.552 34.981 ;
     RECT  31.728 33.061 31.752 35.315 ;
     RECT  45.12 34.981 45.912 35.315 ;
     RECT  22.8 34.741 24.312 35.317 ;
     RECT  20.352 34.979 21.384 35.459 ;
     RECT  65.184 30.851 65.208 35.509 ;
     RECT  77.904 34.981 78.552 35.555 ;
     RECT  29.4 29.555 29.712 35.557 ;
     RECT  49.488 34.501 51.432 35.603 ;
     RECT  17.136 34.979 18.912 35.699 ;
     RECT  61.8 28.547 62.112 35.701 ;
     RECT  13.2 29.891 13.512 35.845 ;
     RECT  14.496 30.901 14.52 35.845 ;
     RECT  49.488 35.603 51.312 35.939 ;
     RECT  54.432 35.797 54.456 35.939 ;
     RECT  71.232 34.117 72.912 35.939 ;
     RECT  22.8 35.317 25.128 35.987 ;
     RECT  49.488 35.939 49.752 36.037 ;
     RECT  44.16 35.893 44.184 36.083 ;
     RECT  5.904 34.451 9 36.133 ;
     RECT  38.784 35.845 38.808 36.277 ;
     RECT  38.016 36.277 39 36.325 ;
     RECT  40.08 34.259 40.512 36.325 ;
     RECT  49.104 36.037 49.752 36.325 ;
     RECT  22.8 35.987 24.408 36.467 ;
     RECT  74.688 32.003 74.712 36.469 ;
     RECT  32.064 35.893 32.136 36.515 ;
     RECT  61.8 35.701 62.232 36.515 ;
     RECT  64.416 35.509 65.208 36.515 ;
     RECT  55.872 34.787 56.712 36.613 ;
     RECT  38.016 36.325 40.512 36.659 ;
     RECT  47.184 36.565 47.208 36.707 ;
     RECT  50.736 35.939 51.312 36.709 ;
     RECT  45.216 35.315 45.912 36.757 ;
     RECT  10.512 35.893 10.536 36.803 ;
     RECT  15.696 34.789 15.72 36.803 ;
     RECT  32.112 36.515 32.136 36.803 ;
     RECT  61.8 36.515 62.112 36.805 ;
     RECT  13.2 35.845 14.52 36.853 ;
     RECT  22.8 36.467 22.824 36.995 ;
     RECT  25.44 36.853 25.464 36.995 ;
     RECT  50.736 36.709 51.816 36.995 ;
     RECT  28.56 35.557 29.712 36.997 ;
     RECT  38.016 36.659 39 37.043 ;
     RECT  51 36.995 51.816 37.043 ;
     RECT  74.208 36.469 74.712 37.043 ;
     RECT  26.592 35.029 26.616 37.045 ;
     RECT  5.712 36.133 9 37.091 ;
     RECT  26.592 37.045 26.808 37.091 ;
     RECT  65.184 36.515 65.208 37.141 ;
     RECT  69.168 32.197 69.192 37.141 ;
     RECT  38.976 37.043 39 37.187 ;
     RECT  58.656 36.421 58.68 37.187 ;
     RECT  54.048 35.941 54.072 37.189 ;
     RECT  43.44 36.565 43.512 37.285 ;
     RECT  54.048 37.189 54.456 37.285 ;
     RECT  45.216 36.757 46.584 37.331 ;
     RECT  24 36.467 24.408 37.333 ;
     RECT  53.616 37.285 54.456 37.427 ;
     RECT  48.384 36.325 49.752 37.475 ;
     RECT  42.864 37.285 43.512 37.523 ;
     RECT  48.768 37.475 49.752 37.523 ;
     RECT  30.816 35.989 30.84 37.573 ;
     RECT  53.616 37.427 54.36 37.573 ;
     RECT  55.776 36.613 56.712 37.573 ;
     RECT  69.12 37.141 69.192 37.573 ;
     RECT  30.816 37.573 31.32 37.619 ;
     RECT  55.776 37.573 57.384 37.765 ;
     RECT  68.88 37.573 69.192 37.811 ;
     RECT  37.008 37.765 37.032 37.907 ;
     RECT  67.2 31.379 67.512 37.957 ;
     RECT  52.992 37.573 54.36 38.051 ;
     RECT  40.2 36.659 40.512 38.101 ;
     RECT  59.952 34.979 60.168 38.101 ;
     RECT  2.4 20.819 2.712 38.149 ;
     RECT  6.096 37.091 9 38.149 ;
     RECT  72 35.939 72.912 38.149 ;
     RECT  74.688 37.043 74.712 38.291 ;
     RECT  31.296 37.619 31.32 38.387 ;
     RECT  61.68 36.805 62.112 38.435 ;
     RECT  34.8 33.973 35.304 38.531 ;
     RECT  67.2 37.957 67.608 38.579 ;
     RECT  20.832 35.459 21.384 38.629 ;
     RECT  49.488 37.523 49.752 38.629 ;
     RECT  24 37.333 24.696 38.675 ;
     RECT  65.184 37.141 66.168 38.675 ;
     RECT  11.424 38.149 11.448 38.725 ;
     RECT  13.104 36.853 14.52 38.725 ;
     RECT  55.488 37.765 57.384 38.771 ;
     RECT  51 37.043 51.312 38.773 ;
     RECT  11.424 38.725 14.52 38.819 ;
     RECT  48.96 38.629 49.752 39.011 ;
     RECT  55.488 38.771 56.712 39.059 ;
     RECT  51 38.773 52.008 39.157 ;
     RECT  5.232 38.149 9 39.203 ;
     RECT  28.128 36.997 29.712 39.205 ;
     RECT  71.232 38.149 72.912 39.301 ;
     RECT  28.128 39.205 30.408 39.395 ;
     RECT  20.832 38.629 21.48 39.491 ;
     RECT  2.4 38.149 3.048 39.493 ;
     RECT  39.504 38.101 40.512 39.493 ;
     RECT  50.88 39.157 52.008 39.493 ;
     RECT  52.992 38.051 54.12 39.493 ;
     RECT  78 35.555 78.552 39.589 ;
     RECT  39.504 39.493 40.872 39.635 ;
     RECT  16.08 38.581 16.104 39.683 ;
     RECT  43.056 37.523 43.512 39.731 ;
     RECT  61.8 38.435 62.112 39.781 ;
     RECT  36.144 39.253 36.168 39.827 ;
     RECT  71.232 39.301 73.032 39.829 ;
     RECT  14.496 38.819 14.52 39.877 ;
     RECT  26.784 37.091 26.808 39.923 ;
     RECT  45.216 37.331 46.008 39.923 ;
     RECT  59.904 38.101 60.168 39.923 ;
     RECT  71.232 39.829 73.08 39.923 ;
     RECT  72 39.923 73.08 39.971 ;
     RECT  45.6 39.923 46.008 39.973 ;
     RECT  48.432 39.301 48.456 40.019 ;
     RECT  50.88 39.493 54.12 40.019 ;
     RECT  32.64 39.349 32.664 40.067 ;
     RECT  52.8 40.019 54.12 40.163 ;
     RECT  64.992 40.117 65.016 40.165 ;
     RECT  66.144 38.675 66.168 40.165 ;
     RECT  64.992 40.165 66.168 40.259 ;
     RECT  65.28 40.259 66.168 40.261 ;
     RECT  67.2 38.579 67.512 40.261 ;
     RECT  65.28 40.261 67.512 40.307 ;
     RECT  76.512 39.061 76.536 40.307 ;
     RECT  11.424 38.819 13.512 40.499 ;
     RECT  45.6 39.973 46.776 40.547 ;
     RECT  55.296 39.301 55.32 40.547 ;
     RECT  59.952 39.923 60.168 40.595 ;
     RECT  72 39.971 73.032 40.595 ;
     RECT  50.88 40.019 51.312 40.645 ;
     RECT  14.496 39.877 14.904 40.739 ;
     RECT  36.624 39.877 36.648 40.739 ;
     RECT  61.8 39.781 62.76 40.835 ;
     RECT  65.28 40.307 65.304 40.835 ;
     RECT  77.52 39.589 78.552 40.835 ;
     RECT  43.056 39.731 43.08 40.837 ;
     RECT  42.96 40.837 43.08 40.883 ;
     RECT  56.4 39.059 56.712 40.885 ;
     RECT  37.632 39.733 37.656 40.979 ;
     RECT  26.736 40.837 26.76 41.027 ;
     RECT  5.472 39.203 9 41.029 ;
     RECT  12.384 40.499 13.512 41.075 ;
     RECT  20.832 39.491 21.384 41.123 ;
     RECT  5.472 41.029 9.384 41.125 ;
     RECT  39.504 39.635 40.512 41.221 ;
     RECT  47.808 41.029 47.832 41.267 ;
     RECT  50.784 40.645 51.312 41.267 ;
     RECT  52.8 40.163 53.016 41.269 ;
     RECT  54.096 40.163 54.12 41.269 ;
     RECT  45.6 40.547 46.536 41.411 ;
     RECT  56.304 40.885 56.712 41.411 ;
     RECT  66.288 40.307 67.512 41.413 ;
     RECT  39.36 41.221 40.512 41.605 ;
     RECT  72 40.595 72.912 41.605 ;
     RECT  49.488 39.011 49.752 41.651 ;
     RECT  52.8 41.269 54.12 41.651 ;
     RECT  24 38.675 24.504 41.653 ;
     RECT  39.36 41.605 41.016 41.747 ;
     RECT  17.136 35.699 17.352 41.797 ;
     RECT  5.472 41.125 9.672 41.987 ;
     RECT  24 41.653 25.128 42.035 ;
     RECT  12.48 41.075 13.512 42.037 ;
     RECT  14.496 40.739 14.52 42.037 ;
     RECT  59.952 40.595 59.976 42.085 ;
     RECT  12.48 42.037 14.52 42.133 ;
     RECT  16.752 41.797 17.352 42.179 ;
     RECT  5.472 41.987 9.384 42.227 ;
     RECT  42.96 40.883 42.984 42.227 ;
     RECT  49.488 41.651 49.704 42.227 ;
     RECT  52.8 41.651 53.448 42.227 ;
     RECT  59.952 42.085 60.456 42.227 ;
     RECT  2.4 39.493 3.144 42.325 ;
     RECT  5.472 42.227 6.168 42.419 ;
     RECT  72 41.605 73.56 42.419 ;
     RECT  44.544 40.549 44.568 42.469 ;
     RECT  43.728 42.469 44.568 42.611 ;
     RECT  76.32 42.613 76.344 42.661 ;
     RECT  77.712 40.835 78.552 42.661 ;
     RECT  2.304 42.325 3.144 42.709 ;
     RECT  4.176 33.395 4.2 42.709 ;
     RECT  48.48 42.181 48.504 42.755 ;
     RECT  44.544 42.611 44.568 42.803 ;
     RECT  37.152 42.133 37.176 42.851 ;
     RECT  51 41.267 51.312 42.853 ;
     RECT  5.472 42.419 5.784 42.949 ;
     RECT  22.224 42.133 22.248 42.995 ;
     RECT  54.864 42.133 54.888 42.995 ;
     RECT  66.288 41.413 67.608 43.043 ;
     RECT  28.128 39.395 29.712 43.093 ;
     RECT  51 42.853 51.432 43.189 ;
     RECT  39.36 41.747 40.512 43.283 ;
     RECT  34.8 38.531 35.112 43.285 ;
     RECT  67.2 43.043 67.608 43.285 ;
     RECT  68.88 37.811 68.904 43.285 ;
     RECT  10.848 42.709 10.872 43.333 ;
     RECT  18.6 35.699 18.912 43.333 ;
     RECT  75.072 42.757 75.096 43.571 ;
     RECT  7.2 42.227 9.384 43.573 ;
     RECT  17.136 42.179 17.352 43.573 ;
     RECT  33.744 43.141 33.768 43.573 ;
     RECT  34.8 43.285 35.64 43.573 ;
     RECT  18.6 43.333 19.416 43.669 ;
     RECT  16.752 43.573 17.352 43.763 ;
     RECT  45.6 41.411 45.912 43.765 ;
     RECT  49.68 42.227 49.704 43.765 ;
     RECT  10.848 43.333 11.496 43.813 ;
     RECT  12.48 42.133 14.616 43.813 ;
     RECT  72 42.419 72.912 43.813 ;
     RECT  16.752 43.763 17.256 43.859 ;
     RECT  67.2 43.285 68.904 43.861 ;
     RECT  7.2 43.573 9.432 43.909 ;
     RECT  2.304 42.709 4.2 43.955 ;
     RECT  48.768 43.765 49.704 43.955 ;
     RECT  50.784 43.189 51.432 43.957 ;
     RECT  70.608 42.613 70.632 44.051 ;
     RECT  52.8 42.227 52.824 44.053 ;
     RECT  27.888 43.093 29.712 44.099 ;
     RECT  48.768 43.955 48.792 44.197 ;
     RECT  33.744 43.573 35.64 44.243 ;
     RECT  18.48 43.669 19.416 44.339 ;
     RECT  38.016 43.813 38.04 44.387 ;
     RECT  76.32 42.661 78.552 44.389 ;
     RECT  5.376 42.949 5.784 44.437 ;
     RECT  7.2 43.909 9.816 44.437 ;
     RECT  10.848 43.813 14.616 44.437 ;
     RECT  34.8 44.243 35.64 44.437 ;
     RECT  50.64 43.957 51.432 44.437 ;
     RECT  52.752 44.053 52.824 44.437 ;
     RECT  2.4 43.955 4.2 44.483 ;
     RECT  28.128 44.099 29.712 44.483 ;
     RECT  48.096 44.197 48.792 44.723 ;
     RECT  18.48 44.339 19.08 44.869 ;
     RECT  44.352 44.245 44.376 44.869 ;
     RECT  50.64 44.437 52.824 44.869 ;
     RECT  43.92 44.869 44.376 44.915 ;
     RECT  72 43.813 73.128 44.915 ;
     RECT  45.6 43.765 46.44 44.917 ;
     RECT  48.096 44.723 48.12 44.917 ;
     RECT  59.952 42.227 59.976 44.917 ;
     RECT  75.84 44.389 78.552 44.917 ;
     RECT  75.84 44.917 78.936 44.965 ;
     RECT  50.64 44.869 53.016 45.011 ;
     RECT  5.376 44.437 14.616 45.059 ;
     RECT  33.744 44.243 33.768 45.059 ;
     RECT  43.92 44.915 43.944 45.155 ;
     RECT  20.832 41.123 20.856 45.157 ;
     RECT  51 45.011 53.016 45.205 ;
     RECT  20.832 45.157 20.904 45.301 ;
     RECT  59.328 44.917 59.976 45.301 ;
     RECT  75.84 44.965 79.032 45.301 ;
     RECT  20.784 45.301 20.904 45.397 ;
     RECT  40.2 43.283 40.512 45.397 ;
     RECT  67.2 43.861 69.192 45.397 ;
     RECT  67.2 45.397 69.528 45.443 ;
     RECT  59.328 45.301 60.552 45.491 ;
     RECT  17.232 43.859 17.256 45.493 ;
     RECT  18.384 44.869 19.08 45.493 ;
     RECT  51 45.205 53.688 45.539 ;
     RECT  25.536 43.765 25.56 45.541 ;
     RECT  17.232 45.493 19.08 45.587 ;
     RECT  42.144 44.293 42.168 45.587 ;
     RECT  32.064 44.773 32.088 45.589 ;
     RECT  61.8 40.835 62.112 45.589 ;
     RECT  28.128 44.483 28.152 45.733 ;
     RECT  29.136 44.483 29.712 45.733 ;
     RECT  16.128 45.349 16.152 45.781 ;
     RECT  32.016 45.589 32.088 45.781 ;
     RECT  20.784 45.397 21.24 45.923 ;
     RECT  32.016 45.781 32.664 45.923 ;
     RECT  45.6 44.917 48.12 45.925 ;
     RECT  11.952 45.059 14.616 45.971 ;
     RECT  15.984 45.781 16.152 45.971 ;
     RECT  34.8 44.437 35.88 45.973 ;
     RECT  39.36 45.397 40.512 45.973 ;
     RECT  5.376 45.059 10.872 46.021 ;
     RECT  11.952 45.971 14.328 46.021 ;
     RECT  32.64 45.923 32.664 46.069 ;
     RECT  33.936 45.973 35.88 46.069 ;
     RECT  64.032 45.541 64.056 46.069 ;
     RECT  32.64 46.069 35.88 46.115 ;
     RECT  39.36 45.973 40.92 46.115 ;
     RECT  15.984 45.971 16.008 46.117 ;
     RECT  51 45.539 53.016 46.117 ;
     RECT  64.032 46.069 64.68 46.117 ;
     RECT  45.504 45.925 48.12 46.211 ;
     RECT  59.952 45.491 60.552 46.211 ;
     RECT  34.8 46.115 35.88 46.213 ;
     RECT  67.2 45.443 68.424 46.259 ;
     RECT  45.6 46.211 48.12 46.307 ;
     RECT  2.4 44.483 3.48 46.357 ;
     RECT  17.232 45.587 19.032 46.405 ;
     RECT  28.128 45.733 29.712 46.643 ;
     RECT  5.376 46.021 14.328 46.645 ;
     RECT  24 42.035 24.312 46.693 ;
     RECT  25.536 45.541 25.656 46.693 ;
     RECT  24 46.693 25.656 46.787 ;
     RECT  34.8 46.213 36.456 46.787 ;
     RECT  61.584 45.589 62.112 46.787 ;
     RECT  75.84 45.301 79.8 46.789 ;
     RECT  34.8 46.787 35.64 47.027 ;
     RECT  17.088 46.405 19.032 47.029 ;
     RECT  72 44.915 72.912 47.029 ;
     RECT  4.704 46.645 14.328 47.075 ;
     RECT  16.992 47.029 19.032 47.125 ;
     RECT  64.032 46.117 64.968 47.173 ;
     RECT  45.6 46.307 47.88 47.219 ;
     RECT  33.6 46.115 33.624 47.269 ;
     RECT  45.6 47.219 47.64 47.269 ;
     RECT  63.936 47.173 64.968 47.269 ;
     RECT  33.168 47.269 33.624 47.315 ;
     RECT  56.4 41.411 56.712 47.317 ;
     RECT  69.504 45.443 69.528 47.317 ;
     RECT  5.76 47.075 14.328 47.363 ;
     RECT  26.736 46.309 26.76 47.363 ;
     RECT  39.36 46.115 40.512 47.363 ;
     RECT  54.72 45.781 54.744 47.363 ;
     RECT  40.2 47.363 40.512 47.365 ;
     RECT  24 46.787 25.56 47.459 ;
     RECT  25.344 47.459 25.56 47.555 ;
     RECT  50.112 46.117 53.016 47.605 ;
     RECT  40.2 47.365 41.016 47.651 ;
     RECT  48.912 47.509 48.936 47.699 ;
     RECT  5.76 47.363 14.04 47.795 ;
     RECT  44.976 47.269 47.64 47.795 ;
     RECT  75.552 46.789 79.8 47.797 ;
     RECT  15.456 46.117 16.008 47.845 ;
     RECT  16.992 47.125 19.272 47.845 ;
     RECT  20.832 45.923 21.24 47.845 ;
     RECT  22.368 46.117 22.392 47.845 ;
     RECT  50.112 47.605 53.352 47.891 ;
     RECT  38.208 46.645 38.232 47.939 ;
     RECT  71.52 47.029 72.912 48.083 ;
     RECT  2.4 46.357 3.528 48.085 ;
     RECT  4.704 47.075 4.728 48.085 ;
     RECT  28.128 46.643 28.152 48.085 ;
     RECT  29.28 46.643 29.712 48.085 ;
     RECT  72 48.083 72.912 48.085 ;
     RECT  54.96 47.413 54.984 48.133 ;
     RECT  56.4 47.317 56.808 48.179 ;
     RECT  2.4 48.085 4.728 48.325 ;
     RECT  5.76 47.795 10.008 48.325 ;
     RECT  33.168 47.315 33.384 48.371 ;
     RECT  51 47.891 53.352 48.371 ;
     RECT  20.832 47.845 22.392 48.419 ;
     RECT  33.168 48.371 33.192 48.419 ;
     RECT  38.352 48.325 38.376 48.467 ;
     RECT  59.952 46.211 59.976 48.563 ;
     RECT  72 48.085 73.272 48.563 ;
     RECT  36.96 46.981 36.984 48.565 ;
     RECT  2.4 48.325 10.008 48.659 ;
     RECT  36.96 48.565 37.176 48.803 ;
     RECT  24 47.459 24.312 48.805 ;
     RECT  25.344 47.555 25.368 48.805 ;
     RECT  44.448 48.421 44.472 48.805 ;
     RECT  45.6 47.795 47.64 48.805 ;
     RECT  67.2 46.259 67.512 48.853 ;
     RECT  68.544 47.317 69.528 48.853 ;
     RECT  67.2 48.853 69.528 48.899 ;
     RECT  61.8 46.787 62.112 48.901 ;
     RECT  15.456 47.845 19.272 48.947 ;
     RECT  66.144 47.845 66.168 48.947 ;
     RECT  74.64 47.797 79.8 48.947 ;
     RECT  40.2 47.651 40.512 48.997 ;
     RECT  67.2 48.899 68.424 48.997 ;
     RECT  5.184 48.659 10.008 49.043 ;
     RECT  20.832 48.419 22.104 49.043 ;
     RECT  28.128 48.085 29.712 49.043 ;
     RECT  63.888 47.269 64.968 49.043 ;
     RECT  44.448 48.805 47.64 49.045 ;
     RECT  49.392 48.901 49.416 49.045 ;
     RECT  20.832 49.043 21.24 49.091 ;
     RECT  52.992 48.371 53.352 49.091 ;
     RECT  72 48.563 72.912 49.091 ;
     RECT  15.456 48.947 19.032 49.187 ;
     RECT  51 48.371 51.864 49.187 ;
     RECT  53.28 49.091 53.352 49.187 ;
     RECT  63.888 49.043 64.824 49.189 ;
     RECT  2.4 48.659 4.008 49.235 ;
     RECT  36.96 48.803 37.032 49.235 ;
     RECT  40.2 48.997 41.016 49.283 ;
     RECT  66.72 48.997 68.424 49.427 ;
     RECT  16.992 49.187 19.032 49.475 ;
     RECT  31.056 47.749 31.08 49.477 ;
     RECT  31.056 49.477 31.8 49.523 ;
     RECT  20.976 49.091 21.24 49.571 ;
     RECT  44.448 49.045 49.416 49.573 ;
     RECT  51 49.187 51.624 49.573 ;
     RECT  16.992 49.475 17.256 49.619 ;
     RECT  20.976 49.571 21.096 49.619 ;
     RECT  63.264 49.189 64.824 49.619 ;
     RECT  44.448 49.573 51.624 49.715 ;
     RECT  61.8 48.901 62.28 49.715 ;
     RECT  34.8 47.027 35.592 49.811 ;
     RECT  54.96 48.133 55.32 49.813 ;
     RECT  56.4 48.179 56.712 49.813 ;
     RECT  45.216 49.715 51.312 49.859 ;
     RECT  5.76 49.043 10.008 49.861 ;
     RECT  10.992 47.795 14.04 49.861 ;
     RECT  63.264 49.619 63.288 50.003 ;
     RECT  5.76 49.861 14.04 50.005 ;
     RECT  36.96 49.235 36.984 50.005 ;
     RECT  36.48 50.005 36.984 50.051 ;
     RECT  45.216 49.859 47.64 50.051 ;
     RECT  54.96 49.813 56.712 50.051 ;
     RECT  67.2 49.427 68.424 50.051 ;
     RECT  54.96 50.051 54.984 50.053 ;
     RECT  5.76 50.005 14.136 50.101 ;
     RECT  58.656 50.005 58.68 50.101 ;
     RECT  74.832 48.947 79.8 50.101 ;
     RECT  58.08 50.101 58.68 50.147 ;
     RECT  16.992 49.619 17.016 50.195 ;
     RECT  29.232 49.043 29.712 50.195 ;
     RECT  53.28 49.187 53.304 50.195 ;
     RECT  69.504 48.899 69.528 50.195 ;
     RECT  24 48.805 25.368 50.243 ;
     RECT  49.392 49.859 51.312 50.243 ;
     RECT  45.216 50.051 46.728 50.291 ;
     RECT  29.28 50.195 29.712 50.339 ;
     RECT  31.776 49.523 31.8 50.339 ;
     RECT  25.344 50.243 25.368 50.629 ;
     RECT  25.344 50.629 25.656 50.675 ;
     RECT  18.6 49.475 19.032 50.677 ;
     RECT  67.2 50.051 67.848 50.723 ;
     RECT  2.4 49.235 3.528 50.725 ;
     RECT  58.08 50.147 58.104 50.771 ;
     RECT  74.352 50.101 79.8 50.771 ;
     RECT  49.392 50.243 49.416 50.819 ;
     RECT  45.6 50.291 46.728 50.867 ;
     RECT  40.2 49.283 40.512 50.965 ;
     RECT  74.352 50.771 79.512 50.965 ;
     RECT  17.952 50.677 19.032 51.205 ;
     RECT  21.072 49.619 21.096 51.205 ;
     RECT  50.88 50.243 51.312 51.253 ;
     RECT  5.28 50.101 14.136 51.299 ;
     RECT  17.904 51.205 19.032 51.301 ;
     RECT  20.208 51.205 21.096 51.301 ;
     RECT  50.88 51.253 52.248 51.301 ;
     RECT  28.128 49.043 28.152 51.347 ;
     RECT  59.856 50.677 59.88 51.347 ;
     RECT  2.4 50.725 4.008 51.349 ;
     RECT  45.6 50.867 46.248 51.349 ;
     RECT  64.8 49.619 64.824 51.349 ;
     RECT  2.304 51.349 4.008 51.397 ;
     RECT  56.4 50.051 56.712 51.397 ;
     RECT  50.88 51.301 52.728 51.443 ;
     RECT  1.968 51.397 4.008 51.493 ;
     RECT  34.8 49.811 35.112 51.493 ;
     RECT  47.76 51.397 47.784 51.539 ;
     RECT  56.4 51.397 56.808 51.539 ;
     RECT  50.88 51.443 52.392 51.685 ;
     RECT  34.8 51.493 35.208 51.731 ;
     RECT  15.456 49.187 15.48 51.829 ;
     RECT  5.76 51.299 14.136 51.877 ;
     RECT  15.456 51.829 16.392 51.877 ;
     RECT  25.632 50.675 25.656 51.923 ;
     RECT  36.48 50.051 36.504 51.923 ;
     RECT  54.672 50.053 54.984 51.923 ;
     RECT  15.456 51.877 16.584 51.971 ;
     RECT  54.96 51.923 54.984 51.971 ;
     RECT  5.76 51.877 14.28 51.973 ;
     RECT  64.224 51.349 64.824 52.021 ;
     RECT  72.6 49.091 72.912 52.021 ;
     RECT  5.76 51.973 15.192 52.355 ;
     RECT  29.4 50.339 29.712 52.405 ;
     RECT  45.168 51.349 46.248 52.453 ;
     RECT  74.304 50.965 79.512 52.499 ;
     RECT  64.224 52.021 65.256 52.549 ;
     RECT  74.304 52.499 78.408 52.595 ;
     RECT  44.976 52.453 46.248 52.789 ;
     RECT  64.176 52.549 65.256 52.789 ;
     RECT  1.776 51.493 4.008 52.885 ;
     RECT  67.2 50.723 67.512 52.981 ;
     RECT  29.4 52.405 30.312 53.075 ;
     RECT  39.408 50.965 40.512 53.075 ;
     RECT  69.936 52.261 69.96 53.075 ;
     RECT  72.6 52.021 73.176 53.075 ;
     RECT  79.488 52.499 79.512 53.075 ;
     RECT  74.352 52.595 78.408 53.123 ;
     RECT  32.976 52.405 33 53.267 ;
     RECT  64.176 52.789 65.448 53.317 ;
     RECT  34.8 51.731 35.112 53.365 ;
     RECT  34.416 53.365 35.112 53.507 ;
     RECT  1.584 52.885 4.008 53.557 ;
     RECT  5.76 52.355 14.28 53.557 ;
     RECT  16.272 51.971 16.584 53.557 ;
     RECT  17.904 51.301 21.096 53.557 ;
     RECT  24 50.243 24.312 53.557 ;
     RECT  44.496 52.789 46.248 53.557 ;
     RECT  50.4 51.685 52.392 53.557 ;
     RECT  64.176 53.317 65.928 53.557 ;
     RECT  67.2 52.981 67.656 53.603 ;
     RECT  1.584 53.557 4.104 53.605 ;
     RECT  5.328 53.557 14.28 53.605 ;
     RECT  24 53.557 26.856 53.605 ;
     RECT  43.824 53.557 46.344 53.605 ;
     RECT  43.824 53.605 46.44 53.653 ;
     RECT  43.824 53.653 46.632 53.941 ;
     RECT  50.064 53.557 52.68 53.941 ;
     RECT  1.584 53.605 14.28 53.989 ;
     RECT  29.4 53.075 29.712 54.009 ;
     RECT  34.8 53.507 35.112 54.009 ;
     RECT  40.2 53.075 40.512 54.009 ;
     RECT  56.4 51.539 56.712 54.009 ;
     RECT  61.8 49.715 62.112 54.009 ;
     RECT  67.2 53.603 67.512 54.009 ;
     RECT  72.6 53.075 72.912 54.009 ;
     RECT  24 53.605 27.432 54.023 ;
     RECT  29.4 54.009 29.52 54.023 ;
     RECT  34.8 54.009 34.92 54.023 ;
     RECT  40.2 54.009 40.32 54.023 ;
     RECT  56.4 54.009 56.52 54.023 ;
     RECT  61.8 54.009 61.92 54.023 ;
     RECT  67.2 54.009 67.32 54.023 ;
     RECT  72.6 54.009 72.72 54.023 ;
     RECT  1.584 53.989 14.376 54.037 ;
     RECT  15.504 53.557 21.096 54.037 ;
     RECT  63.696 53.557 65.928 54.037 ;
     RECT  1.584 54.037 21.096 54.085 ;
     RECT  50.064 53.941 52.872 54.085 ;
     RECT  63.504 54.037 65.928 54.085 ;
     RECT  75.216 53.123 78.408 54.179 ;
     RECT  43.728 53.941 46.632 54.709 ;
     RECT  24.528 54.023 27.432 55.285 ;
     RECT  1.488 54.085 21.096 56.051 ;
     RECT  1.488 56.051 20.616 56.144 ;
     RECT  24.528 55.285 27.528 56.144 ;
     RECT  43.728 54.709 46.728 56.144 ;
     RECT  49.872 54.085 52.872 56.144 ;
     RECT  62.928 54.085 65.928 56.144 ;
     RECT  75.216 54.179 78.216 56.144 ;
  END
END ot_hgi_coll_fj_q2
END LIBRARY
